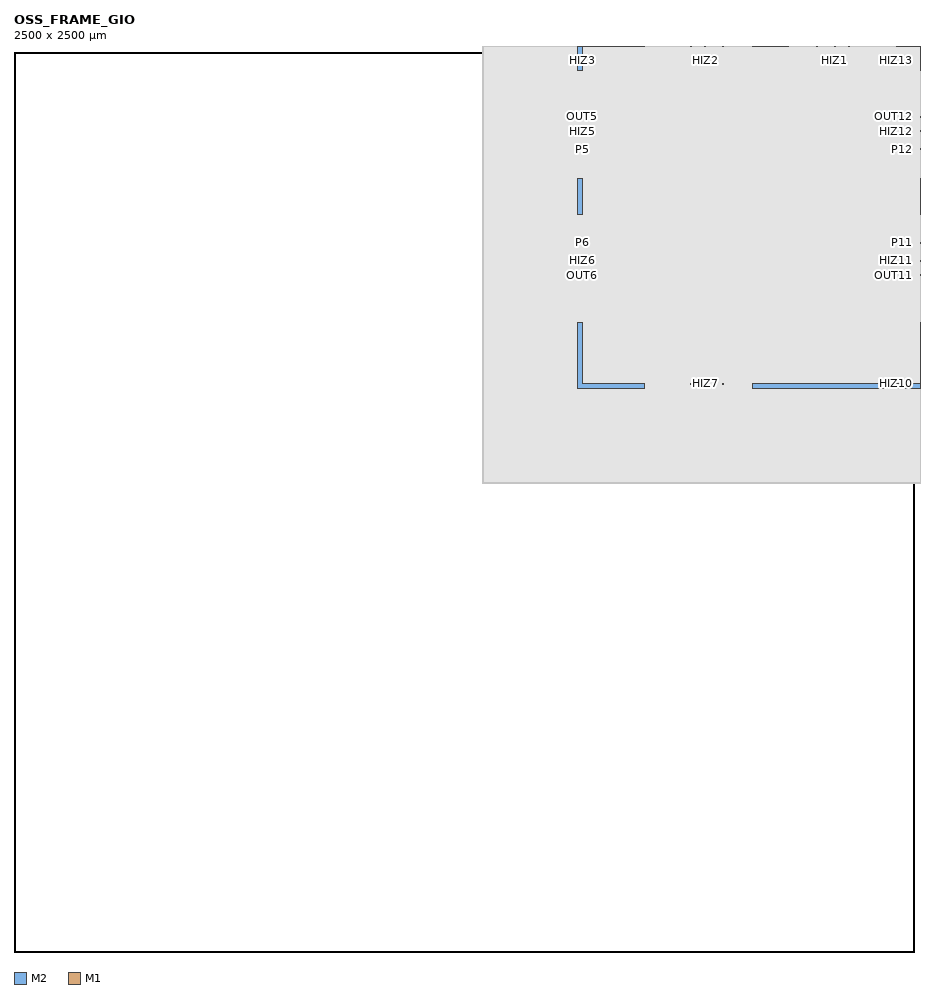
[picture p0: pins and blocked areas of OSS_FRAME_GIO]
MACRO OSS_FRAME_GIO
    CLASS COVER ;
    FOREIGN OSS_FRAME_GIO 1250.000 1250.000 ;
    ORIGIN 1250.000 1250.000 ;
    SIZE 2500.000 BY 2500.000 ;

    PIN HIZ1
        DIRECTION INPUT ;
        USE SIGNAL ;
        PORT
            LAYER M2 ;
                RECT 1028.300 2170.000 1031.700 2173.400 ;
        END
    END HIZ1

    PIN HIZ10
        DIRECTION INPUT ;
        USE SIGNAL ;
        PORT
            LAYER M2 ;
                RECT 1828.300 326.600 1831.700 330.000 ;
        END
    END HIZ10

    PIN HIZ11
        DIRECTION INPUT ;
        USE SIGNAL ;
        PORT
            LAYER M2 ;
                RECT 2170.000 668.300 2173.400 671.700 ;
        END
    END HIZ11

    PIN HIZ12
        DIRECTION INPUT ;
        USE SIGNAL ;
        PORT
            LAYER M2 ;
                RECT 2170.000 1028.300 2173.400 1031.700 ;
        END
    END HIZ12

    PIN HIZ13
        DIRECTION INPUT ;
        USE SIGNAL ;
        PORT
            LAYER M2 ;
                RECT 2170.000 1468.300 2173.400 1471.700 ;
        END
    END HIZ13

    PIN HIZ14
        DIRECTION INPUT ;
        USE SIGNAL ;
        PORT
            LAYER M2 ;
                RECT 2170.000 1828.300 2173.400 1831.700 ;
        END
    END HIZ14

    PIN HIZ15
        DIRECTION INPUT ;
        USE SIGNAL ;
        PORT
            LAYER M2 ;
                RECT 1828.300 2170.000 1831.700 2173.400 ;
        END
    END HIZ15

    PIN HIZ2
        DIRECTION INPUT ;
        USE SIGNAL ;
        PORT
            LAYER M2 ;
                RECT 668.300 2170.000 671.700 2173.400 ;
        END
    END HIZ2

    PIN HIZ3
        DIRECTION INPUT ;
        USE SIGNAL ;
        PORT
            LAYER M2 ;
                RECT 326.600 1828.300 330.000 1831.700 ;
        END
    END HIZ3

    PIN HIZ4
        DIRECTION INPUT ;
        USE SIGNAL ;
        PORT
            LAYER M2 ;
                RECT 326.600 1468.300 330.000 1471.700 ;
        END
    END HIZ4

    PIN HIZ5
        DIRECTION INPUT ;
        USE SIGNAL ;
        PORT
            LAYER M2 ;
                RECT 326.600 1028.300 330.000 1031.700 ;
        END
    END HIZ5

    PIN HIZ6
        DIRECTION INPUT ;
        USE SIGNAL ;
        PORT
            LAYER M2 ;
                RECT 326.600 668.300 330.000 671.700 ;
        END
    END HIZ6

    PIN HIZ7
        DIRECTION INPUT ;
        USE SIGNAL ;
        PORT
            LAYER M2 ;
                RECT 668.300 326.600 671.700 330.000 ;
        END
    END HIZ7

    PIN HIZ9
        DIRECTION INPUT ;
        USE SIGNAL ;
        PORT
            LAYER M2 ;
                RECT 1468.300 326.600 1471.700 330.000 ;
        END
    END HIZ9

    PIN OUT1
        DIRECTION INPUT ;
        USE SIGNAL ;
        PORT
            LAYER M2 ;
                RECT 1068.300 2170.000 1071.700 2173.400 ;
        END
    END OUT1

    PIN OUT10
        DIRECTION INPUT ;
        USE SIGNAL ;
        PORT
            LAYER M2 ;
                RECT 1868.300 326.600 1871.700 330.000 ;
        END
    END OUT10

    PIN OUT11
        DIRECTION INPUT ;
        USE SIGNAL ;
        PORT
            LAYER M2 ;
                RECT 2170.000 628.300 2173.400 631.700 ;
        END
    END OUT11

    PIN OUT12
        DIRECTION INPUT ;
        USE SIGNAL ;
        PORT
            LAYER M2 ;
                RECT 2170.000 1068.300 2173.400 1071.700 ;
        END
    END OUT12

    PIN OUT13
        DIRECTION INPUT ;
        USE SIGNAL ;
        PORT
            LAYER M2 ;
                RECT 2170.000 1428.300 2173.400 1431.700 ;
        END
    END OUT13

    PIN OUT14
        DIRECTION INPUT ;
        USE SIGNAL ;
        PORT
            LAYER M2 ;
                RECT 2170.000 1868.300 2173.400 1871.700 ;
        END
    END OUT14

    PIN OUT15
        DIRECTION INPUT ;
        USE SIGNAL ;
        PORT
            LAYER M2 ;
                RECT 1868.300 2170.000 1871.700 2173.400 ;
        END
    END OUT15

    PIN OUT2
        DIRECTION INPUT ;
        USE SIGNAL ;
        PORT
            LAYER M2 ;
                RECT 628.300 2170.000 631.700 2173.400 ;
        END
    END OUT2

    PIN OUT3
        DIRECTION INPUT ;
        USE SIGNAL ;
        PORT
            LAYER M2 ;
                RECT 326.600 1868.300 330.000 1871.700 ;
        END
    END OUT3

    PIN OUT4
        DIRECTION INPUT ;
        USE SIGNAL ;
        PORT
            LAYER M2 ;
                RECT 326.600 1428.300 330.000 1431.700 ;
        END
    END OUT4

    PIN OUT5
        DIRECTION INPUT ;
        USE SIGNAL ;
        PORT
            LAYER M2 ;
                RECT 326.600 1068.300 330.000 1071.700 ;
        END
    END OUT5

    PIN OUT6
        DIRECTION INPUT ;
        USE SIGNAL ;
        PORT
            LAYER M2 ;
                RECT 326.600 628.300 330.000 631.700 ;
        END
    END OUT6

    PIN OUT7
        DIRECTION INPUT ;
        USE SIGNAL ;
        PORT
            LAYER M2 ;
                RECT 628.300 326.600 631.700 330.000 ;
        END
    END OUT7

    PIN OUT9
        DIRECTION INPUT ;
        USE SIGNAL ;
        PORT
            LAYER M2 ;
                RECT 1428.300 326.600 1431.700 330.000 ;
        END
    END OUT9

    PIN P1
        DIRECTION OUTPUT ;
        USE SIGNAL ;
        PORT
            LAYER M2 ;
                RECT 978.300 2170.000 981.700 2173.400 ;
        END
    END P1

    PIN P10
        DIRECTION OUTPUT ;
        USE SIGNAL ;
        PORT
            LAYER M2 ;
                RECT 1778.300 326.600 1781.700 330.000 ;
        END
    END P10

    PIN P11
        DIRECTION OUTPUT ;
        USE SIGNAL ;
        PORT
            LAYER M2 ;
                RECT 2170.000 718.300 2173.400 721.700 ;
        END
    END P11

    PIN P12
        DIRECTION OUTPUT ;
        USE SIGNAL ;
        PORT
            LAYER M2 ;
                RECT 2170.000 978.300 2173.400 981.700 ;
        END
    END P12

    PIN P13
        DIRECTION OUTPUT ;
        USE SIGNAL ;
        PORT
            LAYER M2 ;
                RECT 2170.000 1518.300 2173.400 1521.700 ;
        END
    END P13

    PIN P14
        DIRECTION OUTPUT ;
        USE SIGNAL ;
        PORT
            LAYER M2 ;
                RECT 2170.000 1778.300 2173.400 1781.700 ;
        END
    END P14

    PIN P15
        DIRECTION OUTPUT ;
        USE SIGNAL ;
        PORT
            LAYER M2 ;
                RECT 1778.300 2170.000 1781.700 2173.400 ;
        END
    END P15

    PIN P2
        DIRECTION OUTPUT ;
        USE SIGNAL ;
        PORT
            LAYER M2 ;
                RECT 718.300 2170.000 721.700 2173.400 ;
        END
    END P2

    PIN P3
        DIRECTION OUTPUT ;
        USE SIGNAL ;
        PORT
            LAYER M2 ;
                RECT 326.600 1778.300 330.000 1781.700 ;
        END
    END P3

    PIN P4
        DIRECTION OUTPUT ;
        USE SIGNAL ;
        PORT
            LAYER M2 ;
                RECT 326.600 1518.300 330.000 1521.700 ;
        END
    END P4

    PIN P5
        DIRECTION OUTPUT ;
        USE SIGNAL ;
        PORT
            LAYER M2 ;
                RECT 326.600 978.300 330.000 981.700 ;
        END
    END P5

    PIN P6
        DIRECTION OUTPUT ;
        USE SIGNAL ;
        PORT
            LAYER M2 ;
                RECT 326.600 718.300 330.000 721.700 ;
        END
    END P6

    PIN P7
        DIRECTION OUTPUT ;
        USE SIGNAL ;
        PORT
            LAYER M2 ;
                RECT 718.300 326.600 721.700 330.000 ;
        END
    END P7

    PIN P9
        DIRECTION OUTPUT ;
        USE SIGNAL ;
        PORT
            LAYER M2 ;
                RECT 1518.300 326.600 1521.700 330.000 ;
        END
    END P9

    PIN VDD
        DIRECTION INOUT ;
        USE POWER ;
        PORT
            LAYER M1 ;
                RECT 1300.000 2170.000 1600.000 2184.000 ;
        END
    END VDD

    PIN VSS
        DIRECTION INOUT ;
        USE GROUND ;
        PORT
            LAYER M2 ;
                RECT 800.000 2170.000 900.000 2184.000 ;
            LAYER M2 ;
                RECT 1200.000 2170.000 1700.000 2184.000 ;
            LAYER M2 ;
                POLYGON 2170.000 2000.000  2170.000 2170.000  2000.000 2170.000  2000.000 2184.000  2184.000 2184.000  2184.000 2000.000 ;
            LAYER M2 ;
                RECT 316.000 1600.000 330.000 1700.000 ;
            LAYER M2 ;
                RECT 316.000 1200.000 330.000 1300.000 ;
            LAYER M2 ;
                RECT 316.000 800.000 330.000 900.000 ;
            LAYER M2 ;
                POLYGON 316.000 316.000  316.000 500.000  330.000 500.000  330.000 330.000  500.000 330.000  500.000 316.000 ;
            LAYER M2 ;
                RECT 800.000 316.000 1300.000 330.000 ;
            LAYER M2 ;
                RECT 1600.000 316.000 1700.000 330.000 ;
            LAYER M2 ;
                POLYGON 2000.000 316.000  2000.000 330.000  2170.000 330.000  2170.000 500.000  2184.000 500.000  2184.000 316.000 ;
            LAYER M2 ;
                RECT 2170.000 800.000 2184.000 900.000 ;
            LAYER M2 ;
                RECT 2170.000 1200.000 2184.000 1300.000 ;
            LAYER M2 ;
                RECT 2170.000 1600.000 2184.000 1700.000 ;
            LAYER M2 ;
                POLYGON 316.000 2000.000  316.000 2184.000  500.000 2184.000  500.000 2170.000  330.000 2170.000  330.000 2000.000 ;
        END
    END VSS

    OBS
        LAYER M1 ;
            POLYGON 90.000 90.000  90.000 2410.000  2410.000 2410.000  2410.000 90.000 ;
            POLYGON 52.000 52.000  52.000 2448.000  2448.000 2448.000  2448.000 52.000 ;
            POLYGON 2192.400 1835.100  2192.400 1835.400  2190.400 1835.400  2190.400 1838.000  2192.400 1838.000  2192.400 1840.200  2182.400 1840.200  2182.400 1842.800  2192.400 1842.800  2192.400 1848.700  2177.200 1848.700  2177.200 1848.300  2170.000 1848.300  2170.000 1851.700  2177.200 1851.700  2177.200 1851.300  2192.400 1851.300  2192.400 1858.400  2183.200 1858.400  2183.200 1862.000  2182.400 1862.000  2182.400 1864.600  2185.000 1864.600  2185.000 1860.200  2192.400 1860.200  2192.400 1862.000  2190.400 1862.000  2190.400 1864.600  2192.400 1864.600  2192.400 1864.900  2195.000 1864.900  2195.000 1851.300  2200.000 1851.300  2200.000 1848.700  2195.000 1848.700  2195.000 1835.100 ;
            POLYGON 2226.000 1772.000  2226.000 1778.300  2170.000 1778.300  2170.000 1781.700  2226.000 1781.700  2226.000 1812.000  2240.000 1812.000  2240.000 1928.000  2340.000 1928.000  2340.000 1772.000 ;
            POLYGON 2180.900 1788.700  2180.900 1791.300  2192.400 1791.300  2192.400 1809.300  2182.400 1809.300  2182.400 1817.700  2185.000 1817.700  2185.000 1811.100  2192.400 1811.100  2192.400 1812.900  2190.400 1812.900  2190.400 1817.900  2195.000 1817.900  2195.000 1791.300  2206.800 1791.300  2206.800 1908.700  2195.000 1908.700  2195.000 1882.100  2190.400 1882.100  2190.400 1894.100  2182.400 1894.100  2182.400 1898.700  2190.400 1898.700  2190.400 1908.700  2180.900 1908.700  2180.900 1911.300  2192.000 1911.300  2192.000 2018.000  2222.800 2018.000  2222.800 2021.400  2356.700 2021.400  2356.700 2018.000  2383.500 2018.000  2383.500 1942.000  2200.000 1942.000  2200.000 1911.300  2208.600 1911.300  2208.600 1788.700 ;
            POLYGON 1848.300 2170.000  1848.300 2177.200  1848.700 2177.200  1848.700 2192.400  1842.800 2192.400  1842.800 2182.400  1840.200 2182.400  1840.200 2192.400  1838.000 2192.400  1838.000 2190.400  1835.400 2190.400  1835.400 2192.400  1835.100 2192.400  1835.100 2195.000  1848.700 2195.000  1848.700 2200.000  1851.300 2200.000  1851.300 2195.000  1864.900 2195.000  1864.900 2192.400  1864.600 2192.400  1864.600 2190.400  1862.000 2190.400  1862.000 2192.400  1860.200 2192.400  1860.200 2185.000  1864.600 2185.000  1864.600 2182.400  1862.000 2182.400  1862.000 2183.200  1858.400 2183.200  1858.400 2192.400  1851.300 2192.400  1851.300 2177.200  1851.700 2177.200  1851.700 2170.000 ;
            POLYGON 1778.300 2170.000  1778.300 2226.000  1772.000 2226.000  1772.000 2340.000  1928.000 2340.000  1928.000 2240.000  1812.000 2240.000  1812.000 2226.000  1781.700 2226.000  1781.700 2170.000 ;
            POLYGON 1788.700 2180.900  1788.700 2208.600  1911.300 2208.600  1911.300 2200.000  1942.000 2200.000  1942.000 2383.500  2018.000 2383.500  2018.000 2356.700  2021.400 2356.700  2021.400 2222.800  2018.000 2222.800  2018.000 2192.000  1911.300 2192.000  1911.300 2180.900  1908.700 2180.900  1908.700 2190.400  1898.700 2190.400  1898.700 2182.400  1894.100 2182.400  1894.100 2190.400  1882.100 2190.400  1882.100 2195.000  1908.700 2195.000  1908.700 2206.800  1791.300 2206.800  1791.300 2195.000  1817.900 2195.000  1817.900 2190.400  1812.900 2190.400  1812.900 2192.400  1811.100 2192.400  1811.100 2185.000  1817.700 2185.000  1817.700 2182.400  1809.300 2182.400  1809.300 2192.400  1791.300 2192.400  1791.300 2180.900 ;
            POLYGON 2178.400 1853.700  2178.400 1856.300  2181.000 1856.300  2181.000 1853.700 ;
            POLYGON 2202.000 1946.800  2202.000 1953.700  2205.400 1953.700  2205.400 1949.400  2223.200 1949.400  2223.200 1953.600  2225.800 1953.600  2225.800 1949.400  2234.200 1949.400  2234.200 1953.600  2236.800 1953.600  2236.800 1949.400  2253.200 1949.400  2253.200 1953.600  2255.800 1953.600  2255.800 1949.400  2264.200 1949.400  2264.200 1953.600  2266.800 1953.600  2266.800 1949.400  2283.200 1949.400  2283.200 1953.600  2285.800 1953.600  2285.800 1949.400  2294.200 1949.400  2294.200 1953.600  2296.800 1953.600  2296.800 1946.800 ;
            POLYGON 2209.000 1951.600  2209.000 1955.000  2209.500 1955.000  2209.500 2005.000  2209.000 2005.000  2209.000 2011.300  2218.200 2011.300  2218.200 2005.000  2217.700 2005.000  2217.700 1955.000  2218.200 1955.000  2218.200 1951.600 ;
            POLYGON 2228.300 1951.600  2228.300 1955.000  2227.300 1955.000  2227.300 2005.000  2226.800 2005.000  2226.800 2011.300  2233.200 2011.300  2233.200 2005.000  2232.700 2005.000  2232.700 1955.000  2231.700 1955.000  2231.700 1951.600 ;
            POLYGON 2240.400 1951.600  2240.400 1955.000  2239.500 1955.000  2239.500 2005.000  2240.400 2005.000  2240.400 2011.300  2249.600 2011.300  2249.600 2005.000  2250.500 2005.000  2250.500 1955.000  2249.600 1955.000  2249.600 1951.600 ;
            POLYGON 2258.300 1951.600  2258.300 1955.000  2257.300 1955.000  2257.300 2005.000  2256.800 2005.000  2256.800 2011.300  2263.200 2011.300  2263.200 2005.000  2262.700 2005.000  2262.700 1955.000  2261.700 1955.000  2261.700 1951.600 ;
            POLYGON 2270.400 1951.600  2270.400 1955.000  2269.500 1955.000  2269.500 2005.000  2270.400 2005.000  2270.400 2011.300  2279.600 2011.300  2279.600 2005.000  2280.500 2005.000  2280.500 1955.000  2279.600 1955.000  2279.600 1951.600 ;
            POLYGON 2288.300 1951.600  2288.300 1955.000  2287.300 1955.000  2287.300 2005.000  2286.800 2005.000  2286.800 2011.300  2293.200 2011.300  2293.200 2005.000  2292.700 2005.000  2292.700 1955.000  2291.700 1955.000  2291.700 1951.600 ;
            POLYGON 2300.400 1951.600  2300.400 1955.000  2299.500 1955.000  2299.500 2005.000  2300.400 2005.000  2300.400 2011.300  2309.600 2011.300  2309.600 2005.000  2310.500 2005.000  2310.500 1955.000  2309.600 1955.000  2309.600 1951.600 ;
            POLYGON 2318.300 1951.600  2318.300 1955.000  2317.300 1955.000  2317.300 2005.000  2316.800 2005.000  2316.800 2011.300  2323.200 2011.300  2323.200 2005.000  2322.700 2005.000  2322.700 1955.000  2321.700 1955.000  2321.700 1951.600 ;
            POLYGON 2330.400 1951.600  2330.400 1955.000  2329.500 1955.000  2329.500 2005.000  2330.400 2005.000  2330.400 2011.300  2339.600 2011.300  2339.600 2005.000  2340.500 2005.000  2340.500 1955.000  2339.600 1955.000  2339.600 1951.600 ;
            POLYGON 2348.200 1951.600  2348.200 1955.000  2347.300 1955.000  2347.300 2005.000  2346.800 2005.000  2346.800 2011.300  2353.200 2011.300  2353.200 2005.000  2352.700 2005.000  2352.700 1955.000  2351.600 1955.000  2351.600 1951.600 ;
            POLYGON 2361.800 1951.600  2361.800 1955.000  2362.300 1955.000  2362.300 2005.000  2361.800 2005.000  2361.800 2011.300  2371.000 2011.300  2371.000 2005.000  2370.500 2005.000  2370.500 1955.000  2371.000 1955.000  2371.000 1951.600 ;
            POLYGON 2172.000 1861.400  2172.000 1868.300  2170.000 1868.300  2170.000 1871.700  2176.200 1871.700  2176.200 1868.300  2175.600 1868.300  2175.600 1861.400 ;
            POLYGON 1868.300 2170.000  1868.300 2172.000  1861.400 2172.000  1861.400 2175.600  1868.300 2175.600  1868.300 2176.200  1871.700 2176.200  1871.700 2170.000 ;
            POLYGON 1853.700 2178.400  1853.700 2181.000  1856.300 2181.000  1856.300 2178.400 ;
            POLYGON 1862.000 2178.400  1862.000 2181.000  1904.400 2181.000  1904.400 2188.000  1907.000 2188.000  1907.000 2185.400  1906.200 2185.400  1906.200 2178.400  1894.100 2178.400  1894.100 2179.200  1864.600 2179.200  1864.600 2178.400 ;
            POLYGON 1882.900 2184.200  1882.900 2185.000  1872.100 2185.000  1872.100 2187.200  1864.600 2187.200  1864.600 2186.400  1862.000 2186.400  1862.000 2189.000  1872.100 2189.000  1872.100 2192.600  1871.700 2192.600  1871.700 2195.200  1874.300 2195.200  1874.300 2192.600  1873.900 2192.600  1873.900 2186.800  1891.500 2186.800  1891.500 2184.200 ;
            POLYGON 2186.400 1862.000  2186.400 1864.600  2187.200 1864.600  2187.200 1872.100  2185.000 1872.100  2185.000 1882.900  2184.200 1882.900  2184.200 1891.500  2186.800 1891.500  2186.800 1873.900  2192.600 1873.900  2192.600 1874.300  2195.200 1874.300  2195.200 1871.700  2192.600 1871.700  2192.600 1872.100  2189.000 1872.100  2189.000 1862.000 ;
            POLYGON 1858.300 2196.400  1858.300 2199.000  1903.900 2199.000  1903.900 2205.400  1907.300 2205.400  1907.300 2196.400  1882.100 2196.400  1882.100 2197.200  1864.900 2197.200  1864.900 2196.400 ;
            POLYGON 1951.600 2209.000  1951.600 2218.200  1955.000 2218.200  1955.000 2217.700  2005.000 2217.700  2005.000 2218.200  2011.300 2218.200  2011.300 2209.000  2005.000 2209.000  2005.000 2209.500  1955.000 2209.500  1955.000 2209.000 ;
            POLYGON 2005.000 2226.800  2005.000 2227.300  1955.000 2227.300  1955.000 2228.300  1951.600 2228.300  1951.600 2231.700  1955.000 2231.700  1955.000 2232.700  2005.000 2232.700  2005.000 2233.200  2011.300 2233.200  2011.300 2226.800 ;
            POLYGON 1955.000 2239.500  1955.000 2240.400  1951.600 2240.400  1951.600 2249.600  1955.000 2249.600  1955.000 2250.500  2005.000 2250.500  2005.000 2249.600  2011.300 2249.600  2011.300 2240.400  2005.000 2240.400  2005.000 2239.500 ;
            POLYGON 2005.000 2256.800  2005.000 2257.300  1955.000 2257.300  1955.000 2258.300  1951.600 2258.300  1951.600 2261.700  1955.000 2261.700  1955.000 2262.700  2005.000 2262.700  2005.000 2263.200  2011.300 2263.200  2011.300 2256.800 ;
            POLYGON 1955.000 2269.500  1955.000 2270.400  1951.600 2270.400  1951.600 2279.600  1955.000 2279.600  1955.000 2280.500  2005.000 2280.500  2005.000 2279.600  2011.300 2279.600  2011.300 2270.400  2005.000 2270.400  2005.000 2269.500 ;
            POLYGON 2005.000 2286.800  2005.000 2287.300  1955.000 2287.300  1955.000 2288.300  1951.600 2288.300  1951.600 2291.700  1955.000 2291.700  1955.000 2292.700  2005.000 2292.700  2005.000 2293.200  2011.300 2293.200  2011.300 2286.800 ;
            POLYGON 1946.800 2202.000  1946.800 2296.800  1953.600 2296.800  1953.600 2294.200  1949.400 2294.200  1949.400 2285.800  1953.600 2285.800  1953.600 2283.200  1949.400 2283.200  1949.400 2266.800  1953.600 2266.800  1953.600 2264.200  1949.400 2264.200  1949.400 2255.800  1953.600 2255.800  1953.600 2253.200  1949.400 2253.200  1949.400 2236.800  1953.600 2236.800  1953.600 2234.200  1949.400 2234.200  1949.400 2225.800  1953.600 2225.800  1953.600 2223.200  1949.400 2223.200  1949.400 2205.400  1953.700 2205.400  1953.700 2202.000 ;
            POLYGON 1955.000 2299.500  1955.000 2300.400  1951.600 2300.400  1951.600 2309.600  1955.000 2309.600  1955.000 2310.500  2005.000 2310.500  2005.000 2309.600  2011.300 2309.600  2011.300 2300.400  2005.000 2300.400  2005.000 2299.500 ;
            POLYGON 2005.000 2316.800  2005.000 2317.300  1955.000 2317.300  1955.000 2318.300  1951.600 2318.300  1951.600 2321.700  1955.000 2321.700  1955.000 2322.700  2005.000 2322.700  2005.000 2323.200  2011.300 2323.200  2011.300 2316.800 ;
            POLYGON 2178.400 1862.000  2178.400 1864.600  2179.200 1864.600  2179.200 1894.100  2178.400 1894.100  2178.400 1906.200  2185.400 1906.200  2185.400 1907.000  2188.000 1907.000  2188.000 1904.400  2181.000 1904.400  2181.000 1862.000 ;
            POLYGON 1955.000 2329.500  1955.000 2330.400  1951.600 2330.400  1951.600 2339.600  1955.000 2339.600  1955.000 2340.500  2005.000 2340.500  2005.000 2339.600  2011.300 2339.600  2011.300 2330.400  2005.000 2330.400  2005.000 2329.500 ;
            POLYGON 2005.000 2346.800  2005.000 2347.300  1955.000 2347.300  1955.000 2348.200  1951.600 2348.200  1951.600 2351.600  1955.000 2351.600  1955.000 2352.700  2005.000 2352.700  2005.000 2353.200  2011.300 2353.200  2011.300 2346.800 ;
            POLYGON 1951.600 2361.800  1951.600 2371.000  1955.000 2371.000  1955.000 2370.500  2005.000 2370.500  2005.000 2371.000  2011.300 2371.000  2011.300 2361.800  2005.000 2361.800  2005.000 2362.300  1955.000 2362.300  1955.000 2361.800 ;
            POLYGON 2196.400 1858.300  2196.400 1864.900  2197.200 1864.900  2197.200 1882.100  2196.400 1882.100  2196.400 1907.300  2205.400 1907.300  2205.400 1903.900  2199.000 1903.900  2199.000 1858.300 ;
            POLYGON 1695.000 2239.500  1695.000 2240.400  1688.700 2240.400  1688.700 2249.600  1695.000 2249.600  1695.000 2250.500  1745.000 2250.500  1745.000 2249.600  1748.400 2249.600  1748.400 2240.400  1745.000 2240.400  1745.000 2239.500 ;
            POLYGON 1792.700 2196.400  1792.700 2205.400  1796.100 2205.400  1796.100 2199.000  1841.700 2199.000  1841.700 2196.400  1835.100 2196.400  1835.100 2197.200  1817.900 2197.200  1817.900 2196.400 ;
            POLYGON 1746.300 2202.000  1746.300 2205.400  1750.000 2205.400  1750.000 2223.200  1746.400 2223.200  1746.400 2225.800  1750.000 2225.800  1750.000 2234.200  1746.400 2234.200  1746.400 2236.800  1750.000 2236.800  1750.000 2253.200  1746.400 2253.200  1746.400 2255.800  1751.800 2255.800  1751.800 2202.000 ;
            POLYGON 1345.000 2256.800  1345.000 2257.300  1295.000 2257.300  1295.000 2258.300  1291.600 2258.300  1291.600 2261.700  1295.000 2261.700  1295.000 2262.700  1345.000 2262.700  1345.000 2263.200  1351.300 2263.200  1351.300 2256.800 ;
            POLYGON 1605.000 2256.800  1605.000 2257.300  1555.000 2257.300  1555.000 2258.300  1551.600 2258.300  1551.600 2261.700  1555.000 2261.700  1555.000 2262.700  1605.000 2262.700  1605.000 2263.200  1611.300 2263.200  1611.300 2256.800 ;
            POLYGON 1688.700 2256.800  1688.700 2263.200  1695.000 2263.200  1695.000 2262.700  1745.000 2262.700  1745.000 2261.700  1748.400 2261.700  1748.400 2258.300  1745.000 2258.300  1745.000 2257.300  1695.000 2257.300  1695.000 2256.800 ;
            POLYGON 1835.400 2184.200  1835.400 2186.400  1812.900 2186.400  1812.900 2189.000  1817.900 2189.000  1817.900 2188.200  1826.100 2188.200  1826.100 2192.600  1825.700 2192.600  1825.700 2195.200  1828.300 2195.200  1828.300 2192.600  1827.900 2192.600  1827.900 2188.200  1837.200 2188.200  1837.200 2186.800  1838.000 2186.800  1838.000 2184.200 ;
            POLYGON 1295.000 2269.500  1295.000 2270.400  1291.600 2270.400  1291.600 2279.600  1295.000 2279.600  1295.000 2280.500  1345.000 2280.500  1345.000 2279.600  1351.300 2279.600  1351.300 2270.400  1345.000 2270.400  1345.000 2269.500 ;
            POLYGON 1555.000 2269.500  1555.000 2270.400  1551.600 2270.400  1551.600 2279.600  1555.000 2279.600  1555.000 2280.500  1605.000 2280.500  1605.000 2279.600  1611.300 2279.600  1611.300 2270.400  1605.000 2270.400  1605.000 2269.500 ;
            POLYGON 1695.000 2269.500  1695.000 2270.400  1688.700 2270.400  1688.700 2279.600  1695.000 2279.600  1695.000 2280.500  1745.000 2280.500  1745.000 2279.600  1748.400 2279.600  1748.400 2270.400  1745.000 2270.400  1745.000 2269.500 ;
            POLYGON 1291.600 2209.000  1291.600 2218.200  1295.000 2218.200  1295.000 2217.700  1345.000 2217.700  1345.000 2218.200  1351.300 2218.200  1351.300 2209.000  1345.000 2209.000  1345.000 2209.500  1295.000 2209.500  1295.000 2209.000 ;
            POLYGON 1345.000 2286.800  1345.000 2287.300  1295.000 2287.300  1295.000 2288.300  1291.600 2288.300  1291.600 2291.700  1295.000 2291.700  1295.000 2292.700  1345.000 2292.700  1345.000 2293.200  1351.300 2293.200  1351.300 2286.800 ;
            POLYGON 1605.000 2286.800  1605.000 2287.300  1555.000 2287.300  1555.000 2288.300  1551.600 2288.300  1551.600 2291.700  1555.000 2291.700  1555.000 2292.700  1605.000 2292.700  1605.000 2293.200  1611.300 2293.200  1611.300 2286.800 ;
            POLYGON 1688.700 2286.800  1688.700 2293.200  1695.000 2293.200  1695.000 2292.700  1745.000 2292.700  1745.000 2291.700  1748.400 2291.700  1748.400 2288.300  1745.000 2288.300  1745.000 2287.300  1695.000 2287.300  1695.000 2286.800 ;
            POLYGON 1551.600 2209.000  1551.600 2218.200  1555.000 2218.200  1555.000 2217.700  1605.000 2217.700  1605.000 2218.200  1611.300 2218.200  1611.300 2209.000  1605.000 2209.000  1605.000 2209.500  1555.000 2209.500  1555.000 2209.000 ;
            POLYGON 1688.700 2209.000  1688.700 2218.200  1695.000 2218.200  1695.000 2217.700  1745.000 2217.700  1745.000 2218.200  1748.400 2218.200  1748.400 2209.000  1745.000 2209.000  1745.000 2209.500  1695.000 2209.500  1695.000 2209.000 ;
            POLYGON 1295.000 2299.500  1295.000 2300.400  1291.600 2300.400  1291.600 2309.600  1295.000 2309.600  1295.000 2310.500  1345.000 2310.500  1345.000 2309.600  1351.300 2309.600  1351.300 2300.400  1345.000 2300.400  1345.000 2299.500 ;
            POLYGON 1555.000 2299.500  1555.000 2300.400  1551.600 2300.400  1551.600 2309.600  1555.000 2309.600  1555.000 2310.500  1605.000 2310.500  1605.000 2309.600  1611.300 2309.600  1611.300 2300.400  1605.000 2300.400  1605.000 2299.500 ;
            POLYGON 1695.000 2299.500  1695.000 2300.400  1688.700 2300.400  1688.700 2309.600  1695.000 2309.600  1695.000 2310.500  1745.000 2310.500  1745.000 2309.600  1748.400 2309.600  1748.400 2300.400  1745.000 2300.400  1745.000 2299.500 ;
            POLYGON 1813.100 2178.400  1813.100 2181.000  1844.700 2181.000  1844.700 2186.300  1847.300 2186.300  1847.300 2178.400  1840.200 2178.400  1840.200 2179.200  1818.000 2179.200  1818.000 2178.400 ;
            POLYGON 1345.000 2316.800  1345.000 2317.300  1295.000 2317.300  1295.000 2318.300  1291.600 2318.300  1291.600 2321.700  1295.000 2321.700  1295.000 2322.700  1345.000 2322.700  1345.000 2323.200  1351.300 2323.200  1351.300 2316.800 ;
            POLYGON 1605.000 2316.800  1605.000 2317.300  1555.000 2317.300  1555.000 2318.300  1551.600 2318.300  1551.600 2321.700  1555.000 2321.700  1555.000 2322.700  1605.000 2322.700  1605.000 2323.200  1611.300 2323.200  1611.300 2316.800 ;
            POLYGON 1688.700 2316.800  1688.700 2323.200  1695.000 2323.200  1695.000 2322.700  1745.000 2322.700  1745.000 2321.700  1748.400 2321.700  1748.400 2318.300  1745.000 2318.300  1745.000 2317.300  1695.000 2317.300  1695.000 2316.800 ;
            POLYGON 1345.000 2226.800  1345.000 2227.300  1295.000 2227.300  1295.000 2228.400  1291.600 2228.400  1291.600 2231.800  1295.000 2231.800  1295.000 2232.700  1345.000 2232.700  1345.000 2233.200  1351.300 2233.200  1351.300 2226.800 ;
            POLYGON 1605.000 2226.800  1605.000 2227.300  1555.000 2227.300  1555.000 2228.400  1551.600 2228.400  1551.600 2231.800  1555.000 2231.800  1555.000 2232.700  1605.000 2232.700  1605.000 2233.200  1611.300 2233.200  1611.300 2226.800 ;
            POLYGON 1295.000 2329.500  1295.000 2330.400  1291.600 2330.400  1291.600 2339.600  1295.000 2339.600  1295.000 2340.500  1345.000 2340.500  1345.000 2339.600  1351.300 2339.600  1351.300 2330.400  1345.000 2330.400  1345.000 2329.500 ;
            POLYGON 1555.000 2329.500  1555.000 2330.400  1551.600 2330.400  1551.600 2339.600  1555.000 2339.600  1555.000 2340.500  1605.000 2340.500  1605.000 2339.600  1611.300 2339.600  1611.300 2330.400  1605.000 2330.400  1605.000 2329.500 ;
            POLYGON 1695.000 2329.500  1695.000 2330.400  1688.700 2330.400  1688.700 2339.600  1695.000 2339.600  1695.000 2340.500  1745.000 2340.500  1745.000 2339.600  1748.400 2339.600  1748.400 2330.400  1745.000 2330.400  1745.000 2329.500 ;
            POLYGON 1688.700 2226.800  1688.700 2233.200  1695.000 2233.200  1695.000 2232.700  1745.000 2232.700  1745.000 2231.800  1748.400 2231.800  1748.400 2228.400  1745.000 2228.400  1745.000 2227.300  1695.000 2227.300  1695.000 2226.800 ;
            POLYGON 1345.000 2346.800  1345.000 2347.300  1295.000 2347.300  1295.000 2348.300  1291.600 2348.300  1291.600 2351.700  1295.000 2351.700  1295.000 2352.700  1345.000 2352.700  1345.000 2353.200  1351.300 2353.200  1351.300 2346.800 ;
            POLYGON 1605.000 2346.800  1605.000 2347.300  1555.000 2347.300  1555.000 2348.300  1551.600 2348.300  1551.600 2351.700  1555.000 2351.700  1555.000 2352.700  1605.000 2352.700  1605.000 2353.200  1611.300 2353.200  1611.300 2346.800 ;
            POLYGON 1688.700 2346.800  1688.700 2353.200  1695.000 2353.200  1695.000 2352.700  1745.000 2352.700  1745.000 2351.700  1748.400 2351.700  1748.400 2348.300  1745.000 2348.300  1745.000 2347.300  1695.000 2347.300  1695.000 2346.800 ;
            POLYGON 1828.300 2170.000  1828.300 2176.200  1831.700 2176.200  1831.700 2175.600  1843.200 2175.600  1843.200 2172.000  1831.700 2172.000  1831.700 2170.000 ;
            POLYGON 1291.600 2361.800  1291.600 2371.000  1295.000 2371.000  1295.000 2370.500  1345.000 2370.500  1345.000 2371.000  1351.300 2371.000  1351.300 2361.800  1345.000 2361.800  1345.000 2362.300  1295.000 2362.300  1295.000 2361.800 ;
            POLYGON 1551.600 2361.800  1551.600 2371.000  1555.000 2371.000  1555.000 2370.500  1605.000 2370.500  1605.000 2371.000  1611.300 2371.000  1611.300 2361.800  1605.000 2361.800  1605.000 2362.300  1555.000 2362.300  1555.000 2361.800 ;
            POLYGON 1688.700 2361.800  1688.700 2371.000  1695.000 2371.000  1695.000 2370.500  1745.000 2370.500  1745.000 2371.000  1748.400 2371.000  1748.400 2361.800  1745.000 2361.800  1745.000 2362.300  1695.000 2362.300  1695.000 2361.800 ;
            POLYGON 1295.000 2239.500  1295.000 2240.400  1291.600 2240.400  1291.600 2249.600  1295.000 2249.600  1295.000 2250.500  1345.000 2250.500  1345.000 2249.600  1351.300 2249.600  1351.300 2240.400  1345.000 2240.400  1345.000 2239.500 ;
            POLYGON 1400.000 2184.000  1400.000 2240.000  1361.400 2240.000  1361.400 2223.300  1358.000 2223.300  1358.000 2196.500  1282.000 2196.500  1282.000 2383.500  1358.000 2383.500  1358.000 2357.200  1361.400 2357.200  1361.400 2340.000  1500.000 2340.000  1500.000 2184.000  1460.000 2184.000  1460.000 2240.000  1440.000 2240.000  1440.000 2184.000 ;
            POLYGON 1542.000 2196.500  1542.000 2383.500  1618.000 2383.500  1618.000 2357.000  1621.400 2357.000  1621.400 2223.100  1618.000 2223.100  1618.000 2196.500 ;
            POLYGON 1682.000 2196.500  1682.000 2223.100  1678.600 2223.100  1678.600 2357.000  1682.000 2357.000  1682.000 2383.500  1758.000 2383.500  1758.000 2196.500 ;
            POLYGON 1555.000 2239.500  1555.000 2240.400  1551.600 2240.400  1551.600 2249.600  1555.000 2249.600  1555.000 2250.500  1605.000 2250.500  1605.000 2249.600  1611.300 2249.600  1611.300 2240.400  1605.000 2240.400  1605.000 2239.500 ;
            POLYGON 2300.400 1551.600  2300.400 1555.000  2299.500 1555.000  2299.500 1605.000  2300.400 1605.000  2300.400 1611.300  2309.600 1611.300  2309.600 1605.000  2310.500 1605.000  2310.500 1555.000  2309.600 1555.000  2309.600 1551.600 ;
            POLYGON 2318.300 1551.600  2318.300 1555.000  2317.300 1555.000  2317.300 1605.000  2316.800 1605.000  2316.800 1611.300  2323.200 1611.300  2323.200 1605.000  2322.700 1605.000  2322.700 1555.000  2321.700 1555.000  2321.700 1551.600 ;
            POLYGON 2330.400 1551.600  2330.400 1555.000  2329.500 1555.000  2329.500 1605.000  2330.400 1605.000  2330.400 1611.300  2339.600 1611.300  2339.600 1605.000  2340.500 1605.000  2340.500 1555.000  2339.600 1555.000  2339.600 1551.600 ;
            POLYGON 2348.300 1551.600  2348.300 1555.000  2347.300 1555.000  2347.300 1605.000  2346.800 1605.000  2346.800 1611.300  2353.200 1611.300  2353.200 1605.000  2352.700 1605.000  2352.700 1555.000  2351.700 1555.000  2351.700 1551.600 ;
            POLYGON 2361.800 1551.600  2361.800 1555.000  2362.300 1555.000  2362.300 1605.000  2361.800 1605.000  2361.800 1611.300  2371.000 1611.300  2371.000 1605.000  2370.500 1605.000  2370.500 1555.000  2371.000 1555.000  2371.000 1551.600 ;
            POLYGON 2196.500 1542.000  2196.500 1618.000  2223.100 1618.000  2223.100 1621.400  2357.000 1621.400  2357.000 1618.000  2383.500 1618.000  2383.500 1542.000 ;
            POLYGON 2209.000 1688.700  2209.000 1695.000  2209.500 1695.000  2209.500 1745.000  2209.000 1745.000  2209.000 1748.400  2218.200 1748.400  2218.200 1745.000  2217.700 1745.000  2217.700 1695.000  2218.200 1695.000  2218.200 1688.700 ;
            POLYGON 2226.800 1688.700  2226.800 1695.000  2227.300 1695.000  2227.300 1745.000  2228.400 1745.000  2228.400 1748.400  2231.800 1748.400  2231.800 1745.000  2232.700 1745.000  2232.700 1695.000  2233.200 1695.000  2233.200 1688.700 ;
            POLYGON 2240.400 1688.700  2240.400 1695.000  2239.500 1695.000  2239.500 1745.000  2240.400 1745.000  2240.400 1748.400  2249.600 1748.400  2249.600 1745.000  2250.500 1745.000  2250.500 1695.000  2249.600 1695.000  2249.600 1688.700 ;
            POLYGON 2256.800 1688.700  2256.800 1695.000  2257.300 1695.000  2257.300 1745.000  2258.300 1745.000  2258.300 1748.400  2261.700 1748.400  2261.700 1745.000  2262.700 1745.000  2262.700 1695.000  2263.200 1695.000  2263.200 1688.700 ;
            POLYGON 2270.400 1688.700  2270.400 1695.000  2269.500 1695.000  2269.500 1745.000  2270.400 1745.000  2270.400 1748.400  2279.600 1748.400  2279.600 1745.000  2280.500 1745.000  2280.500 1695.000  2279.600 1695.000  2279.600 1688.700 ;
            POLYGON 2286.800 1688.700  2286.800 1695.000  2287.300 1695.000  2287.300 1745.000  2288.300 1745.000  2288.300 1748.400  2291.700 1748.400  2291.700 1745.000  2292.700 1745.000  2292.700 1695.000  2293.200 1695.000  2293.200 1688.700 ;
            POLYGON 2300.400 1688.700  2300.400 1695.000  2299.500 1695.000  2299.500 1745.000  2300.400 1745.000  2300.400 1748.400  2309.600 1748.400  2309.600 1745.000  2310.500 1745.000  2310.500 1695.000  2309.600 1695.000  2309.600 1688.700 ;
            POLYGON 2316.800 1688.700  2316.800 1695.000  2317.300 1695.000  2317.300 1745.000  2318.300 1745.000  2318.300 1748.400  2321.700 1748.400  2321.700 1745.000  2322.700 1745.000  2322.700 1695.000  2323.200 1695.000  2323.200 1688.700 ;
            POLYGON 2330.400 1688.700  2330.400 1695.000  2329.500 1695.000  2329.500 1745.000  2330.400 1745.000  2330.400 1748.400  2339.600 1748.400  2339.600 1745.000  2340.500 1745.000  2340.500 1695.000  2339.600 1695.000  2339.600 1688.700 ;
            POLYGON 2346.800 1688.700  2346.800 1695.000  2347.300 1695.000  2347.300 1745.000  2348.300 1745.000  2348.300 1748.400  2351.700 1748.400  2351.700 1745.000  2352.700 1745.000  2352.700 1695.000  2353.200 1695.000  2353.200 1688.700 ;
            POLYGON 2361.800 1688.700  2361.800 1695.000  2362.300 1695.000  2362.300 1745.000  2361.800 1745.000  2361.800 1748.400  2371.000 1748.400  2371.000 1745.000  2370.500 1745.000  2370.500 1695.000  2371.000 1695.000  2371.000 1688.700 ;
            POLYGON 2202.000 1746.300  2202.000 1751.800  2255.800 1751.800  2255.800 1746.400  2253.200 1746.400  2253.200 1750.000  2236.800 1750.000  2236.800 1746.400  2234.200 1746.400  2234.200 1750.000  2225.800 1750.000  2225.800 1746.400  2223.200 1746.400  2223.200 1750.000  2205.400 1750.000  2205.400 1746.300 ;
            POLYGON 2223.100 1678.600  2223.100 1682.000  2196.500 1682.000  2196.500 1758.000  2383.500 1758.000  2383.500 1682.000  2357.000 1682.000  2357.000 1678.600 ;
            POLYGON 2186.400 1812.900  2186.400 1835.400  2184.200 1835.400  2184.200 1838.000  2186.800 1838.000  2186.800 1837.200  2188.200 1837.200  2188.200 1827.900  2192.600 1827.900  2192.600 1828.300  2195.200 1828.300  2195.200 1825.700  2192.600 1825.700  2192.600 1826.100  2188.200 1826.100  2188.200 1817.900  2189.000 1817.900  2189.000 1812.900 ;
            POLYGON 2196.400 1792.700  2196.400 1817.900  2197.200 1817.900  2197.200 1835.100  2196.400 1835.100  2196.400 1841.700  2199.000 1841.700  2199.000 1796.100  2205.400 1796.100  2205.400 1792.700 ;
            POLYGON 2170.000 1828.300  2170.000 1831.700  2172.000 1831.700  2172.000 1843.200  2175.600 1843.200  2175.600 1831.700  2176.200 1831.700  2176.200 1828.300 ;
            POLYGON 2178.400 1813.100  2178.400 1818.000  2179.200 1818.000  2179.200 1840.200  2178.400 1840.200  2178.400 1847.300  2186.300 1847.300  2186.300 1844.700  2181.000 1844.700  2181.000 1813.100 ;
            POLYGON 2240.400 1288.700  2240.400 1295.000  2239.500 1295.000  2239.500 1345.000  2240.400 1345.000  2240.400 1348.400  2249.600 1348.400  2249.600 1345.000  2250.500 1345.000  2250.500 1295.000  2249.600 1295.000  2249.600 1288.700 ;
            POLYGON 2256.800 1288.700  2256.800 1295.000  2257.300 1295.000  2257.300 1345.000  2258.300 1345.000  2258.300 1348.400  2261.700 1348.400  2261.700 1345.000  2262.700 1345.000  2262.700 1295.000  2263.200 1295.000  2263.200 1288.700 ;
            POLYGON 2270.400 1288.700  2270.400 1295.000  2269.500 1295.000  2269.500 1345.000  2270.400 1345.000  2270.400 1348.400  2279.600 1348.400  2279.600 1345.000  2280.500 1345.000  2280.500 1295.000  2279.600 1295.000  2279.600 1288.700 ;
            POLYGON 2286.800 1288.700  2286.800 1295.000  2287.300 1295.000  2287.300 1345.000  2288.300 1345.000  2288.300 1348.400  2291.700 1348.400  2291.700 1345.000  2292.700 1345.000  2292.700 1295.000  2293.200 1295.000  2293.200 1288.700 ;
            POLYGON 2300.400 1288.700  2300.400 1295.000  2299.500 1295.000  2299.500 1345.000  2300.400 1345.000  2300.400 1348.400  2309.600 1348.400  2309.600 1345.000  2310.500 1345.000  2310.500 1295.000  2309.600 1295.000  2309.600 1288.700 ;
            POLYGON 2316.800 1288.700  2316.800 1295.000  2317.300 1295.000  2317.300 1345.000  2318.300 1345.000  2318.300 1348.400  2321.700 1348.400  2321.700 1345.000  2322.700 1345.000  2322.700 1295.000  2323.200 1295.000  2323.200 1288.700 ;
            POLYGON 2330.400 1288.700  2330.400 1295.000  2329.500 1295.000  2329.500 1345.000  2330.400 1345.000  2330.400 1348.400  2339.600 1348.400  2339.600 1345.000  2340.500 1345.000  2340.500 1295.000  2339.600 1295.000  2339.600 1288.700 ;
            POLYGON 2346.800 1288.700  2346.800 1295.000  2347.300 1295.000  2347.300 1345.000  2348.200 1345.000  2348.200 1348.400  2351.600 1348.400  2351.600 1345.000  2352.700 1345.000  2352.700 1295.000  2353.200 1295.000  2353.200 1288.700 ;
            POLYGON 2361.800 1288.700  2361.800 1295.000  2362.300 1295.000  2362.300 1345.000  2361.800 1345.000  2361.800 1348.400  2371.000 1348.400  2371.000 1345.000  2370.500 1345.000  2370.500 1295.000  2371.000 1295.000  2371.000 1288.700 ;
            POLYGON 2202.000 1346.300  2202.000 1353.200  2296.800 1353.200  2296.800 1346.400  2294.200 1346.400  2294.200 1350.600  2285.800 1350.600  2285.800 1346.400  2283.200 1346.400  2283.200 1350.600  2266.800 1350.600  2266.800 1346.400  2264.200 1346.400  2264.200 1350.600  2255.800 1350.600  2255.800 1346.400  2253.200 1346.400  2253.200 1350.600  2236.800 1350.600  2236.800 1346.400  2234.200 1346.400  2234.200 1350.600  2225.800 1350.600  2225.800 1346.400  2223.200 1346.400  2223.200 1350.600  2205.400 1350.600  2205.400 1346.300 ;
            POLYGON 2185.400 1393.000  2185.400 1393.800  2178.400 1393.800  2178.400 1405.900  2179.200 1405.900  2179.200 1435.400  2178.400 1435.400  2178.400 1438.000  2181.000 1438.000  2181.000 1395.600  2188.000 1395.600  2188.000 1393.000 ;
            POLYGON 2184.200 1408.500  2184.200 1417.100  2185.000 1417.100  2185.000 1427.900  2187.200 1427.900  2187.200 1435.400  2186.400 1435.400  2186.400 1438.000  2189.000 1438.000  2189.000 1427.900  2192.600 1427.900  2192.600 1428.300  2195.200 1428.300  2195.200 1425.700  2192.600 1425.700  2192.600 1426.100  2186.800 1426.100  2186.800 1408.500 ;
            POLYGON 2170.000 1428.300  2170.000 1431.700  2172.000 1431.700  2172.000 1438.600  2175.600 1438.600  2175.600 1431.700  2176.200 1431.700  2176.200 1428.300 ;
            POLYGON 2196.400 1392.700  2196.400 1417.900  2197.200 1417.900  2197.200 1435.100  2196.400 1435.100  2196.400 1441.700  2199.000 1441.700  2199.000 1396.100  2205.400 1396.100  2205.400 1392.700 ;
            POLYGON 2178.400 1443.700  2178.400 1446.300  2181.000 1446.300  2181.000 1443.700 ;
            POLYGON 2192.400 1435.100  2192.400 1435.400  2190.400 1435.400  2190.400 1438.000  2192.400 1438.000  2192.400 1439.800  2185.000 1439.800  2185.000 1435.400  2182.400 1435.400  2182.400 1438.000  2183.200 1438.000  2183.200 1441.600  2192.400 1441.600  2192.400 1448.700  2177.200 1448.700  2177.200 1448.300  2170.000 1448.300  2170.000 1451.700  2177.200 1451.700  2177.200 1451.300  2192.400 1451.300  2192.400 1457.200  2182.400 1457.200  2182.400 1459.800  2192.400 1459.800  2192.400 1462.000  2190.400 1462.000  2190.400 1464.600  2192.400 1464.600  2192.400 1464.900  2195.000 1464.900  2195.000 1451.300  2200.000 1451.300  2200.000 1448.700  2195.000 1448.700  2195.000 1435.100 ;
            POLYGON 2172.000 1456.800  2172.000 1468.300  2170.000 1468.300  2170.000 1471.700  2176.200 1471.700  2176.200 1468.300  2175.600 1468.300  2175.600 1456.800 ;
            POLYGON 2178.400 1452.700  2178.400 1459.800  2179.200 1459.800  2179.200 1482.000  2178.400 1482.000  2178.400 1486.900  2181.000 1486.900  2181.000 1455.300  2186.300 1455.300  2186.300 1452.700 ;
            POLYGON 2184.200 1462.000  2184.200 1464.600  2186.400 1464.600  2186.400 1487.100  2189.000 1487.100  2189.000 1482.100  2188.200 1482.100  2188.200 1473.900  2192.600 1473.900  2192.600 1474.300  2195.200 1474.300  2195.200 1471.700  2192.600 1471.700  2192.600 1472.100  2188.200 1472.100  2188.200 1462.800  2186.800 1462.800  2186.800 1462.000 ;
            POLYGON 2196.400 1458.300  2196.400 1464.900  2197.200 1464.900  2197.200 1482.100  2196.400 1482.100  2196.400 1507.300  2205.400 1507.300  2205.400 1503.900  2199.000 1503.900  2199.000 1458.300 ;
            POLYGON 2222.800 1278.600  2222.800 1282.000  2192.000 1282.000  2192.000 1388.700  2180.900 1388.700  2180.900 1391.300  2190.400 1391.300  2190.400 1401.300  2182.400 1401.300  2182.400 1405.900  2190.400 1405.900  2190.400 1417.900  2195.000 1417.900  2195.000 1391.300  2206.800 1391.300  2206.800 1508.700  2195.000 1508.700  2195.000 1482.100  2190.400 1482.100  2190.400 1487.100  2192.400 1487.100  2192.400 1488.900  2185.000 1488.900  2185.000 1482.300  2182.400 1482.300  2182.400 1490.700  2192.400 1490.700  2192.400 1508.700  2180.900 1508.700  2180.900 1511.300  2208.600 1511.300  2208.600 1388.700  2200.000 1388.700  2200.000 1358.000  2383.500 1358.000  2383.500 1282.000  2356.700 1282.000  2356.700 1278.600 ;
            POLYGON 2240.000 1372.000  2240.000 1488.000  2226.000 1488.000  2226.000 1518.300  2170.000 1518.300  2170.000 1521.700  2226.000 1521.700  2226.000 1528.000  2340.000 1528.000  2340.000 1372.000 ;
            POLYGON 2202.000 1548.200  2202.000 1553.700  2205.400 1553.700  2205.400 1550.000  2223.200 1550.000  2223.200 1553.600  2225.800 1553.600  2225.800 1550.000  2234.200 1550.000  2234.200 1553.600  2236.800 1553.600  2236.800 1550.000  2253.200 1550.000  2253.200 1553.600  2255.800 1553.600  2255.800 1548.200 ;
            POLYGON 2209.000 1551.600  2209.000 1555.000  2209.500 1555.000  2209.500 1605.000  2209.000 1605.000  2209.000 1611.300  2218.200 1611.300  2218.200 1605.000  2217.700 1605.000  2217.700 1555.000  2218.200 1555.000  2218.200 1551.600 ;
            POLYGON 2228.400 1551.600  2228.400 1555.000  2227.300 1555.000  2227.300 1605.000  2226.800 1605.000  2226.800 1611.300  2233.200 1611.300  2233.200 1605.000  2232.700 1605.000  2232.700 1555.000  2231.800 1555.000  2231.800 1551.600 ;
            POLYGON 2240.400 1551.600  2240.400 1555.000  2239.500 1555.000  2239.500 1605.000  2240.400 1605.000  2240.400 1611.300  2249.600 1611.300  2249.600 1605.000  2250.500 1605.000  2250.500 1555.000  2249.600 1555.000  2249.600 1551.600 ;
            POLYGON 2258.300 1551.600  2258.300 1555.000  2257.300 1555.000  2257.300 1605.000  2256.800 1605.000  2256.800 1611.300  2263.200 1611.300  2263.200 1605.000  2262.700 1605.000  2262.700 1555.000  2261.700 1555.000  2261.700 1551.600 ;
            POLYGON 2270.400 1551.600  2270.400 1555.000  2269.500 1555.000  2269.500 1605.000  2270.400 1605.000  2270.400 1611.300  2279.600 1611.300  2279.600 1605.000  2280.500 1605.000  2280.500 1555.000  2279.600 1555.000  2279.600 1551.600 ;
            POLYGON 2288.300 1551.600  2288.300 1555.000  2287.300 1555.000  2287.300 1605.000  2286.800 1605.000  2286.800 1611.300  2293.200 1611.300  2293.200 1605.000  2292.700 1605.000  2292.700 1555.000  2291.700 1555.000  2291.700 1551.600 ;
            POLYGON 2209.000 1288.700  2209.000 1295.000  2209.500 1295.000  2209.500 1345.000  2209.000 1345.000  2209.000 1348.400  2218.200 1348.400  2218.200 1345.000  2217.700 1345.000  2217.700 1295.000  2218.200 1295.000  2218.200 1288.700 ;
            POLYGON 2226.800 1288.700  2226.800 1295.000  2227.300 1295.000  2227.300 1345.000  2228.300 1345.000  2228.300 1348.400  2231.700 1348.400  2231.700 1345.000  2232.700 1345.000  2232.700 1295.000  2233.200 1295.000  2233.200 1288.700 ;
            POLYGON 291.400 1788.700  291.400 1911.300  300.000 1911.300  300.000 1942.000  116.500 1942.000  116.500 2018.000  143.300 2018.000  143.300 2021.400  277.200 2021.400  277.200 2018.000  308.000 2018.000  308.000 1911.300  319.100 1911.300  319.100 1908.700  309.600 1908.700  309.600 1898.700  317.600 1898.700  317.600 1894.100  309.600 1894.100  309.600 1882.100  305.000 1882.100  305.000 1908.700  293.200 1908.700  293.200 1791.300  305.000 1791.300  305.000 1817.900  309.600 1817.900  309.600 1812.900  307.600 1812.900  307.600 1811.100  315.000 1811.100  315.000 1817.700  317.600 1817.700  317.600 1809.300  307.600 1809.300  307.600 1791.300  319.100 1791.300  319.100 1788.700 ;
            POLYGON 648.300 2170.000  648.300 2177.200  648.700 2177.200  648.700 2192.400  641.600 2192.400  641.600 2183.200  638.000 2183.200  638.000 2182.400  635.400 2182.400  635.400 2185.000  639.800 2185.000  639.800 2192.400  638.000 2192.400  638.000 2190.400  635.400 2190.400  635.400 2192.400  635.100 2192.400  635.100 2195.000  648.700 2195.000  648.700 2200.000  651.300 2200.000  651.300 2195.000  664.900 2195.000  664.900 2192.400  664.600 2192.400  664.600 2190.400  662.000 2190.400  662.000 2192.400  659.800 2192.400  659.800 2182.400  657.200 2182.400  657.200 2192.400  651.300 2192.400  651.300 2177.200  651.700 2177.200  651.700 2170.000 ;
            POLYGON 305.000 1835.100  305.000 1848.700  300.000 1848.700  300.000 1851.300  305.000 1851.300  305.000 1864.900  307.600 1864.900  307.600 1864.600  309.600 1864.600  309.600 1862.000  307.600 1862.000  307.600 1860.200  315.000 1860.200  315.000 1864.600  317.600 1864.600  317.600 1862.000  316.800 1862.000  316.800 1858.400  307.600 1858.400  307.600 1851.300  322.800 1851.300  322.800 1851.700  330.000 1851.700  330.000 1848.300  322.800 1848.300  322.800 1848.700  307.600 1848.700  307.600 1842.800  317.600 1842.800  317.600 1840.200  307.600 1840.200  307.600 1838.000  309.600 1838.000  309.600 1835.400  307.600 1835.400  307.600 1835.100 ;
            POLYGON 718.300 2170.000  718.300 2226.000  688.000 2226.000  688.000 2240.000  572.000 2240.000  572.000 2340.000  728.000 2340.000  728.000 2226.000  721.700 2226.000  721.700 2170.000 ;
            POLYGON 160.000 1772.000  160.000 1928.000  260.000 1928.000  260.000 1812.000  274.000 1812.000  274.000 1781.700  330.000 1781.700  330.000 1778.300  274.000 1778.300  274.000 1772.000 ;
            POLYGON 588.700 2180.900  588.700 2192.000  482.000 2192.000  482.000 2222.800  478.600 2222.800  478.600 2356.700  482.000 2356.700  482.000 2383.500  558.000 2383.500  558.000 2200.000  588.700 2200.000  588.700 2208.600  711.300 2208.600  711.300 2180.900  708.700 2180.900  708.700 2192.400  690.700 2192.400  690.700 2182.400  682.300 2182.400  682.300 2185.000  688.900 2185.000  688.900 2192.400  687.100 2192.400  687.100 2190.400  682.100 2190.400  682.100 2195.000  708.700 2195.000  708.700 2206.800  591.300 2206.800  591.300 2195.000  617.900 2195.000  617.900 2190.400  605.900 2190.400  605.900 2182.400  601.300 2182.400  601.300 2190.400  591.300 2190.400  591.300 2180.900 ;
            POLYGON 1013.100 2178.400  1013.100 2181.000  1044.700 2181.000  1044.700 2186.300  1047.300 2186.300  1047.300 2178.400  1040.200 2178.400  1040.200 2179.200  1018.000 2179.200  1018.000 2178.400 ;
            POLYGON 1062.000 2178.400  1062.000 2181.000  1104.400 2181.000  1104.400 2188.000  1107.000 2188.000  1107.000 2185.400  1106.200 2185.400  1106.200 2178.400  1094.100 2178.400  1094.100 2179.200  1064.600 2179.200  1064.600 2178.400 ;
            POLYGON 662.000 2184.200  662.000 2186.800  662.800 2186.800  662.800 2188.200  672.100 2188.200  672.100 2192.600  671.700 2192.600  671.700 2195.200  674.300 2195.200  674.300 2192.600  673.900 2192.600  673.900 2188.200  682.100 2188.200  682.100 2189.000  687.100 2189.000  687.100 2186.400  664.600 2186.400  664.600 2184.200 ;
            POLYGON 1035.400 2184.200  1035.400 2186.400  1012.900 2186.400  1012.900 2189.000  1017.900 2189.000  1017.900 2188.200  1026.100 2188.200  1026.100 2192.600  1025.700 2192.600  1025.700 2195.200  1028.300 2195.200  1028.300 2192.600  1027.900 2192.600  1027.900 2188.200  1037.200 2188.200  1037.200 2186.800  1038.000 2186.800  1038.000 2184.200 ;
            POLYGON 1082.900 2184.200  1082.900 2185.000  1072.100 2185.000  1072.100 2187.200  1064.600 2187.200  1064.600 2186.400  1062.000 2186.400  1062.000 2189.000  1072.100 2189.000  1072.100 2192.600  1071.700 2192.600  1071.700 2195.200  1074.300 2195.200  1074.300 2192.600  1073.900 2192.600  1073.900 2186.800  1091.500 2186.800  1091.500 2184.200 ;
            POLYGON 668.300 2170.000  668.300 2172.000  656.800 2172.000  656.800 2175.600  668.300 2175.600  668.300 2176.200  671.700 2176.200  671.700 2170.000 ;
            POLYGON 1048.300 2170.000  1048.300 2177.200  1048.700 2177.200  1048.700 2192.400  1042.800 2192.400  1042.800 2182.400  1040.200 2182.400  1040.200 2192.400  1038.000 2192.400  1038.000 2190.400  1035.400 2190.400  1035.400 2192.400  1035.100 2192.400  1035.100 2195.000  1048.700 2195.000  1048.700 2200.000  1051.300 2200.000  1051.300 2195.000  1064.900 2195.000  1064.900 2192.400  1064.600 2192.400  1064.600 2190.400  1062.000 2190.400  1062.000 2192.400  1060.200 2192.400  1060.200 2185.000  1064.600 2185.000  1064.600 2182.400  1062.000 2182.400  1062.000 2183.200  1058.400 2183.200  1058.400 2192.400  1051.300 2192.400  1051.300 2177.200  1051.700 2177.200  1051.700 2170.000 ;
            POLYGON 658.300 2196.400  658.300 2199.000  703.900 2199.000  703.900 2205.400  707.300 2205.400  707.300 2196.400  682.100 2196.400  682.100 2197.200  664.900 2197.200  664.900 2196.400 ;
            POLYGON 992.700 2196.400  992.700 2205.400  996.100 2205.400  996.100 2199.000  1041.700 2199.000  1041.700 2196.400  1035.100 2196.400  1035.100 2197.200  1017.900 2197.200  1017.900 2196.400 ;
            POLYGON 1058.300 2196.400  1058.300 2199.000  1103.900 2199.000  1103.900 2205.400  1107.300 2205.400  1107.300 2196.400  1082.100 2196.400  1082.100 2197.200  1064.900 2197.200  1064.900 2196.400 ;
            POLYGON 751.600 2209.000  751.600 2218.200  755.000 2218.200  755.000 2217.700  805.000 2217.700  805.000 2218.200  811.300 2218.200  811.300 2209.000  805.000 2209.000  805.000 2209.500  755.000 2209.500  755.000 2209.000 ;
            POLYGON 888.700 2209.000  888.700 2218.200  895.000 2218.200  895.000 2217.700  945.000 2217.700  945.000 2218.200  948.400 2218.200  948.400 2209.000  945.000 2209.000  945.000 2209.500  895.000 2209.500  895.000 2209.000 ;
            POLYGON 1151.600 2209.000  1151.600 2218.200  1155.000 2218.200  1155.000 2217.700  1205.000 2217.700  1205.000 2218.200  1211.300 2218.200  1211.300 2209.000  1205.000 2209.000  1205.000 2209.500  1155.000 2209.500  1155.000 2209.000 ;
            POLYGON 805.000 2226.800  805.000 2227.300  755.000 2227.300  755.000 2228.400  751.600 2228.400  751.600 2231.800  755.000 2231.800  755.000 2232.700  805.000 2232.700  805.000 2233.200  811.300 2233.200  811.300 2226.800 ;
            POLYGON 888.700 2226.800  888.700 2233.200  895.000 2233.200  895.000 2232.700  945.000 2232.700  945.000 2231.800  948.400 2231.800  948.400 2228.400  945.000 2228.400  945.000 2227.300  895.000 2227.300  895.000 2226.800 ;
            POLYGON 1205.000 2226.800  1205.000 2227.300  1155.000 2227.300  1155.000 2228.300  1151.600 2228.300  1151.600 2231.700  1155.000 2231.700  1155.000 2232.700  1205.000 2232.700  1205.000 2233.200  1211.300 2233.200  1211.300 2226.800 ;
            POLYGON 755.000 2239.500  755.000 2240.400  751.600 2240.400  751.600 2249.600  755.000 2249.600  755.000 2250.500  805.000 2250.500  805.000 2249.600  811.300 2249.600  811.300 2240.400  805.000 2240.400  805.000 2239.500 ;
            POLYGON 895.000 2239.500  895.000 2240.400  888.700 2240.400  888.700 2249.600  895.000 2249.600  895.000 2250.500  945.000 2250.500  945.000 2249.600  948.400 2249.600  948.400 2240.400  945.000 2240.400  945.000 2239.500 ;
            POLYGON 1155.000 2239.500  1155.000 2240.400  1151.600 2240.400  1151.600 2249.600  1155.000 2249.600  1155.000 2250.500  1205.000 2250.500  1205.000 2249.600  1211.300 2249.600  1211.300 2240.400  1205.000 2240.400  1205.000 2239.500 ;
            POLYGON 748.200 2202.000  748.200 2255.800  753.600 2255.800  753.600 2253.200  750.000 2253.200  750.000 2236.800  753.600 2236.800  753.600 2234.200  750.000 2234.200  750.000 2225.800  753.600 2225.800  753.600 2223.200  750.000 2223.200  750.000 2205.400  753.700 2205.400  753.700 2202.000 ;
            POLYGON 946.300 2202.000  946.300 2205.400  950.000 2205.400  950.000 2223.200  946.400 2223.200  946.400 2225.800  950.000 2225.800  950.000 2234.200  946.400 2234.200  946.400 2236.800  950.000 2236.800  950.000 2253.200  946.400 2253.200  946.400 2255.800  951.800 2255.800  951.800 2202.000 ;
            POLYGON 805.000 2256.800  805.000 2257.300  755.000 2257.300  755.000 2258.300  751.600 2258.300  751.600 2261.700  755.000 2261.700  755.000 2262.700  805.000 2262.700  805.000 2263.200  811.300 2263.200  811.300 2256.800 ;
            POLYGON 888.700 2256.800  888.700 2263.200  895.000 2263.200  895.000 2262.700  945.000 2262.700  945.000 2261.700  948.400 2261.700  948.400 2258.300  945.000 2258.300  945.000 2257.300  895.000 2257.300  895.000 2256.800 ;
            POLYGON 1205.000 2256.800  1205.000 2257.300  1155.000 2257.300  1155.000 2258.300  1151.600 2258.300  1151.600 2261.700  1155.000 2261.700  1155.000 2262.700  1205.000 2262.700  1205.000 2263.200  1211.300 2263.200  1211.300 2256.800 ;
            POLYGON 755.000 2269.500  755.000 2270.400  751.600 2270.400  751.600 2279.600  755.000 2279.600  755.000 2280.500  805.000 2280.500  805.000 2279.600  811.300 2279.600  811.300 2270.400  805.000 2270.400  805.000 2269.500 ;
            POLYGON 895.000 2269.500  895.000 2270.400  888.700 2270.400  888.700 2279.600  895.000 2279.600  895.000 2280.500  945.000 2280.500  945.000 2279.600  948.400 2279.600  948.400 2270.400  945.000 2270.400  945.000 2269.500 ;
            POLYGON 1155.000 2269.500  1155.000 2270.400  1151.600 2270.400  1151.600 2279.600  1155.000 2279.600  1155.000 2280.500  1205.000 2280.500  1205.000 2279.600  1211.300 2279.600  1211.300 2270.400  1205.000 2270.400  1205.000 2269.500 ;
            POLYGON 805.000 2286.800  805.000 2287.300  755.000 2287.300  755.000 2288.300  751.600 2288.300  751.600 2291.700  755.000 2291.700  755.000 2292.700  805.000 2292.700  805.000 2293.200  811.300 2293.200  811.300 2286.800 ;
            POLYGON 888.700 2286.800  888.700 2293.200  895.000 2293.200  895.000 2292.700  945.000 2292.700  945.000 2291.700  948.400 2291.700  948.400 2288.300  945.000 2288.300  945.000 2287.300  895.000 2287.300  895.000 2286.800 ;
            POLYGON 1205.000 2286.800  1205.000 2287.300  1155.000 2287.300  1155.000 2288.300  1151.600 2288.300  1151.600 2291.700  1155.000 2291.700  1155.000 2292.700  1205.000 2292.700  1205.000 2293.200  1211.300 2293.200  1211.300 2286.800 ;
            POLYGON 1146.800 2202.000  1146.800 2296.800  1153.600 2296.800  1153.600 2294.200  1149.400 2294.200  1149.400 2285.800  1153.600 2285.800  1153.600 2283.200  1149.400 2283.200  1149.400 2266.800  1153.600 2266.800  1153.600 2264.200  1149.400 2264.200  1149.400 2255.800  1153.600 2255.800  1153.600 2253.200  1149.400 2253.200  1149.400 2236.800  1153.600 2236.800  1153.600 2234.200  1149.400 2234.200  1149.400 2225.800  1153.600 2225.800  1153.600 2223.200  1149.400 2223.200  1149.400 2205.400  1153.700 2205.400  1153.700 2202.000 ;
            POLYGON 755.000 2299.500  755.000 2300.400  751.600 2300.400  751.600 2309.600  755.000 2309.600  755.000 2310.500  805.000 2310.500  805.000 2309.600  811.300 2309.600  811.300 2300.400  805.000 2300.400  805.000 2299.500 ;
            POLYGON 895.000 2299.500  895.000 2300.400  888.700 2300.400  888.700 2309.600  895.000 2309.600  895.000 2310.500  945.000 2310.500  945.000 2309.600  948.400 2309.600  948.400 2300.400  945.000 2300.400  945.000 2299.500 ;
            POLYGON 1155.000 2299.500  1155.000 2300.400  1151.600 2300.400  1151.600 2309.600  1155.000 2309.600  1155.000 2310.500  1205.000 2310.500  1205.000 2309.600  1211.300 2309.600  1211.300 2300.400  1205.000 2300.400  1205.000 2299.500 ;
            POLYGON 1028.300 2170.000  1028.300 2176.200  1031.700 2176.200  1031.700 2175.600  1043.200 2175.600  1043.200 2172.000  1031.700 2172.000  1031.700 2170.000 ;
            POLYGON 805.000 2316.800  805.000 2317.300  755.000 2317.300  755.000 2318.300  751.600 2318.300  751.600 2321.700  755.000 2321.700  755.000 2322.700  805.000 2322.700  805.000 2323.200  811.300 2323.200  811.300 2316.800 ;
            POLYGON 888.700 2316.800  888.700 2323.200  895.000 2323.200  895.000 2322.700  945.000 2322.700  945.000 2321.700  948.400 2321.700  948.400 2318.300  945.000 2318.300  945.000 2317.300  895.000 2317.300  895.000 2316.800 ;
            POLYGON 1205.000 2316.800  1205.000 2317.300  1155.000 2317.300  1155.000 2318.300  1151.600 2318.300  1151.600 2321.700  1155.000 2321.700  1155.000 2322.700  1205.000 2322.700  1205.000 2323.200  1211.300 2323.200  1211.300 2316.800 ;
            POLYGON 1068.300 2170.000  1068.300 2172.000  1061.400 2172.000  1061.400 2175.600  1068.300 2175.600  1068.300 2176.200  1071.700 2176.200  1071.700 2170.000 ;
            POLYGON 978.300 2170.000  978.300 2226.000  972.000 2226.000  972.000 2340.000  1128.000 2340.000  1128.000 2240.000  1012.000 2240.000  1012.000 2226.000  981.700 2226.000  981.700 2170.000 ;
            POLYGON 755.000 2329.500  755.000 2330.400  751.600 2330.400  751.600 2339.600  755.000 2339.600  755.000 2340.500  805.000 2340.500  805.000 2339.600  811.300 2339.600  811.300 2330.400  805.000 2330.400  805.000 2329.500 ;
            POLYGON 895.000 2329.500  895.000 2330.400  888.700 2330.400  888.700 2339.600  895.000 2339.600  895.000 2340.500  945.000 2340.500  945.000 2339.600  948.400 2339.600  948.400 2330.400  945.000 2330.400  945.000 2329.500 ;
            POLYGON 1155.000 2329.500  1155.000 2330.400  1151.600 2330.400  1151.600 2339.600  1155.000 2339.600  1155.000 2340.500  1205.000 2340.500  1205.000 2339.600  1211.300 2339.600  1211.300 2330.400  1205.000 2330.400  1205.000 2329.500 ;
            POLYGON 1053.700 2178.400  1053.700 2181.000  1056.300 2181.000  1056.300 2178.400 ;
            POLYGON 805.000 2346.800  805.000 2347.300  755.000 2347.300  755.000 2348.300  751.600 2348.300  751.600 2351.700  755.000 2351.700  755.000 2352.700  805.000 2352.700  805.000 2353.200  811.300 2353.200  811.300 2346.800 ;
            POLYGON 888.700 2346.800  888.700 2353.200  895.000 2353.200  895.000 2352.700  945.000 2352.700  945.000 2351.700  948.400 2351.700  948.400 2348.300  945.000 2348.300  945.000 2347.300  895.000 2347.300  895.000 2346.800 ;
            POLYGON 1205.000 2346.800  1205.000 2347.300  1155.000 2347.300  1155.000 2348.200  1151.600 2348.200  1151.600 2351.600  1155.000 2351.600  1155.000 2352.700  1205.000 2352.700  1205.000 2353.200  1211.300 2353.200  1211.300 2346.800 ;
            POLYGON 751.600 2361.800  751.600 2371.000  755.000 2371.000  755.000 2370.500  805.000 2370.500  805.000 2371.000  811.300 2371.000  811.300 2361.800  805.000 2361.800  805.000 2362.300  755.000 2362.300  755.000 2361.800 ;
            POLYGON 888.700 2361.800  888.700 2371.000  895.000 2371.000  895.000 2370.500  945.000 2370.500  945.000 2371.000  948.400 2371.000  948.400 2361.800  945.000 2361.800  945.000 2362.300  895.000 2362.300  895.000 2361.800 ;
            POLYGON 1151.600 2361.800  1151.600 2371.000  1155.000 2371.000  1155.000 2370.500  1205.000 2370.500  1205.000 2371.000  1211.300 2371.000  1211.300 2361.800  1205.000 2361.800  1205.000 2362.300  1155.000 2362.300  1155.000 2361.800 ;
            POLYGON 652.700 2178.400  652.700 2186.300  655.300 2186.300  655.300 2181.000  686.900 2181.000  686.900 2178.400  682.000 2178.400  682.000 2179.200  659.800 2179.200  659.800 2178.400 ;
            POLYGON 742.000 2196.500  742.000 2383.500  818.000 2383.500  818.000 2357.000  821.400 2357.000  821.400 2223.100  818.000 2223.100  818.000 2196.500 ;
            POLYGON 882.000 2196.500  882.000 2223.100  878.600 2223.100  878.600 2357.000  882.000 2357.000  882.000 2383.500  958.000 2383.500  958.000 2196.500 ;
            POLYGON 988.700 2180.900  988.700 2208.600  1111.300 2208.600  1111.300 2200.000  1142.000 2200.000  1142.000 2383.500  1218.000 2383.500  1218.000 2356.700  1221.400 2356.700  1221.400 2222.800  1218.000 2222.800  1218.000 2192.000  1111.300 2192.000  1111.300 2180.900  1108.700 2180.900  1108.700 2190.400  1098.700 2190.400  1098.700 2182.400  1094.100 2182.400  1094.100 2190.400  1082.100 2190.400  1082.100 2195.000  1108.700 2195.000  1108.700 2206.800  991.300 2206.800  991.300 2195.000  1017.900 2195.000  1017.900 2190.400  1012.900 2190.400  1012.900 2192.400  1011.100 2192.400  1011.100 2185.000  1017.700 2185.000  1017.700 2182.400  1009.300 2182.400  1009.300 2192.400  991.300 2192.400  991.300 2180.900 ;
            POLYGON 311.000 1862.000  311.000 1872.100  307.400 1872.100  307.400 1871.700  304.800 1871.700  304.800 1874.300  307.400 1874.300  307.400 1873.900  313.200 1873.900  313.200 1891.500  315.800 1891.500  315.800 1882.900  315.000 1882.900  315.000 1872.100  312.800 1872.100  312.800 1864.600  313.600 1864.600  313.600 1862.000 ;
            POLYGON 319.000 1862.000  319.000 1904.400  312.000 1904.400  312.000 1907.000  314.600 1907.000  314.600 1906.200  321.600 1906.200  321.600 1894.100  320.800 1894.100  320.800 1864.600  321.600 1864.600  321.600 1862.000 ;
            POLYGON 488.700 2226.800  488.700 2233.200  495.000 2233.200  495.000 2232.700  545.000 2232.700  545.000 2231.700  548.400 2231.700  548.400 2228.300  545.000 2228.300  545.000 2227.300  495.000 2227.300  495.000 2226.800 ;
            POLYGON 643.700 2178.400  643.700 2181.000  646.300 2181.000  646.300 2178.400 ;
            POLYGON 301.000 1858.300  301.000 1903.900  294.600 1903.900  294.600 1907.300  303.600 1907.300  303.600 1882.100  302.800 1882.100  302.800 1864.900  303.600 1864.900  303.600 1858.300 ;
            POLYGON 495.000 2329.500  495.000 2330.400  488.700 2330.400  488.700 2339.600  495.000 2339.600  495.000 2340.500  545.000 2340.500  545.000 2339.600  548.400 2339.600  548.400 2330.400  545.000 2330.400  545.000 2329.500 ;
            POLYGON 488.700 2256.800  488.700 2263.200  495.000 2263.200  495.000 2262.700  545.000 2262.700  545.000 2261.700  548.400 2261.700  548.400 2258.300  545.000 2258.300  545.000 2257.300  495.000 2257.300  495.000 2256.800 ;
            POLYGON 319.000 1853.700  319.000 1856.300  321.600 1856.300  321.600 1853.700 ;
            POLYGON 546.300 2202.000  546.300 2205.400  550.600 2205.400  550.600 2223.200  546.400 2223.200  546.400 2225.800  550.600 2225.800  550.600 2234.200  546.400 2234.200  546.400 2236.800  550.600 2236.800  550.600 2253.200  546.400 2253.200  546.400 2255.800  550.600 2255.800  550.600 2264.200  546.400 2264.200  546.400 2266.800  550.600 2266.800  550.600 2283.200  546.400 2283.200  546.400 2285.800  550.600 2285.800  550.600 2294.200  546.400 2294.200  546.400 2296.800  553.200 2296.800  553.200 2202.000 ;
            POLYGON 608.500 2184.200  608.500 2186.800  626.100 2186.800  626.100 2192.600  625.700 2192.600  625.700 2195.200  628.300 2195.200  628.300 2192.600  627.900 2192.600  627.900 2189.000  638.000 2189.000  638.000 2186.400  635.400 2186.400  635.400 2187.200  627.900 2187.200  627.900 2185.000  617.100 2185.000  617.100 2184.200 ;
            POLYGON 203.200 1946.800  203.200 1953.600  205.800 1953.600  205.800 1949.400  214.200 1949.400  214.200 1953.600  216.800 1953.600  216.800 1949.400  233.200 1949.400  233.200 1953.600  235.800 1953.600  235.800 1949.400  244.200 1949.400  244.200 1953.600  246.800 1953.600  246.800 1949.400  263.200 1949.400  263.200 1953.600  265.800 1953.600  265.800 1949.400  274.200 1949.400  274.200 1953.600  276.800 1953.600  276.800 1949.400  294.600 1949.400  294.600 1953.700  298.000 1953.700  298.000 1946.800 ;
            POLYGON 488.700 2346.800  488.700 2353.200  495.000 2353.200  495.000 2352.700  545.000 2352.700  545.000 2351.600  548.400 2351.600  548.400 2348.200  545.000 2348.200  545.000 2347.300  495.000 2347.300  495.000 2346.800 ;
            POLYGON 495.000 2299.500  495.000 2300.400  488.700 2300.400  488.700 2309.600  495.000 2309.600  495.000 2310.500  545.000 2310.500  545.000 2309.600  548.400 2309.600  548.400 2300.400  545.000 2300.400  545.000 2299.500 ;
            POLYGON 488.700 2209.000  488.700 2218.200  495.000 2218.200  495.000 2217.700  545.000 2217.700  545.000 2218.200  548.400 2218.200  548.400 2209.000  545.000 2209.000  545.000 2209.500  495.000 2209.500  495.000 2209.000 ;
            POLYGON 495.000 2239.500  495.000 2240.400  488.700 2240.400  488.700 2249.600  495.000 2249.600  495.000 2250.500  545.000 2250.500  545.000 2249.600  548.400 2249.600  548.400 2240.400  545.000 2240.400  545.000 2239.500 ;
            POLYGON 129.000 1951.600  129.000 1955.000  129.500 1955.000  129.500 2005.000  129.000 2005.000  129.000 2011.300  138.200 2011.300  138.200 2005.000  137.700 2005.000  137.700 1955.000  138.200 1955.000  138.200 1951.600 ;
            POLYGON 148.400 1951.600  148.400 1955.000  147.300 1955.000  147.300 2005.000  146.800 2005.000  146.800 2011.300  153.200 2011.300  153.200 2005.000  152.700 2005.000  152.700 1955.000  151.800 1955.000  151.800 1951.600 ;
            POLYGON 160.400 1951.600  160.400 1955.000  159.500 1955.000  159.500 2005.000  160.400 2005.000  160.400 2011.300  169.600 2011.300  169.600 2005.000  170.500 2005.000  170.500 1955.000  169.600 1955.000  169.600 1951.600 ;
            POLYGON 488.700 2361.800  488.700 2371.000  495.000 2371.000  495.000 2370.500  545.000 2370.500  545.000 2371.000  548.400 2371.000  548.400 2361.800  545.000 2361.800  545.000 2362.300  495.000 2362.300  495.000 2361.800 ;
            POLYGON 495.000 2269.500  495.000 2270.400  488.700 2270.400  488.700 2279.600  495.000 2279.600  495.000 2280.500  545.000 2280.500  545.000 2279.600  548.400 2279.600  548.400 2270.400  545.000 2270.400  545.000 2269.500 ;
            POLYGON 628.300 2170.000  628.300 2176.200  631.700 2176.200  631.700 2175.600  638.600 2175.600  638.600 2172.000  631.700 2172.000  631.700 2170.000 ;
            POLYGON 324.400 1861.400  324.400 1868.300  323.800 1868.300  323.800 1871.700  330.000 1871.700  330.000 1868.300  328.000 1868.300  328.000 1861.400 ;
            POLYGON 178.300 1951.600  178.300 1955.000  177.300 1955.000  177.300 2005.000  176.800 2005.000  176.800 2011.300  183.200 2011.300  183.200 2005.000  182.700 2005.000  182.700 1955.000  181.700 1955.000  181.700 1951.600 ;
            POLYGON 190.400 1951.600  190.400 1955.000  189.500 1955.000  189.500 2005.000  190.400 2005.000  190.400 2011.300  199.600 2011.300  199.600 2005.000  200.500 2005.000  200.500 1955.000  199.600 1955.000  199.600 1951.600 ;
            POLYGON 208.300 1951.600  208.300 1955.000  207.300 1955.000  207.300 2005.000  206.800 2005.000  206.800 2011.300  213.200 2011.300  213.200 2005.000  212.700 2005.000  212.700 1955.000  211.700 1955.000  211.700 1951.600 ;
            POLYGON 220.400 1951.600  220.400 1955.000  219.500 1955.000  219.500 2005.000  220.400 2005.000  220.400 2011.300  229.600 2011.300  229.600 2005.000  230.500 2005.000  230.500 1955.000  229.600 1955.000  229.600 1951.600 ;
            POLYGON 488.700 2316.800  488.700 2323.200  495.000 2323.200  495.000 2322.700  545.000 2322.700  545.000 2321.700  548.400 2321.700  548.400 2318.300  545.000 2318.300  545.000 2317.300  495.000 2317.300  495.000 2316.800 ;
            POLYGON 592.700 2196.400  592.700 2205.400  596.100 2205.400  596.100 2199.000  641.700 2199.000  641.700 2196.400  635.100 2196.400  635.100 2197.200  617.900 2197.200  617.900 2196.400 ;
            POLYGON 593.800 2178.400  593.800 2185.400  593.000 2185.400  593.000 2188.000  595.600 2188.000  595.600 2181.000  638.000 2181.000  638.000 2178.400  635.400 2178.400  635.400 2179.200  605.900 2179.200  605.900 2178.400 ;
            POLYGON 488.700 2286.800  488.700 2293.200  495.000 2293.200  495.000 2292.700  545.000 2292.700  545.000 2291.700  548.400 2291.700  548.400 2288.300  545.000 2288.300  545.000 2287.300  495.000 2287.300  495.000 2286.800 ;
            POLYGON 238.300 1951.600  238.300 1955.000  237.300 1955.000  237.300 2005.000  236.800 2005.000  236.800 2011.300  243.200 2011.300  243.200 2005.000  242.700 2005.000  242.700 1955.000  241.700 1955.000  241.700 1951.600 ;
            POLYGON 250.400 1951.600  250.400 1955.000  249.500 1955.000  249.500 2005.000  250.400 2005.000  250.400 2011.300  259.600 2011.300  259.600 2005.000  260.500 2005.000  260.500 1955.000  259.600 1955.000  259.600 1951.600 ;
            POLYGON 268.300 1951.600  268.300 1955.000  267.300 1955.000  267.300 2005.000  266.800 2005.000  266.800 2011.300  273.200 2011.300  273.200 2005.000  272.700 2005.000  272.700 1955.000  271.700 1955.000  271.700 1951.600 ;
            POLYGON 281.800 1951.600  281.800 1955.000  282.300 1955.000  282.300 2005.000  281.800 2005.000  281.800 2011.300  291.000 2011.300  291.000 2005.000  290.500 2005.000  290.500 1955.000  291.000 1955.000  291.000 1951.600 ;
            POLYGON 190.400 1551.600  190.400 1555.000  189.500 1555.000  189.500 1605.000  190.400 1605.000  190.400 1611.300  199.600 1611.300  199.600 1605.000  200.500 1605.000  200.500 1555.000  199.600 1555.000  199.600 1551.600 ;
            POLYGON 176.800 1288.700  176.800 1295.000  177.300 1295.000  177.300 1345.000  178.300 1345.000  178.300 1348.400  181.700 1348.400  181.700 1345.000  182.700 1345.000  182.700 1295.000  183.200 1295.000  183.200 1288.700 ;
            POLYGON 294.600 1392.700  294.600 1396.100  301.000 1396.100  301.000 1441.700  303.600 1441.700  303.600 1435.100  302.800 1435.100  302.800 1417.900  303.600 1417.900  303.600 1392.700 ;
            POLYGON 190.400 1288.700  190.400 1295.000  189.500 1295.000  189.500 1345.000  190.400 1345.000  190.400 1348.400  199.600 1348.400  199.600 1345.000  200.500 1345.000  200.500 1295.000  199.600 1295.000  199.600 1288.700 ;
            POLYGON 313.200 1462.000  313.200 1462.800  311.800 1462.800  311.800 1472.100  307.400 1472.100  307.400 1471.700  304.800 1471.700  304.800 1474.300  307.400 1474.300  307.400 1473.900  311.800 1473.900  311.800 1482.100  311.000 1482.100  311.000 1487.100  313.600 1487.100  313.600 1464.600  315.800 1464.600  315.800 1462.000 ;
            POLYGON 266.800 1288.700  266.800 1295.000  267.300 1295.000  267.300 1345.000  268.300 1345.000  268.300 1348.400  271.700 1348.400  271.700 1345.000  272.700 1345.000  272.700 1295.000  273.200 1295.000  273.200 1288.700 ;
            POLYGON 208.300 1551.600  208.300 1555.000  207.300 1555.000  207.300 1605.000  206.800 1605.000  206.800 1611.300  213.200 1611.300  213.200 1605.000  212.700 1605.000  212.700 1555.000  211.700 1555.000  211.700 1551.600 ;
            POLYGON 301.000 1458.300  301.000 1503.900  294.600 1503.900  294.600 1507.300  303.600 1507.300  303.600 1482.100  302.800 1482.100  302.800 1464.900  303.600 1464.900  303.600 1458.300 ;
            POLYGON 220.400 1551.600  220.400 1555.000  219.500 1555.000  219.500 1605.000  220.400 1605.000  220.400 1611.300  229.600 1611.300  229.600 1605.000  230.500 1605.000  230.500 1555.000  229.600 1555.000  229.600 1551.600 ;
            POLYGON 281.800 1288.700  281.800 1295.000  282.300 1295.000  282.300 1345.000  281.800 1345.000  281.800 1348.400  291.000 1348.400  291.000 1345.000  290.500 1345.000  290.500 1295.000  291.000 1295.000  291.000 1288.700 ;
            POLYGON 319.000 1443.700  319.000 1446.300  321.600 1446.300  321.600 1443.700 ;
            POLYGON 206.800 1688.700  206.800 1695.000  207.300 1695.000  207.300 1745.000  208.300 1745.000  208.300 1748.400  211.700 1748.400  211.700 1745.000  212.700 1745.000  212.700 1695.000  213.200 1695.000  213.200 1688.700 ;
            POLYGON 220.400 1688.700  220.400 1695.000  219.500 1695.000  219.500 1745.000  220.400 1745.000  220.400 1748.400  229.600 1748.400  229.600 1745.000  230.500 1745.000  230.500 1695.000  229.600 1695.000  229.600 1688.700 ;
            POLYGON 129.000 1688.700  129.000 1695.000  129.500 1695.000  129.500 1745.000  129.000 1745.000  129.000 1748.400  138.200 1748.400  138.200 1745.000  137.700 1745.000  137.700 1695.000  138.200 1695.000  138.200 1688.700 ;
            POLYGON 238.300 1551.600  238.300 1555.000  237.300 1555.000  237.300 1605.000  236.800 1605.000  236.800 1611.300  243.200 1611.300  243.200 1605.000  242.700 1605.000  242.700 1555.000  241.700 1555.000  241.700 1551.600 ;
            POLYGON 143.300 1278.600  143.300 1282.000  116.500 1282.000  116.500 1358.000  300.000 1358.000  300.000 1388.700  291.400 1388.700  291.400 1511.300  319.100 1511.300  319.100 1508.700  307.600 1508.700  307.600 1490.700  317.600 1490.700  317.600 1482.300  315.000 1482.300  315.000 1488.900  307.600 1488.900  307.600 1487.100  309.600 1487.100  309.600 1482.100  305.000 1482.100  305.000 1508.700  293.200 1508.700  293.200 1391.300  305.000 1391.300  305.000 1417.900  309.600 1417.900  309.600 1405.900  317.600 1405.900  317.600 1401.300  309.600 1401.300  309.600 1391.300  319.100 1391.300  319.100 1388.700  308.000 1388.700  308.000 1282.000  277.200 1282.000  277.200 1278.600 ;
            POLYGON 250.400 1551.600  250.400 1555.000  249.500 1555.000  249.500 1605.000  250.400 1605.000  250.400 1611.300  259.600 1611.300  259.600 1605.000  260.500 1605.000  260.500 1555.000  259.600 1555.000  259.600 1551.600 ;
            POLYGON 294.600 1346.300  294.600 1350.600  276.800 1350.600  276.800 1346.400  274.200 1346.400  274.200 1350.600  265.800 1350.600  265.800 1346.400  263.200 1346.400  263.200 1350.600  246.800 1350.600  246.800 1346.400  244.200 1346.400  244.200 1350.600  235.800 1350.600  235.800 1346.400  233.200 1346.400  233.200 1350.600  216.800 1350.600  216.800 1346.400  214.200 1346.400  214.200 1350.600  205.800 1350.600  205.800 1346.400  203.200 1346.400  203.200 1353.200  298.000 1353.200  298.000 1346.300 ;
            POLYGON 160.000 1372.000  160.000 1528.000  274.000 1528.000  274.000 1521.700  330.000 1521.700  330.000 1518.300  274.000 1518.300  274.000 1488.000  260.000 1488.000  260.000 1372.000 ;
            POLYGON 129.000 1288.700  129.000 1295.000  129.500 1295.000  129.500 1345.000  129.000 1345.000  129.000 1348.400  138.200 1348.400  138.200 1345.000  137.700 1345.000  137.700 1295.000  138.200 1295.000  138.200 1288.700 ;
            POLYGON 146.800 1688.700  146.800 1695.000  147.300 1695.000  147.300 1745.000  148.300 1745.000  148.300 1748.400  151.700 1748.400  151.700 1745.000  152.700 1745.000  152.700 1695.000  153.200 1695.000  153.200 1688.700 ;
            POLYGON 236.800 1688.700  236.800 1695.000  237.300 1695.000  237.300 1745.000  238.300 1745.000  238.300 1748.400  241.700 1748.400  241.700 1745.000  242.700 1745.000  242.700 1695.000  243.200 1695.000  243.200 1688.700 ;
            POLYGON 294.600 1746.300  294.600 1750.000  276.800 1750.000  276.800 1746.400  274.200 1746.400  274.200 1750.000  265.800 1750.000  265.800 1746.400  263.200 1746.400  263.200 1750.000  246.800 1750.000  246.800 1746.400  244.200 1746.400  244.200 1751.800  298.000 1751.800  298.000 1746.300 ;
            POLYGON 206.800 1288.700  206.800 1295.000  207.300 1295.000  207.300 1345.000  208.300 1345.000  208.300 1348.400  211.700 1348.400  211.700 1345.000  212.700 1345.000  212.700 1295.000  213.200 1295.000  213.200 1288.700 ;
            POLYGON 268.200 1551.600  268.200 1555.000  267.300 1555.000  267.300 1605.000  266.800 1605.000  266.800 1611.300  273.200 1611.300  273.200 1605.000  272.700 1605.000  272.700 1555.000  271.600 1555.000  271.600 1551.600 ;
            POLYGON 305.000 1435.100  305.000 1448.700  300.000 1448.700  300.000 1451.300  305.000 1451.300  305.000 1464.900  307.600 1464.900  307.600 1464.600  309.600 1464.600  309.600 1462.000  307.600 1462.000  307.600 1459.800  317.600 1459.800  317.600 1457.200  307.600 1457.200  307.600 1451.300  322.800 1451.300  322.800 1451.700  330.000 1451.700  330.000 1448.300  322.800 1448.300  322.800 1448.700  307.600 1448.700  307.600 1441.600  316.800 1441.600  316.800 1438.000  317.600 1438.000  317.600 1435.400  315.000 1435.400  315.000 1439.800  307.600 1439.800  307.600 1438.000  309.600 1438.000  309.600 1435.400  307.600 1435.400  307.600 1435.100 ;
            POLYGON 281.800 1551.600  281.800 1555.000  282.300 1555.000  282.300 1605.000  281.800 1605.000  281.800 1611.300  291.000 1611.300  291.000 1605.000  290.500 1605.000  290.500 1555.000  291.000 1555.000  291.000 1551.600 ;
            POLYGON 160.400 1688.700  160.400 1695.000  159.500 1695.000  159.500 1745.000  160.400 1745.000  160.400 1748.400  169.600 1748.400  169.600 1745.000  170.500 1745.000  170.500 1695.000  169.600 1695.000  169.600 1688.700 ;
            POLYGON 220.400 1288.700  220.400 1295.000  219.500 1295.000  219.500 1345.000  220.400 1345.000  220.400 1348.400  229.600 1348.400  229.600 1345.000  230.500 1345.000  230.500 1295.000  229.600 1295.000  229.600 1288.700 ;
            POLYGON 244.200 1548.200  244.200 1553.600  246.800 1553.600  246.800 1550.000  263.200 1550.000  263.200 1553.600  265.800 1553.600  265.800 1550.000  274.200 1550.000  274.200 1553.600  276.800 1553.600  276.800 1550.000  294.600 1550.000  294.600 1553.700  298.000 1553.700  298.000 1548.200 ;
            POLYGON 143.000 1678.600  143.000 1682.000  116.500 1682.000  116.500 1758.000  303.500 1758.000  303.500 1682.000  276.900 1682.000  276.900 1678.600 ;
            POLYGON 313.200 1408.500  313.200 1426.100  307.400 1426.100  307.400 1425.700  304.800 1425.700  304.800 1428.300  307.400 1428.300  307.400 1427.900  311.000 1427.900  311.000 1438.000  313.600 1438.000  313.600 1435.400  312.800 1435.400  312.800 1427.900  315.000 1427.900  315.000 1417.100  315.800 1417.100  315.800 1408.500 ;
            POLYGON 312.000 1393.000  312.000 1395.600  319.000 1395.600  319.000 1438.000  321.600 1438.000  321.600 1435.400  320.800 1435.400  320.800 1405.900  321.600 1405.900  321.600 1393.800  314.600 1393.800  314.600 1393.000 ;
            POLYGON 311.000 1812.900  311.000 1817.900  311.800 1817.900  311.800 1826.100  307.400 1826.100  307.400 1825.700  304.800 1825.700  304.800 1828.300  307.400 1828.300  307.400 1827.900  311.800 1827.900  311.800 1837.200  313.200 1837.200  313.200 1838.000  315.800 1838.000  315.800 1835.400  313.600 1835.400  313.600 1812.900 ;
            POLYGON 250.400 1688.700  250.400 1695.000  249.500 1695.000  249.500 1745.000  250.400 1745.000  250.400 1748.400  259.600 1748.400  259.600 1745.000  260.500 1745.000  260.500 1695.000  259.600 1695.000  259.600 1688.700 ;
            POLYGON 266.800 1688.700  266.800 1695.000  267.300 1695.000  267.300 1745.000  268.200 1745.000  268.200 1748.400  271.600 1748.400  271.600 1745.000  272.700 1745.000  272.700 1695.000  273.200 1695.000  273.200 1688.700 ;
            POLYGON 116.500 1542.000  116.500 1618.000  143.000 1618.000  143.000 1621.400  276.900 1621.400  276.900 1618.000  303.500 1618.000  303.500 1542.000 ;
            POLYGON 176.800 1688.700  176.800 1695.000  177.300 1695.000  177.300 1745.000  178.300 1745.000  178.300 1748.400  181.700 1748.400  181.700 1745.000  182.700 1745.000  182.700 1695.000  183.200 1695.000  183.200 1688.700 ;
            POLYGON 129.000 1551.600  129.000 1555.000  129.500 1555.000  129.500 1605.000  129.000 1605.000  129.000 1611.300  138.200 1611.300  138.200 1605.000  137.700 1605.000  137.700 1555.000  138.200 1555.000  138.200 1551.600 ;
            POLYGON 294.600 1792.700  294.600 1796.100  301.000 1796.100  301.000 1841.700  303.600 1841.700  303.600 1835.100  302.800 1835.100  302.800 1817.900  303.600 1817.900  303.600 1792.700 ;
            POLYGON 148.300 1551.600  148.300 1555.000  147.300 1555.000  147.300 1605.000  146.800 1605.000  146.800 1611.300  153.200 1611.300  153.200 1605.000  152.700 1605.000  152.700 1555.000  151.700 1555.000  151.700 1551.600 ;
            POLYGON 323.800 1828.300  323.800 1831.700  324.400 1831.700  324.400 1843.200  328.000 1843.200  328.000 1831.700  330.000 1831.700  330.000 1828.300 ;
            POLYGON 323.800 1428.300  323.800 1431.700  324.400 1431.700  324.400 1438.600  328.000 1438.600  328.000 1431.700  330.000 1431.700  330.000 1428.300 ;
            POLYGON 324.400 1456.800  324.400 1468.300  323.800 1468.300  323.800 1471.700  330.000 1471.700  330.000 1468.300  328.000 1468.300  328.000 1456.800 ;
            POLYGON 281.800 1688.700  281.800 1695.000  282.300 1695.000  282.300 1745.000  281.800 1745.000  281.800 1748.400  291.000 1748.400  291.000 1745.000  290.500 1745.000  290.500 1695.000  291.000 1695.000  291.000 1688.700 ;
            POLYGON 236.800 1288.700  236.800 1295.000  237.300 1295.000  237.300 1345.000  238.300 1345.000  238.300 1348.400  241.700 1348.400  241.700 1345.000  242.700 1345.000  242.700 1295.000  243.200 1295.000  243.200 1288.700 ;
            POLYGON 160.400 1551.600  160.400 1555.000  159.500 1555.000  159.500 1605.000  160.400 1605.000  160.400 1611.300  169.600 1611.300  169.600 1605.000  170.500 1605.000  170.500 1555.000  169.600 1555.000  169.600 1551.600 ;
            POLYGON 319.000 1813.100  319.000 1844.700  313.700 1844.700  313.700 1847.300  321.600 1847.300  321.600 1840.200  320.800 1840.200  320.800 1818.000  321.600 1818.000  321.600 1813.100 ;
            POLYGON 178.300 1551.600  178.300 1555.000  177.300 1555.000  177.300 1605.000  176.800 1605.000  176.800 1611.300  183.200 1611.300  183.200 1605.000  182.700 1605.000  182.700 1555.000  181.700 1555.000  181.700 1551.600 ;
            POLYGON 313.700 1452.700  313.700 1455.300  319.000 1455.300  319.000 1486.900  321.600 1486.900  321.600 1482.000  320.800 1482.000  320.800 1459.800  321.600 1459.800  321.600 1452.700 ;
            POLYGON 250.400 1288.700  250.400 1295.000  249.500 1295.000  249.500 1345.000  250.400 1345.000  250.400 1348.400  259.600 1348.400  259.600 1345.000  260.500 1345.000  260.500 1295.000  259.600 1295.000  259.600 1288.700 ;
            POLYGON 190.400 1688.700  190.400 1695.000  189.500 1695.000  189.500 1745.000  190.400 1745.000  190.400 1748.400  199.600 1748.400  199.600 1745.000  200.500 1745.000  200.500 1695.000  199.600 1695.000  199.600 1688.700 ;
            POLYGON 146.800 1288.700  146.800 1295.000  147.300 1295.000  147.300 1345.000  148.400 1345.000  148.400 1348.400  151.800 1348.400  151.800 1345.000  152.700 1345.000  152.700 1295.000  153.200 1295.000  153.200 1288.700 ;
            POLYGON 160.400 1288.700  160.400 1295.000  159.500 1295.000  159.500 1345.000  160.400 1345.000  160.400 1348.400  169.600 1348.400  169.600 1345.000  170.500 1345.000  170.500 1295.000  169.600 1295.000  169.600 1288.700 ;
            POLYGON 482.000 116.500  482.000 143.300  478.600 143.300  478.600 277.200  482.000 277.200  482.000 308.000  588.700 308.000  588.700 319.100  591.300 319.100  591.300 309.600  601.300 309.600  601.300 317.600  605.900 317.600  605.900 309.600  617.900 309.600  617.900 305.000  591.300 305.000  591.300 293.200  708.700 293.200  708.700 305.000  682.100 305.000  682.100 309.600  687.100 309.600  687.100 307.600  688.900 307.600  688.900 315.000  682.300 315.000  682.300 317.600  690.700 317.600  690.700 307.600  708.700 307.600  708.700 319.100  711.300 319.100  711.300 291.400  588.700 291.400  588.700 300.000  558.000 300.000  558.000 116.500 ;
            POLYGON 648.700 300.000  648.700 305.000  635.100 305.000  635.100 307.600  635.400 307.600  635.400 309.600  638.000 309.600  638.000 307.600  639.800 307.600  639.800 315.000  635.400 315.000  635.400 317.600  638.000 317.600  638.000 316.800  641.600 316.800  641.600 307.600  648.700 307.600  648.700 322.800  648.300 322.800  648.300 330.000  651.700 330.000  651.700 322.800  651.300 322.800  651.300 307.600  657.200 307.600  657.200 317.600  659.800 317.600  659.800 307.600  662.000 307.600  662.000 309.600  664.600 309.600  664.600 307.600  664.900 307.600  664.900 305.000  651.300 305.000  651.300 300.000 ;
            POLYGON 572.000 160.000  572.000 260.000  688.000 260.000  688.000 274.000  718.300 274.000  718.300 330.000  721.700 330.000  721.700 274.000  728.000 274.000  728.000 160.000 ;
            POLYGON 305.000 635.100  305.000 648.700  300.000 648.700  300.000 651.300  305.000 651.300  305.000 664.900  307.600 664.900  307.600 664.600  309.600 664.600  309.600 662.000  307.600 662.000  307.600 659.800  317.600 659.800  317.600 657.200  307.600 657.200  307.600 651.300  322.800 651.300  322.800 651.700  330.000 651.700  330.000 648.300  322.800 648.300  322.800 648.700  307.600 648.700  307.600 641.600  316.800 641.600  316.800 638.000  317.600 638.000  317.600 635.400  315.000 635.400  315.000 639.800  307.600 639.800  307.600 638.000  309.600 638.000  309.600 635.400  307.600 635.400  307.600 635.100 ;
            POLYGON 143.300 478.600  143.300 482.000  116.500 482.000  116.500 558.000  300.000 558.000  300.000 588.700  291.400 588.700  291.400 711.300  319.100 711.300  319.100 708.700  307.600 708.700  307.600 690.700  317.600 690.700  317.600 682.300  315.000 682.300  315.000 688.900  307.600 688.900  307.600 687.100  309.600 687.100  309.600 682.100  305.000 682.100  305.000 708.700  293.200 708.700  293.200 591.300  305.000 591.300  305.000 617.900  309.600 617.900  309.600 605.900  317.600 605.900  317.600 601.300  309.600 601.300  309.600 591.300  319.100 591.300  319.100 588.700  308.000 588.700  308.000 482.000  277.200 482.000  277.200 478.600 ;
            POLYGON 160.000 572.000  160.000 728.000  274.000 728.000  274.000 721.700  330.000 721.700  330.000 718.300  274.000 718.300  274.000 688.000  260.000 688.000  260.000 572.000 ;
            POLYGON 313.200 662.000  313.200 662.800  311.800 662.800  311.800 672.100  307.400 672.100  307.400 671.700  304.800 671.700  304.800 674.300  307.400 674.300  307.400 673.900  311.800 673.900  311.800 682.100  311.000 682.100  311.000 687.100  313.600 687.100  313.600 664.600  315.800 664.600  315.800 662.000 ;
            POLYGON 301.000 658.300  301.000 703.900  294.600 703.900  294.600 707.300  303.600 707.300  303.600 682.100  302.800 682.100  302.800 664.900  303.600 664.900  303.600 658.300 ;
            POLYGON 324.400 656.800  324.400 668.300  323.800 668.300  323.800 671.700  330.000 671.700  330.000 668.300  328.000 668.300  328.000 656.800 ;
            POLYGON 313.700 652.700  313.700 655.300  319.000 655.300  319.000 686.900  321.600 686.900  321.600 682.000  320.800 682.000  320.800 659.800  321.600 659.800  321.600 652.700 ;
            POLYGON 244.200 748.200  244.200 753.600  246.800 753.600  246.800 750.000  263.200 750.000  263.200 753.600  265.800 753.600  265.800 750.000  274.200 750.000  274.200 753.600  276.800 753.600  276.800 750.000  294.600 750.000  294.600 753.700  298.000 753.700  298.000 748.200 ;
            POLYGON 129.000 751.600  129.000 755.000  129.500 755.000  129.500 805.000  129.000 805.000  129.000 811.300  138.200 811.300  138.200 805.000  137.700 805.000  137.700 755.000  138.200 755.000  138.200 751.600 ;
            POLYGON 148.300 751.600  148.300 755.000  147.300 755.000  147.300 805.000  146.800 805.000  146.800 811.300  153.200 811.300  153.200 805.000  152.700 805.000  152.700 755.000  151.700 755.000  151.700 751.600 ;
            POLYGON 160.400 751.600  160.400 755.000  159.500 755.000  159.500 805.000  160.400 805.000  160.400 811.300  169.600 811.300  169.600 805.000  170.500 805.000  170.500 755.000  169.600 755.000  169.600 751.600 ;
            POLYGON 178.300 751.600  178.300 755.000  177.300 755.000  177.300 805.000  176.800 805.000  176.800 811.300  183.200 811.300  183.200 805.000  182.700 805.000  182.700 755.000  181.700 755.000  181.700 751.600 ;
            POLYGON 190.400 751.600  190.400 755.000  189.500 755.000  189.500 805.000  190.400 805.000  190.400 811.300  199.600 811.300  199.600 805.000  200.500 805.000  200.500 755.000  199.600 755.000  199.600 751.600 ;
            POLYGON 208.300 751.600  208.300 755.000  207.300 755.000  207.300 805.000  206.800 805.000  206.800 811.300  213.200 811.300  213.200 805.000  212.700 805.000  212.700 755.000  211.700 755.000  211.700 751.600 ;
            POLYGON 220.400 751.600  220.400 755.000  219.500 755.000  219.500 805.000  220.400 805.000  220.400 811.300  229.600 811.300  229.600 805.000  230.500 805.000  230.500 755.000  229.600 755.000  229.600 751.600 ;
            POLYGON 238.300 751.600  238.300 755.000  237.300 755.000  237.300 805.000  236.800 805.000  236.800 811.300  243.200 811.300  243.200 805.000  242.700 805.000  242.700 755.000  241.700 755.000  241.700 751.600 ;
            POLYGON 250.400 751.600  250.400 755.000  249.500 755.000  249.500 805.000  250.400 805.000  250.400 811.300  259.600 811.300  259.600 805.000  260.500 805.000  260.500 755.000  259.600 755.000  259.600 751.600 ;
            POLYGON 268.200 751.600  268.200 755.000  267.300 755.000  267.300 805.000  266.800 805.000  266.800 811.300  273.200 811.300  273.200 805.000  272.700 805.000  272.700 755.000  271.600 755.000  271.600 751.600 ;
            POLYGON 281.800 751.600  281.800 755.000  282.300 755.000  282.300 805.000  281.800 805.000  281.800 811.300  291.000 811.300  291.000 805.000  290.500 805.000  290.500 755.000  291.000 755.000  291.000 751.600 ;
            POLYGON 116.500 742.000  116.500 818.000  143.000 818.000  143.000 821.400  276.900 821.400  276.900 818.000  303.500 818.000  303.500 742.000 ;
            POLYGON 129.000 888.700  129.000 895.000  129.500 895.000  129.500 945.000  129.000 945.000  129.000 948.400  138.200 948.400  138.200 945.000  137.700 945.000  137.700 895.000  138.200 895.000  138.200 888.700 ;
            POLYGON 146.800 888.700  146.800 895.000  147.300 895.000  147.300 945.000  148.300 945.000  148.300 948.400  151.700 948.400  151.700 945.000  152.700 945.000  152.700 895.000  153.200 895.000  153.200 888.700 ;
            POLYGON 160.400 888.700  160.400 895.000  159.500 895.000  159.500 945.000  160.400 945.000  160.400 948.400  169.600 948.400  169.600 945.000  170.500 945.000  170.500 895.000  169.600 895.000  169.600 888.700 ;
            POLYGON 176.800 888.700  176.800 895.000  177.300 895.000  177.300 945.000  178.300 945.000  178.300 948.400  181.700 948.400  181.700 945.000  182.700 945.000  182.700 895.000  183.200 895.000  183.200 888.700 ;
            POLYGON 190.400 888.700  190.400 895.000  189.500 895.000  189.500 945.000  190.400 945.000  190.400 948.400  199.600 948.400  199.600 945.000  200.500 945.000  200.500 895.000  199.600 895.000  199.600 888.700 ;
            POLYGON 206.800 888.700  206.800 895.000  207.300 895.000  207.300 945.000  208.300 945.000  208.300 948.400  211.700 948.400  211.700 945.000  212.700 945.000  212.700 895.000  213.200 895.000  213.200 888.700 ;
            POLYGON 220.400 888.700  220.400 895.000  219.500 895.000  219.500 945.000  220.400 945.000  220.400 948.400  229.600 948.400  229.600 945.000  230.500 945.000  230.500 895.000  229.600 895.000  229.600 888.700 ;
            POLYGON 236.800 888.700  236.800 895.000  237.300 895.000  237.300 945.000  238.300 945.000  238.300 948.400  241.700 948.400  241.700 945.000  242.700 945.000  242.700 895.000  243.200 895.000  243.200 888.700 ;
            POLYGON 250.400 888.700  250.400 895.000  249.500 895.000  249.500 945.000  250.400 945.000  250.400 948.400  259.600 948.400  259.600 945.000  260.500 945.000  260.500 895.000  259.600 895.000  259.600 888.700 ;
            POLYGON 266.800 888.700  266.800 895.000  267.300 895.000  267.300 945.000  268.200 945.000  268.200 948.400  271.600 948.400  271.600 945.000  272.700 945.000  272.700 895.000  273.200 895.000  273.200 888.700 ;
            POLYGON 281.800 888.700  281.800 895.000  282.300 895.000  282.300 945.000  281.800 945.000  281.800 948.400  291.000 948.400  291.000 945.000  290.500 945.000  290.500 895.000  291.000 895.000  291.000 888.700 ;
            POLYGON 294.600 946.300  294.600 950.000  276.800 950.000  276.800 946.400  274.200 946.400  274.200 950.000  265.800 950.000  265.800 946.400  263.200 946.400  263.200 950.000  246.800 950.000  246.800 946.400  244.200 946.400  244.200 951.800  298.000 951.800  298.000 946.300 ;
            POLYGON 143.000 878.600  143.000 882.000  116.500 882.000  116.500 958.000  303.500 958.000  303.500 882.000  276.900 882.000  276.900 878.600 ;
            POLYGON 311.000 1012.900  311.000 1017.900  311.800 1017.900  311.800 1026.100  307.400 1026.100  307.400 1025.700  304.800 1025.700  304.800 1028.300  307.400 1028.300  307.400 1027.900  311.800 1027.900  311.800 1037.200  313.200 1037.200  313.200 1038.000  315.800 1038.000  315.800 1035.400  313.600 1035.400  313.600 1012.900 ;
            POLYGON 294.600 992.700  294.600 996.100  301.000 996.100  301.000 1041.700  303.600 1041.700  303.600 1035.100  302.800 1035.100  302.800 1017.900  303.600 1017.900  303.600 992.700 ;
            POLYGON 323.800 1028.300  323.800 1031.700  324.400 1031.700  324.400 1043.200  328.000 1043.200  328.000 1031.700  330.000 1031.700  330.000 1028.300 ;
            POLYGON 319.000 1013.100  319.000 1044.700  313.700 1044.700  313.700 1047.300  321.600 1047.300  321.600 1040.200  320.800 1040.200  320.800 1018.000  321.600 1018.000  321.600 1013.100 ;
            POLYGON 319.000 1053.700  319.000 1056.300  321.600 1056.300  321.600 1053.700 ;
            POLYGON 305.000 1035.100  305.000 1048.700  300.000 1048.700  300.000 1051.300  305.000 1051.300  305.000 1064.900  307.600 1064.900  307.600 1064.600  309.600 1064.600  309.600 1062.000  307.600 1062.000  307.600 1060.200  315.000 1060.200  315.000 1064.600  317.600 1064.600  317.600 1062.000  316.800 1062.000  316.800 1058.400  307.600 1058.400  307.600 1051.300  322.800 1051.300  322.800 1051.700  330.000 1051.700  330.000 1048.300  322.800 1048.300  322.800 1048.700  307.600 1048.700  307.600 1042.800  317.600 1042.800  317.600 1040.200  307.600 1040.200  307.600 1038.000  309.600 1038.000  309.600 1035.400  307.600 1035.400  307.600 1035.100 ;
            POLYGON 324.400 1061.400  324.400 1068.300  323.800 1068.300  323.800 1071.700  330.000 1071.700  330.000 1068.300  328.000 1068.300  328.000 1061.400 ;
            POLYGON 311.000 1062.000  311.000 1072.100  307.400 1072.100  307.400 1071.700  304.800 1071.700  304.800 1074.300  307.400 1074.300  307.400 1073.900  313.200 1073.900  313.200 1091.500  315.800 1091.500  315.800 1082.900  315.000 1082.900  315.000 1072.100  312.800 1072.100  312.800 1064.600  313.600 1064.600  313.600 1062.000 ;
            POLYGON 319.000 1062.000  319.000 1104.400  312.000 1104.400  312.000 1107.000  314.600 1107.000  314.600 1106.200  321.600 1106.200  321.600 1094.100  320.800 1094.100  320.800 1064.600  321.600 1064.600  321.600 1062.000 ;
            POLYGON 301.000 1058.300  301.000 1103.900  294.600 1103.900  294.600 1107.300  303.600 1107.300  303.600 1082.100  302.800 1082.100  302.800 1064.900  303.600 1064.900  303.600 1058.300 ;
            POLYGON 160.000 972.000  160.000 1128.000  260.000 1128.000  260.000 1012.000  274.000 1012.000  274.000 981.700  330.000 981.700  330.000 978.300  274.000 978.300  274.000 972.000 ;
            POLYGON 203.200 1146.800  203.200 1153.600  205.800 1153.600  205.800 1149.400  214.200 1149.400  214.200 1153.600  216.800 1153.600  216.800 1149.400  233.200 1149.400  233.200 1153.600  235.800 1153.600  235.800 1149.400  244.200 1149.400  244.200 1153.600  246.800 1153.600  246.800 1149.400  263.200 1149.400  263.200 1153.600  265.800 1153.600  265.800 1149.400  274.200 1149.400  274.200 1153.600  276.800 1153.600  276.800 1149.400  294.600 1149.400  294.600 1153.700  298.000 1153.700  298.000 1146.800 ;
            POLYGON 129.000 1151.600  129.000 1155.000  129.500 1155.000  129.500 1205.000  129.000 1205.000  129.000 1211.300  138.200 1211.300  138.200 1205.000  137.700 1205.000  137.700 1155.000  138.200 1155.000  138.200 1151.600 ;
            POLYGON 148.400 1151.600  148.400 1155.000  147.300 1155.000  147.300 1205.000  146.800 1205.000  146.800 1211.300  153.200 1211.300  153.200 1205.000  152.700 1205.000  152.700 1155.000  151.800 1155.000  151.800 1151.600 ;
            POLYGON 160.400 1151.600  160.400 1155.000  159.500 1155.000  159.500 1205.000  160.400 1205.000  160.400 1211.300  169.600 1211.300  169.600 1205.000  170.500 1205.000  170.500 1155.000  169.600 1155.000  169.600 1151.600 ;
            POLYGON 178.300 1151.600  178.300 1155.000  177.300 1155.000  177.300 1205.000  176.800 1205.000  176.800 1211.300  183.200 1211.300  183.200 1205.000  182.700 1205.000  182.700 1155.000  181.700 1155.000  181.700 1151.600 ;
            POLYGON 190.400 1151.600  190.400 1155.000  189.500 1155.000  189.500 1205.000  190.400 1205.000  190.400 1211.300  199.600 1211.300  199.600 1205.000  200.500 1205.000  200.500 1155.000  199.600 1155.000  199.600 1151.600 ;
            POLYGON 208.300 1151.600  208.300 1155.000  207.300 1155.000  207.300 1205.000  206.800 1205.000  206.800 1211.300  213.200 1211.300  213.200 1205.000  212.700 1205.000  212.700 1155.000  211.700 1155.000  211.700 1151.600 ;
            POLYGON 220.400 1151.600  220.400 1155.000  219.500 1155.000  219.500 1205.000  220.400 1205.000  220.400 1211.300  229.600 1211.300  229.600 1205.000  230.500 1205.000  230.500 1155.000  229.600 1155.000  229.600 1151.600 ;
            POLYGON 238.300 1151.600  238.300 1155.000  237.300 1155.000  237.300 1205.000  236.800 1205.000  236.800 1211.300  243.200 1211.300  243.200 1205.000  242.700 1205.000  242.700 1155.000  241.700 1155.000  241.700 1151.600 ;
            POLYGON 250.400 1151.600  250.400 1155.000  249.500 1155.000  249.500 1205.000  250.400 1205.000  250.400 1211.300  259.600 1211.300  259.600 1205.000  260.500 1205.000  260.500 1155.000  259.600 1155.000  259.600 1151.600 ;
            POLYGON 268.300 1151.600  268.300 1155.000  267.300 1155.000  267.300 1205.000  266.800 1205.000  266.800 1211.300  273.200 1211.300  273.200 1205.000  272.700 1205.000  272.700 1155.000  271.700 1155.000  271.700 1151.600 ;
            POLYGON 281.800 1151.600  281.800 1155.000  282.300 1155.000  282.300 1205.000  281.800 1205.000  281.800 1211.300  291.000 1211.300  291.000 1205.000  290.500 1205.000  290.500 1155.000  291.000 1155.000  291.000 1151.600 ;
            POLYGON 291.400 988.700  291.400 1111.300  300.000 1111.300  300.000 1142.000  116.500 1142.000  116.500 1218.000  143.300 1218.000  143.300 1221.400  277.200 1221.400  277.200 1218.000  308.000 1218.000  308.000 1111.300  319.100 1111.300  319.100 1108.700  309.600 1108.700  309.600 1098.700  317.600 1098.700  317.600 1094.100  309.600 1094.100  309.600 1082.100  305.000 1082.100  305.000 1108.700  293.200 1108.700  293.200 991.300  305.000 991.300  305.000 1017.900  309.600 1017.900  309.600 1012.900  307.600 1012.900  307.600 1011.100  315.000 1011.100  315.000 1017.700  317.600 1017.700  317.600 1009.300  307.600 1009.300  307.600 991.300  319.100 991.300  319.100 988.700 ;
            POLYGON 319.000 643.700  319.000 646.300  321.600 646.300  321.600 643.700 ;
            POLYGON 495.000 249.500  495.000 250.400  488.700 250.400  488.700 259.600  495.000 259.600  495.000 260.500  545.000 260.500  545.000 259.600  548.400 259.600  548.400 250.400  545.000 250.400  545.000 249.500 ;
            POLYGON 488.700 266.800  488.700 273.200  495.000 273.200  495.000 272.700  545.000 272.700  545.000 271.700  548.400 271.700  548.400 268.300  545.000 268.300  545.000 267.300  495.000 267.300  495.000 266.800 ;
            POLYGON 488.700 281.800  488.700 291.000  495.000 291.000  495.000 290.500  545.000 290.500  545.000 291.000  548.400 291.000  548.400 281.800  545.000 281.800  545.000 282.300  495.000 282.300  495.000 281.800 ;
            POLYGON 546.400 203.200  546.400 205.800  550.600 205.800  550.600 214.200  546.400 214.200  546.400 216.800  550.600 216.800  550.600 233.200  546.400 233.200  546.400 235.800  550.600 235.800  550.600 244.200  546.400 244.200  546.400 246.800  550.600 246.800  550.600 263.200  546.400 263.200  546.400 265.800  550.600 265.800  550.600 274.200  546.400 274.200  546.400 276.800  550.600 276.800  550.600 294.600  546.300 294.600  546.300 298.000  553.200 298.000  553.200 203.200 ;
            POLYGON 592.700 294.600  592.700 303.600  617.900 303.600  617.900 302.800  635.100 302.800  635.100 303.600  641.700 303.600  641.700 301.000  596.100 301.000  596.100 294.600 ;
            POLYGON 625.700 304.800  625.700 307.400  626.100 307.400  626.100 313.200  608.500 313.200  608.500 315.800  617.100 315.800  617.100 315.000  627.900 315.000  627.900 312.800  635.400 312.800  635.400 313.600  638.000 313.600  638.000 311.000  627.900 311.000  627.900 307.400  628.300 307.400  628.300 304.800 ;
            POLYGON 488.700 206.800  488.700 213.200  495.000 213.200  495.000 212.700  545.000 212.700  545.000 211.700  548.400 211.700  548.400 208.300  545.000 208.300  545.000 207.300  495.000 207.300  495.000 206.800 ;
            POLYGON 593.000 312.000  593.000 314.600  593.800 314.600  593.800 321.600  605.900 321.600  605.900 320.800  635.400 320.800  635.400 321.600  638.000 321.600  638.000 319.000  595.600 319.000  595.600 312.000 ;
            POLYGON 643.700 319.000  643.700 321.600  646.300 321.600  646.300 319.000 ;
            POLYGON 628.300 323.800  628.300 330.000  631.700 330.000  631.700 328.000  638.600 328.000  638.600 324.400  631.700 324.400  631.700 323.800 ;
            POLYGON 495.000 219.500  495.000 220.400  488.700 220.400  488.700 229.600  495.000 229.600  495.000 230.500  545.000 230.500  545.000 229.600  548.400 229.600  548.400 220.400  545.000 220.400  545.000 219.500 ;
            POLYGON 488.700 236.800  488.700 243.200  495.000 243.200  495.000 242.700  545.000 242.700  545.000 241.700  548.400 241.700  548.400 238.300  545.000 238.300  545.000 237.300  495.000 237.300  495.000 236.800 ;
            POLYGON 129.000 488.700  129.000 495.000  129.500 495.000  129.500 545.000  129.000 545.000  129.000 548.400  138.200 548.400  138.200 545.000  137.700 545.000  137.700 495.000  138.200 495.000  138.200 488.700 ;
            POLYGON 146.800 488.700  146.800 495.000  147.300 495.000  147.300 545.000  148.400 545.000  148.400 548.400  151.800 548.400  151.800 545.000  152.700 545.000  152.700 495.000  153.200 495.000  153.200 488.700 ;
            POLYGON 160.400 488.700  160.400 495.000  159.500 495.000  159.500 545.000  160.400 545.000  160.400 548.400  169.600 548.400  169.600 545.000  170.500 545.000  170.500 495.000  169.600 495.000  169.600 488.700 ;
            POLYGON 176.800 488.700  176.800 495.000  177.300 495.000  177.300 545.000  178.300 545.000  178.300 548.400  181.700 548.400  181.700 545.000  182.700 545.000  182.700 495.000  183.200 495.000  183.200 488.700 ;
            POLYGON 190.400 488.700  190.400 495.000  189.500 495.000  189.500 545.000  190.400 545.000  190.400 548.400  199.600 548.400  199.600 545.000  200.500 545.000  200.500 495.000  199.600 495.000  199.600 488.700 ;
            POLYGON 206.800 488.700  206.800 495.000  207.300 495.000  207.300 545.000  208.300 545.000  208.300 548.400  211.700 548.400  211.700 545.000  212.700 545.000  212.700 495.000  213.200 495.000  213.200 488.700 ;
            POLYGON 220.400 488.700  220.400 495.000  219.500 495.000  219.500 545.000  220.400 545.000  220.400 548.400  229.600 548.400  229.600 545.000  230.500 545.000  230.500 495.000  229.600 495.000  229.600 488.700 ;
            POLYGON 236.800 488.700  236.800 495.000  237.300 495.000  237.300 545.000  238.300 545.000  238.300 548.400  241.700 548.400  241.700 545.000  242.700 545.000  242.700 495.000  243.200 495.000  243.200 488.700 ;
            POLYGON 250.400 488.700  250.400 495.000  249.500 495.000  249.500 545.000  250.400 545.000  250.400 548.400  259.600 548.400  259.600 545.000  260.500 545.000  260.500 495.000  259.600 495.000  259.600 488.700 ;
            POLYGON 266.800 488.700  266.800 495.000  267.300 495.000  267.300 545.000  268.300 545.000  268.300 548.400  271.700 548.400  271.700 545.000  272.700 545.000  272.700 495.000  273.200 495.000  273.200 488.700 ;
            POLYGON 281.800 488.700  281.800 495.000  282.300 495.000  282.300 545.000  281.800 545.000  281.800 548.400  291.000 548.400  291.000 545.000  290.500 545.000  290.500 495.000  291.000 495.000  291.000 488.700 ;
            POLYGON 294.600 546.300  294.600 550.600  276.800 550.600  276.800 546.400  274.200 546.400  274.200 550.600  265.800 550.600  265.800 546.400  263.200 546.400  263.200 550.600  246.800 550.600  246.800 546.400  244.200 546.400  244.200 550.600  235.800 550.600  235.800 546.400  233.200 546.400  233.200 550.600  216.800 550.600  216.800 546.400  214.200 546.400  214.200 550.600  205.800 550.600  205.800 546.400  203.200 546.400  203.200 553.200  298.000 553.200  298.000 546.300 ;
            POLYGON 313.200 608.500  313.200 626.100  307.400 626.100  307.400 625.700  304.800 625.700  304.800 628.300  307.400 628.300  307.400 627.900  311.000 627.900  311.000 638.000  313.600 638.000  313.600 635.400  312.800 635.400  312.800 627.900  315.000 627.900  315.000 617.100  315.800 617.100  315.800 608.500 ;
            POLYGON 312.000 593.000  312.000 595.600  319.000 595.600  319.000 638.000  321.600 638.000  321.600 635.400  320.800 635.400  320.800 605.900  321.600 605.900  321.600 593.800  314.600 593.800  314.600 593.000 ;
            POLYGON 323.800 628.300  323.800 631.700  324.400 631.700  324.400 638.600  328.000 638.600  328.000 631.700  330.000 631.700  330.000 628.300 ;
            POLYGON 294.600 592.700  294.600 596.100  301.000 596.100  301.000 641.700  303.600 641.700  303.600 635.100  302.800 635.100  302.800 617.900  303.600 617.900  303.600 592.700 ;
            POLYGON 488.700 129.000  488.700 138.200  495.000 138.200  495.000 137.700  545.000 137.700  545.000 138.200  548.400 138.200  548.400 129.000  545.000 129.000  545.000 129.500  495.000 129.500  495.000 129.000 ;
            POLYGON 488.700 146.800  488.700 153.200  495.000 153.200  495.000 152.700  545.000 152.700  545.000 151.800  548.400 151.800  548.400 148.400  545.000 148.400  545.000 147.300  495.000 147.300  495.000 146.800 ;
            POLYGON 495.000 159.500  495.000 160.400  488.700 160.400  488.700 169.600  495.000 169.600  495.000 170.500  545.000 170.500  545.000 169.600  548.400 169.600  548.400 160.400  545.000 160.400  545.000 159.500 ;
            POLYGON 488.700 176.800  488.700 183.200  495.000 183.200  495.000 182.700  545.000 182.700  545.000 181.700  548.400 181.700  548.400 178.300  545.000 178.300  545.000 177.300  495.000 177.300  495.000 176.800 ;
            POLYGON 495.000 189.500  495.000 190.400  488.700 190.400  488.700 199.600  495.000 199.600  495.000 200.500  545.000 200.500  545.000 199.600  548.400 199.600  548.400 190.400  545.000 190.400  545.000 189.500 ;
            POLYGON 652.700 313.700  652.700 321.600  659.800 321.600  659.800 320.800  682.000 320.800  682.000 321.600  686.900 321.600  686.900 319.000  655.300 319.000  655.300 313.700 ;
            POLYGON 805.000 236.800  805.000 237.300  755.000 237.300  755.000 238.300  751.600 238.300  751.600 241.700  755.000 241.700  755.000 242.700  805.000 242.700  805.000 243.200  811.300 243.200  811.300 236.800 ;
            POLYGON 945.000 236.800  945.000 237.300  895.000 237.300  895.000 238.300  891.600 238.300  891.600 241.700  895.000 241.700  895.000 242.700  945.000 242.700  945.000 243.200  951.300 243.200  951.300 236.800 ;
            POLYGON 668.300 323.800  668.300 324.400  656.800 324.400  656.800 328.000  668.300 328.000  668.300 330.000  671.700 330.000  671.700 323.800 ;
            POLYGON 1205.000 236.800  1205.000 237.300  1155.000 237.300  1155.000 238.300  1151.600 238.300  1151.600 241.700  1155.000 241.700  1155.000 242.700  1205.000 242.700  1205.000 243.200  1211.300 243.200  1211.300 236.800 ;
            POLYGON 755.000 189.500  755.000 190.400  751.600 190.400  751.600 199.600  755.000 199.600  755.000 200.500  805.000 200.500  805.000 199.600  811.300 199.600  811.300 190.400  805.000 190.400  805.000 189.500 ;
            POLYGON 755.000 249.500  755.000 250.400  751.600 250.400  751.600 259.600  755.000 259.600  755.000 260.500  805.000 260.500  805.000 259.600  811.300 259.600  811.300 250.400  805.000 250.400  805.000 249.500 ;
            POLYGON 895.000 249.500  895.000 250.400  891.600 250.400  891.600 259.600  895.000 259.600  895.000 260.500  945.000 260.500  945.000 259.600  951.300 259.600  951.300 250.400  945.000 250.400  945.000 249.500 ;
            POLYGON 1155.000 249.500  1155.000 250.400  1151.600 250.400  1151.600 259.600  1155.000 259.600  1155.000 260.500  1205.000 260.500  1205.000 259.600  1211.300 259.600  1211.300 250.400  1205.000 250.400  1205.000 249.500 ;
            POLYGON 805.000 206.800  805.000 207.300  755.000 207.300  755.000 208.300  751.600 208.300  751.600 211.700  755.000 211.700  755.000 212.700  805.000 212.700  805.000 213.200  811.300 213.200  811.300 206.800 ;
            POLYGON 805.000 266.800  805.000 267.300  755.000 267.300  755.000 268.200  751.600 268.200  751.600 271.600  755.000 271.600  755.000 272.700  805.000 272.700  805.000 273.200  811.300 273.200  811.300 266.800 ;
            POLYGON 945.000 266.800  945.000 267.300  895.000 267.300  895.000 268.300  891.600 268.300  891.600 271.700  895.000 271.700  895.000 272.700  945.000 272.700  945.000 273.200  951.300 273.200  951.300 266.800 ;
            POLYGON 1205.000 266.800  1205.000 267.300  1155.000 267.300  1155.000 268.300  1151.600 268.300  1151.600 271.700  1155.000 271.700  1155.000 272.700  1205.000 272.700  1205.000 273.200  1211.300 273.200  1211.300 266.800 ;
            POLYGON 945.000 206.800  945.000 207.300  895.000 207.300  895.000 208.300  891.600 208.300  891.600 211.700  895.000 211.700  895.000 212.700  945.000 212.700  945.000 213.200  951.300 213.200  951.300 206.800 ;
            POLYGON 751.600 281.800  751.600 291.000  755.000 291.000  755.000 290.500  805.000 290.500  805.000 291.000  811.300 291.000  811.300 281.800  805.000 281.800  805.000 282.300  755.000 282.300  755.000 281.800 ;
            POLYGON 891.600 281.800  891.600 291.000  895.000 291.000  895.000 290.500  945.000 290.500  945.000 291.000  951.300 291.000  951.300 281.800  945.000 281.800  945.000 282.300  895.000 282.300  895.000 281.800 ;
            POLYGON 1151.600 281.800  1151.600 291.000  1155.000 291.000  1155.000 290.500  1205.000 290.500  1205.000 291.000  1211.300 291.000  1211.300 281.800  1205.000 281.800  1205.000 282.300  1155.000 282.300  1155.000 281.800 ;
            POLYGON 1205.000 206.800  1205.000 207.300  1155.000 207.300  1155.000 208.300  1151.600 208.300  1151.600 211.700  1155.000 211.700  1155.000 212.700  1205.000 212.700  1205.000 213.200  1211.300 213.200  1211.300 206.800 ;
            POLYGON 748.200 244.200  748.200 298.000  753.700 298.000  753.700 294.600  750.000 294.600  750.000 276.800  753.600 276.800  753.600 274.200  750.000 274.200  750.000 265.800  753.600 265.800  753.600 263.200  750.000 263.200  750.000 246.800  753.600 246.800  753.600 244.200 ;
            POLYGON 742.000 116.500  742.000 303.500  818.000 303.500  818.000 276.900  821.400 276.900  821.400 143.000  818.000 143.000  818.000 116.500 ;
            POLYGON 1142.000 116.500  1142.000 303.500  1218.000 303.500  1218.000 277.200  1221.400 277.200  1221.400 143.300  1218.000 143.300  1218.000 116.500 ;
            POLYGON 895.000 189.500  895.000 190.400  891.600 190.400  891.600 199.600  895.000 199.600  895.000 200.500  945.000 200.500  945.000 199.600  951.300 199.600  951.300 190.400  945.000 190.400  945.000 189.500 ;
            POLYGON 703.900 294.600  703.900 301.000  658.300 301.000  658.300 303.600  664.900 303.600  664.900 302.800  682.100 302.800  682.100 303.600  707.300 303.600  707.300 294.600 ;
            POLYGON 755.000 219.500  755.000 220.400  751.600 220.400  751.600 229.600  755.000 229.600  755.000 230.500  805.000 230.500  805.000 229.600  811.300 229.600  811.300 220.400  805.000 220.400  805.000 219.500 ;
            POLYGON 751.600 129.000  751.600 138.200  755.000 138.200  755.000 137.700  805.000 137.700  805.000 138.200  811.300 138.200  811.300 129.000  805.000 129.000  805.000 129.500  755.000 129.500  755.000 129.000 ;
            POLYGON 891.600 129.000  891.600 138.200  895.000 138.200  895.000 137.700  945.000 137.700  945.000 138.200  951.300 138.200  951.300 129.000  945.000 129.000  945.000 129.500  895.000 129.500  895.000 129.000 ;
            POLYGON 1151.600 129.000  1151.600 138.200  1155.000 138.200  1155.000 137.700  1205.000 137.700  1205.000 138.200  1211.300 138.200  1211.300 129.000  1205.000 129.000  1205.000 129.500  1155.000 129.500  1155.000 129.000 ;
            POLYGON 671.700 304.800  671.700 307.400  672.100 307.400  672.100 311.800  662.800 311.800  662.800 313.200  662.000 313.200  662.000 315.800  664.600 315.800  664.600 313.600  687.100 313.600  687.100 311.000  682.100 311.000  682.100 311.800  673.900 311.800  673.900 307.400  674.300 307.400  674.300 304.800 ;
            POLYGON 805.000 146.800  805.000 147.300  755.000 147.300  755.000 148.300  751.600 148.300  751.600 151.700  755.000 151.700  755.000 152.700  805.000 152.700  805.000 153.200  811.300 153.200  811.300 146.800 ;
            POLYGON 945.000 146.800  945.000 147.300  895.000 147.300  895.000 148.400  891.600 148.400  891.600 151.800  895.000 151.800  895.000 152.700  945.000 152.700  945.000 153.200  951.300 153.200  951.300 146.800 ;
            POLYGON 1205.000 146.800  1205.000 147.300  1155.000 147.300  1155.000 148.400  1151.600 148.400  1151.600 151.800  1155.000 151.800  1155.000 152.700  1205.000 152.700  1205.000 153.200  1211.300 153.200  1211.300 146.800 ;
            POLYGON 895.000 219.500  895.000 220.400  891.600 220.400  891.600 229.600  895.000 229.600  895.000 230.500  945.000 230.500  945.000 229.600  951.300 229.600  951.300 220.400  945.000 220.400  945.000 219.500 ;
            POLYGON 755.000 159.500  755.000 160.400  751.600 160.400  751.600 169.600  755.000 169.600  755.000 170.500  805.000 170.500  805.000 169.600  811.300 169.600  811.300 160.400  805.000 160.400  805.000 159.500 ;
            POLYGON 895.000 159.500  895.000 160.400  891.600 160.400  891.600 169.600  895.000 169.600  895.000 170.500  945.000 170.500  945.000 169.600  951.300 169.600  951.300 160.400  945.000 160.400  945.000 159.500 ;
            POLYGON 1155.000 159.500  1155.000 160.400  1151.600 160.400  1151.600 169.600  1155.000 169.600  1155.000 170.500  1205.000 170.500  1205.000 169.600  1211.300 169.600  1211.300 160.400  1205.000 160.400  1205.000 159.500 ;
            POLYGON 1155.000 219.500  1155.000 220.400  1151.600 220.400  1151.600 229.600  1155.000 229.600  1155.000 230.500  1205.000 230.500  1205.000 229.600  1211.300 229.600  1211.300 220.400  1205.000 220.400  1205.000 219.500 ;
            POLYGON 805.000 176.800  805.000 177.300  755.000 177.300  755.000 178.300  751.600 178.300  751.600 181.700  755.000 181.700  755.000 182.700  805.000 182.700  805.000 183.200  811.300 183.200  811.300 176.800 ;
            POLYGON 945.000 176.800  945.000 177.300  895.000 177.300  895.000 178.300  891.600 178.300  891.600 181.700  895.000 181.700  895.000 182.700  945.000 182.700  945.000 183.200  951.300 183.200  951.300 176.800 ;
            POLYGON 1205.000 176.800  1205.000 177.300  1155.000 177.300  1155.000 178.300  1151.600 178.300  1151.600 181.700  1155.000 181.700  1155.000 182.700  1205.000 182.700  1205.000 183.200  1211.300 183.200  1211.300 176.800 ;
            POLYGON 1155.000 189.500  1155.000 190.400  1151.600 190.400  1151.600 199.600  1155.000 199.600  1155.000 200.500  1205.000 200.500  1205.000 199.600  1211.300 199.600  1211.300 190.400  1205.000 190.400  1205.000 189.500 ;
            POLYGON 2192.400 635.100  2192.400 635.400  2190.400 635.400  2190.400 638.000  2192.400 638.000  2192.400 639.800  2185.000 639.800  2185.000 635.400  2182.400 635.400  2182.400 638.000  2183.200 638.000  2183.200 641.600  2192.400 641.600  2192.400 648.700  2177.200 648.700  2177.200 648.300  2170.000 648.300  2170.000 651.700  2177.200 651.700  2177.200 651.300  2192.400 651.300  2192.400 657.200  2182.400 657.200  2182.400 659.800  2192.400 659.800  2192.400 662.000  2190.400 662.000  2190.400 664.600  2192.400 664.600  2192.400 664.900  2195.000 664.900  2195.000 651.300  2200.000 651.300  2200.000 648.700  2195.000 648.700  2195.000 635.100 ;
            POLYGON 2222.800 478.600  2222.800 482.000  2192.000 482.000  2192.000 588.700  2180.900 588.700  2180.900 591.300  2190.400 591.300  2190.400 601.300  2182.400 601.300  2182.400 605.900  2190.400 605.900  2190.400 617.900  2195.000 617.900  2195.000 591.300  2206.800 591.300  2206.800 708.700  2195.000 708.700  2195.000 682.100  2190.400 682.100  2190.400 687.100  2192.400 687.100  2192.400 688.900  2185.000 688.900  2185.000 682.300  2182.400 682.300  2182.400 690.700  2192.400 690.700  2192.400 708.700  2180.900 708.700  2180.900 711.300  2208.600 711.300  2208.600 588.700  2200.000 588.700  2200.000 558.000  2383.500 558.000  2383.500 482.000  2356.700 482.000  2356.700 478.600 ;
            POLYGON 2240.000 572.000  2240.000 688.000  2226.000 688.000  2226.000 718.300  2170.000 718.300  2170.000 721.700  2226.000 721.700  2226.000 728.000  2340.000 728.000  2340.000 572.000 ;
            POLYGON 1942.000 116.500  1942.000 300.000  1911.300 300.000  1911.300 291.400  1788.700 291.400  1788.700 319.100  1791.300 319.100  1791.300 307.600  1809.300 307.600  1809.300 317.600  1817.700 317.600  1817.700 315.000  1811.100 315.000  1811.100 307.600  1812.900 307.600  1812.900 309.600  1817.900 309.600  1817.900 305.000  1791.300 305.000  1791.300 293.200  1908.700 293.200  1908.700 305.000  1882.100 305.000  1882.100 309.600  1894.100 309.600  1894.100 317.600  1898.700 317.600  1898.700 309.600  1908.700 309.600  1908.700 319.100  1911.300 319.100  1911.300 308.000  2018.000 308.000  2018.000 277.200  2021.400 277.200  2021.400 143.300  2018.000 143.300  2018.000 116.500 ;
            POLYGON 1772.000 160.000  1772.000 274.000  1778.300 274.000  1778.300 330.000  1781.700 330.000  1781.700 274.000  1812.000 274.000  1812.000 260.000  1928.000 260.000  1928.000 160.000 ;
            POLYGON 1848.700 300.000  1848.700 305.000  1835.100 305.000  1835.100 307.600  1835.400 307.600  1835.400 309.600  1838.000 309.600  1838.000 307.600  1840.200 307.600  1840.200 317.600  1842.800 317.600  1842.800 307.600  1848.700 307.600  1848.700 322.800  1848.300 322.800  1848.300 330.000  1851.700 330.000  1851.700 322.800  1851.300 322.800  1851.300 307.600  1858.400 307.600  1858.400 316.800  1862.000 316.800  1862.000 317.600  1864.600 317.600  1864.600 315.000  1860.200 315.000  1860.200 307.600  1862.000 307.600  1862.000 309.600  1864.600 309.600  1864.600 307.600  1864.900 307.600  1864.900 305.000  1851.300 305.000  1851.300 300.000 ;
            POLYGON 2330.400 1151.600  2330.400 1155.000  2329.500 1155.000  2329.500 1205.000  2330.400 1205.000  2330.400 1211.300  2339.600 1211.300  2339.600 1205.000  2340.500 1205.000  2340.500 1155.000  2339.600 1155.000  2339.600 1151.600 ;
            POLYGON 2348.200 1151.600  2348.200 1155.000  2347.300 1155.000  2347.300 1205.000  2346.800 1205.000  2346.800 1211.300  2353.200 1211.300  2353.200 1205.000  2352.700 1205.000  2352.700 1155.000  2351.600 1155.000  2351.600 1151.600 ;
            POLYGON 2361.800 1151.600  2361.800 1155.000  2362.300 1155.000  2362.300 1205.000  2361.800 1205.000  2361.800 1211.300  2371.000 1211.300  2371.000 1205.000  2370.500 1205.000  2370.500 1155.000  2371.000 1155.000  2371.000 1151.600 ;
            POLYGON 2180.900 988.700  2180.900 991.300  2192.400 991.300  2192.400 1009.300  2182.400 1009.300  2182.400 1017.700  2185.000 1017.700  2185.000 1011.100  2192.400 1011.100  2192.400 1012.900  2190.400 1012.900  2190.400 1017.900  2195.000 1017.900  2195.000 991.300  2206.800 991.300  2206.800 1108.700  2195.000 1108.700  2195.000 1082.100  2190.400 1082.100  2190.400 1094.100  2182.400 1094.100  2182.400 1098.700  2190.400 1098.700  2190.400 1108.700  2180.900 1108.700  2180.900 1111.300  2192.000 1111.300  2192.000 1218.000  2222.800 1218.000  2222.800 1221.400  2356.700 1221.400  2356.700 1218.000  2383.500 1218.000  2383.500 1142.000  2200.000 1142.000  2200.000 1111.300  2208.600 1111.300  2208.600 988.700 ;
            POLYGON 2240.400 1151.600  2240.400 1155.000  2239.500 1155.000  2239.500 1205.000  2240.400 1205.000  2240.400 1211.300  2249.600 1211.300  2249.600 1205.000  2250.500 1205.000  2250.500 1155.000  2249.600 1155.000  2249.600 1151.600 ;
            POLYGON 2172.000 656.800  2172.000 668.300  2170.000 668.300  2170.000 671.700  2176.200 671.700  2176.200 668.300  2175.600 668.300  2175.600 656.800 ;
            POLYGON 2178.400 652.700  2178.400 659.800  2179.200 659.800  2179.200 682.000  2178.400 682.000  2178.400 686.900  2181.000 686.900  2181.000 655.300  2186.300 655.300  2186.300 652.700 ;
            POLYGON 2184.200 662.000  2184.200 664.600  2186.400 664.600  2186.400 687.100  2189.000 687.100  2189.000 682.100  2188.200 682.100  2188.200 673.900  2192.600 673.900  2192.600 674.300  2195.200 674.300  2195.200 671.700  2192.600 671.700  2192.600 672.100  2188.200 672.100  2188.200 662.800  2186.800 662.800  2186.800 662.000 ;
            POLYGON 2196.400 658.300  2196.400 664.900  2197.200 664.900  2197.200 682.100  2196.400 682.100  2196.400 707.300  2205.400 707.300  2205.400 703.900  2199.000 703.900  2199.000 658.300 ;
            POLYGON 2258.300 1151.600  2258.300 1155.000  2257.300 1155.000  2257.300 1205.000  2256.800 1205.000  2256.800 1211.300  2263.200 1211.300  2263.200 1205.000  2262.700 1205.000  2262.700 1155.000  2261.700 1155.000  2261.700 1151.600 ;
            POLYGON 2270.400 1151.600  2270.400 1155.000  2269.500 1155.000  2269.500 1205.000  2270.400 1205.000  2270.400 1211.300  2279.600 1211.300  2279.600 1205.000  2280.500 1205.000  2280.500 1155.000  2279.600 1155.000  2279.600 1151.600 ;
            POLYGON 2202.000 748.200  2202.000 753.700  2205.400 753.700  2205.400 750.000  2223.200 750.000  2223.200 753.600  2225.800 753.600  2225.800 750.000  2234.200 750.000  2234.200 753.600  2236.800 753.600  2236.800 750.000  2253.200 750.000  2253.200 753.600  2255.800 753.600  2255.800 748.200 ;
            POLYGON 2209.000 751.600  2209.000 755.000  2209.500 755.000  2209.500 805.000  2209.000 805.000  2209.000 811.300  2218.200 811.300  2218.200 805.000  2217.700 805.000  2217.700 755.000  2218.200 755.000  2218.200 751.600 ;
            POLYGON 2228.400 751.600  2228.400 755.000  2227.300 755.000  2227.300 805.000  2226.800 805.000  2226.800 811.300  2233.200 811.300  2233.200 805.000  2232.700 805.000  2232.700 755.000  2231.800 755.000  2231.800 751.600 ;
            POLYGON 2240.400 751.600  2240.400 755.000  2239.500 755.000  2239.500 805.000  2240.400 805.000  2240.400 811.300  2249.600 811.300  2249.600 805.000  2250.500 805.000  2250.500 755.000  2249.600 755.000  2249.600 751.600 ;
            POLYGON 2258.300 751.600  2258.300 755.000  2257.300 755.000  2257.300 805.000  2256.800 805.000  2256.800 811.300  2263.200 811.300  2263.200 805.000  2262.700 805.000  2262.700 755.000  2261.700 755.000  2261.700 751.600 ;
            POLYGON 2270.400 751.600  2270.400 755.000  2269.500 755.000  2269.500 805.000  2270.400 805.000  2270.400 811.300  2279.600 811.300  2279.600 805.000  2280.500 805.000  2280.500 755.000  2279.600 755.000  2279.600 751.600 ;
            POLYGON 2288.300 751.600  2288.300 755.000  2287.300 755.000  2287.300 805.000  2286.800 805.000  2286.800 811.300  2293.200 811.300  2293.200 805.000  2292.700 805.000  2292.700 755.000  2291.700 755.000  2291.700 751.600 ;
            POLYGON 2300.400 751.600  2300.400 755.000  2299.500 755.000  2299.500 805.000  2300.400 805.000  2300.400 811.300  2309.600 811.300  2309.600 805.000  2310.500 805.000  2310.500 755.000  2309.600 755.000  2309.600 751.600 ;
            POLYGON 2318.300 751.600  2318.300 755.000  2317.300 755.000  2317.300 805.000  2316.800 805.000  2316.800 811.300  2323.200 811.300  2323.200 805.000  2322.700 805.000  2322.700 755.000  2321.700 755.000  2321.700 751.600 ;
            POLYGON 2330.400 751.600  2330.400 755.000  2329.500 755.000  2329.500 805.000  2330.400 805.000  2330.400 811.300  2339.600 811.300  2339.600 805.000  2340.500 805.000  2340.500 755.000  2339.600 755.000  2339.600 751.600 ;
            POLYGON 2348.300 751.600  2348.300 755.000  2347.300 755.000  2347.300 805.000  2346.800 805.000  2346.800 811.300  2353.200 811.300  2353.200 805.000  2352.700 805.000  2352.700 755.000  2351.700 755.000  2351.700 751.600 ;
            POLYGON 2361.800 751.600  2361.800 755.000  2362.300 755.000  2362.300 805.000  2361.800 805.000  2361.800 811.300  2371.000 811.300  2371.000 805.000  2370.500 805.000  2370.500 755.000  2371.000 755.000  2371.000 751.600 ;
            POLYGON 2196.500 742.000  2196.500 818.000  2223.100 818.000  2223.100 821.400  2357.000 821.400  2357.000 818.000  2383.500 818.000  2383.500 742.000 ;
            POLYGON 2209.000 888.700  2209.000 895.000  2209.500 895.000  2209.500 945.000  2209.000 945.000  2209.000 948.400  2218.200 948.400  2218.200 945.000  2217.700 945.000  2217.700 895.000  2218.200 895.000  2218.200 888.700 ;
            POLYGON 2226.800 888.700  2226.800 895.000  2227.300 895.000  2227.300 945.000  2228.400 945.000  2228.400 948.400  2231.800 948.400  2231.800 945.000  2232.700 945.000  2232.700 895.000  2233.200 895.000  2233.200 888.700 ;
            POLYGON 2240.400 888.700  2240.400 895.000  2239.500 895.000  2239.500 945.000  2240.400 945.000  2240.400 948.400  2249.600 948.400  2249.600 945.000  2250.500 945.000  2250.500 895.000  2249.600 895.000  2249.600 888.700 ;
            POLYGON 2256.800 888.700  2256.800 895.000  2257.300 895.000  2257.300 945.000  2258.300 945.000  2258.300 948.400  2261.700 948.400  2261.700 945.000  2262.700 945.000  2262.700 895.000  2263.200 895.000  2263.200 888.700 ;
            POLYGON 2270.400 888.700  2270.400 895.000  2269.500 895.000  2269.500 945.000  2270.400 945.000  2270.400 948.400  2279.600 948.400  2279.600 945.000  2280.500 945.000  2280.500 895.000  2279.600 895.000  2279.600 888.700 ;
            POLYGON 2286.800 888.700  2286.800 895.000  2287.300 895.000  2287.300 945.000  2288.300 945.000  2288.300 948.400  2291.700 948.400  2291.700 945.000  2292.700 945.000  2292.700 895.000  2293.200 895.000  2293.200 888.700 ;
            POLYGON 2300.400 888.700  2300.400 895.000  2299.500 895.000  2299.500 945.000  2300.400 945.000  2300.400 948.400  2309.600 948.400  2309.600 945.000  2310.500 945.000  2310.500 895.000  2309.600 895.000  2309.600 888.700 ;
            POLYGON 2316.800 888.700  2316.800 895.000  2317.300 895.000  2317.300 945.000  2318.300 945.000  2318.300 948.400  2321.700 948.400  2321.700 945.000  2322.700 945.000  2322.700 895.000  2323.200 895.000  2323.200 888.700 ;
            POLYGON 2330.400 888.700  2330.400 895.000  2329.500 895.000  2329.500 945.000  2330.400 945.000  2330.400 948.400  2339.600 948.400  2339.600 945.000  2340.500 945.000  2340.500 895.000  2339.600 895.000  2339.600 888.700 ;
            POLYGON 2346.800 888.700  2346.800 895.000  2347.300 895.000  2347.300 945.000  2348.300 945.000  2348.300 948.400  2351.700 948.400  2351.700 945.000  2352.700 945.000  2352.700 895.000  2353.200 895.000  2353.200 888.700 ;
            POLYGON 2361.800 888.700  2361.800 895.000  2362.300 895.000  2362.300 945.000  2361.800 945.000  2361.800 948.400  2371.000 948.400  2371.000 945.000  2370.500 945.000  2370.500 895.000  2371.000 895.000  2371.000 888.700 ;
            POLYGON 2202.000 946.300  2202.000 951.800  2255.800 951.800  2255.800 946.400  2253.200 946.400  2253.200 950.000  2236.800 950.000  2236.800 946.400  2234.200 946.400  2234.200 950.000  2225.800 950.000  2225.800 946.400  2223.200 946.400  2223.200 950.000  2205.400 950.000  2205.400 946.300 ;
            POLYGON 2223.100 878.600  2223.100 882.000  2196.500 882.000  2196.500 958.000  2383.500 958.000  2383.500 882.000  2357.000 882.000  2357.000 878.600 ;
            POLYGON 2186.400 1012.900  2186.400 1035.400  2184.200 1035.400  2184.200 1038.000  2186.800 1038.000  2186.800 1037.200  2188.200 1037.200  2188.200 1027.900  2192.600 1027.900  2192.600 1028.300  2195.200 1028.300  2195.200 1025.700  2192.600 1025.700  2192.600 1026.100  2188.200 1026.100  2188.200 1017.900  2189.000 1017.900  2189.000 1012.900 ;
            POLYGON 2196.400 992.700  2196.400 1017.900  2197.200 1017.900  2197.200 1035.100  2196.400 1035.100  2196.400 1041.700  2199.000 1041.700  2199.000 996.100  2205.400 996.100  2205.400 992.700 ;
            POLYGON 2288.300 1151.600  2288.300 1155.000  2287.300 1155.000  2287.300 1205.000  2286.800 1205.000  2286.800 1211.300  2293.200 1211.300  2293.200 1205.000  2292.700 1205.000  2292.700 1155.000  2291.700 1155.000  2291.700 1151.600 ;
            POLYGON 2170.000 1028.300  2170.000 1031.700  2172.000 1031.700  2172.000 1043.200  2175.600 1043.200  2175.600 1031.700  2176.200 1031.700  2176.200 1028.300 ;
            POLYGON 2178.400 1013.100  2178.400 1018.000  2179.200 1018.000  2179.200 1040.200  2178.400 1040.200  2178.400 1047.300  2186.300 1047.300  2186.300 1044.700  2181.000 1044.700  2181.000 1013.100 ;
            POLYGON 2178.400 1053.700  2178.400 1056.300  2181.000 1056.300  2181.000 1053.700 ;
            POLYGON 2192.400 1035.100  2192.400 1035.400  2190.400 1035.400  2190.400 1038.000  2192.400 1038.000  2192.400 1040.200  2182.400 1040.200  2182.400 1042.800  2192.400 1042.800  2192.400 1048.700  2177.200 1048.700  2177.200 1048.300  2170.000 1048.300  2170.000 1051.700  2177.200 1051.700  2177.200 1051.300  2192.400 1051.300  2192.400 1058.400  2183.200 1058.400  2183.200 1062.000  2182.400 1062.000  2182.400 1064.600  2185.000 1064.600  2185.000 1060.200  2192.400 1060.200  2192.400 1062.000  2190.400 1062.000  2190.400 1064.600  2192.400 1064.600  2192.400 1064.900  2195.000 1064.900  2195.000 1051.300  2200.000 1051.300  2200.000 1048.700  2195.000 1048.700  2195.000 1035.100 ;
            POLYGON 2172.000 1061.400  2172.000 1068.300  2170.000 1068.300  2170.000 1071.700  2176.200 1071.700  2176.200 1068.300  2175.600 1068.300  2175.600 1061.400 ;
            POLYGON 2186.400 1062.000  2186.400 1064.600  2187.200 1064.600  2187.200 1072.100  2185.000 1072.100  2185.000 1082.900  2184.200 1082.900  2184.200 1091.500  2186.800 1091.500  2186.800 1073.900  2192.600 1073.900  2192.600 1074.300  2195.200 1074.300  2195.200 1071.700  2192.600 1071.700  2192.600 1072.100  2189.000 1072.100  2189.000 1062.000 ;
            POLYGON 2178.400 1062.000  2178.400 1064.600  2179.200 1064.600  2179.200 1094.100  2178.400 1094.100  2178.400 1106.200  2185.400 1106.200  2185.400 1107.000  2188.000 1107.000  2188.000 1104.400  2181.000 1104.400  2181.000 1062.000 ;
            POLYGON 2196.400 1058.300  2196.400 1064.900  2197.200 1064.900  2197.200 1082.100  2196.400 1082.100  2196.400 1107.300  2205.400 1107.300  2205.400 1103.900  2199.000 1103.900  2199.000 1058.300 ;
            POLYGON 2226.000 972.000  2226.000 978.300  2170.000 978.300  2170.000 981.700  2226.000 981.700  2226.000 1012.000  2240.000 1012.000  2240.000 1128.000  2340.000 1128.000  2340.000 972.000 ;
            POLYGON 2202.000 1146.800  2202.000 1153.700  2205.400 1153.700  2205.400 1149.400  2223.200 1149.400  2223.200 1153.600  2225.800 1153.600  2225.800 1149.400  2234.200 1149.400  2234.200 1153.600  2236.800 1153.600  2236.800 1149.400  2253.200 1149.400  2253.200 1153.600  2255.800 1153.600  2255.800 1149.400  2264.200 1149.400  2264.200 1153.600  2266.800 1153.600  2266.800 1149.400  2283.200 1149.400  2283.200 1153.600  2285.800 1153.600  2285.800 1149.400  2294.200 1149.400  2294.200 1153.600  2296.800 1153.600  2296.800 1146.800 ;
            POLYGON 2300.400 1151.600  2300.400 1155.000  2299.500 1155.000  2299.500 1205.000  2300.400 1205.000  2300.400 1211.300  2309.600 1211.300  2309.600 1205.000  2310.500 1205.000  2310.500 1155.000  2309.600 1155.000  2309.600 1151.600 ;
            POLYGON 2318.300 1151.600  2318.300 1155.000  2317.300 1155.000  2317.300 1205.000  2316.800 1205.000  2316.800 1211.300  2323.200 1211.300  2323.200 1205.000  2322.700 1205.000  2322.700 1155.000  2321.700 1155.000  2321.700 1151.600 ;
            POLYGON 2209.000 1151.600  2209.000 1155.000  2209.500 1155.000  2209.500 1205.000  2209.000 1205.000  2209.000 1211.300  2218.200 1211.300  2218.200 1205.000  2217.700 1205.000  2217.700 1155.000  2218.200 1155.000  2218.200 1151.600 ;
            POLYGON 2228.300 1151.600  2228.300 1155.000  2227.300 1155.000  2227.300 1205.000  2226.800 1205.000  2226.800 1211.300  2233.200 1211.300  2233.200 1205.000  2232.700 1205.000  2232.700 1155.000  2231.700 1155.000  2231.700 1151.600 ;
            POLYGON 1605.000 146.800  1605.000 147.300  1555.000 147.300  1555.000 148.300  1551.600 148.300  1551.600 151.700  1555.000 151.700  1555.000 152.700  1605.000 152.700  1605.000 153.200  1611.300 153.200  1611.300 146.800 ;
            POLYGON 1392.700 294.600  1392.700 303.600  1417.900 303.600  1417.900 302.800  1435.100 302.800  1435.100 303.600  1441.700 303.600  1441.700 301.000  1396.100 301.000  1396.100 294.600 ;
            POLYGON 1503.900 294.600  1503.900 301.000  1458.300 301.000  1458.300 303.600  1464.900 303.600  1464.900 302.800  1482.100 302.800  1482.100 303.600  1507.300 303.600  1507.300 294.600 ;
            POLYGON 1792.700 294.600  1792.700 303.600  1817.900 303.600  1817.900 302.800  1835.100 302.800  1835.100 303.600  1841.700 303.600  1841.700 301.000  1796.100 301.000  1796.100 294.600 ;
            POLYGON 1688.700 146.800  1688.700 153.200  1695.000 153.200  1695.000 152.700  1745.000 152.700  1745.000 151.700  1748.400 151.700  1748.400 148.300  1745.000 148.300  1745.000 147.300  1695.000 147.300  1695.000 146.800 ;
            POLYGON 1425.700 304.800  1425.700 307.400  1426.100 307.400  1426.100 313.200  1408.500 313.200  1408.500 315.800  1417.100 315.800  1417.100 315.000  1427.900 315.000  1427.900 312.800  1435.400 312.800  1435.400 313.600  1438.000 313.600  1438.000 311.000  1427.900 311.000  1427.900 307.400  1428.300 307.400  1428.300 304.800 ;
            POLYGON 1471.700 304.800  1471.700 307.400  1472.100 307.400  1472.100 311.800  1462.800 311.800  1462.800 313.200  1462.000 313.200  1462.000 315.800  1464.600 315.800  1464.600 313.600  1487.100 313.600  1487.100 311.000  1482.100 311.000  1482.100 311.800  1473.900 311.800  1473.900 307.400  1474.300 307.400  1474.300 304.800 ;
            POLYGON 1555.000 159.500  1555.000 160.400  1551.600 160.400  1551.600 169.600  1555.000 169.600  1555.000 170.500  1605.000 170.500  1605.000 169.600  1611.300 169.600  1611.300 160.400  1605.000 160.400  1605.000 159.500 ;
            POLYGON 1551.600 129.000  1551.600 138.200  1555.000 138.200  1555.000 137.700  1605.000 137.700  1605.000 138.200  1611.300 138.200  1611.300 129.000  1605.000 129.000  1605.000 129.500  1555.000 129.500  1555.000 129.000 ;
            POLYGON 1695.000 159.500  1695.000 160.400  1688.700 160.400  1688.700 169.600  1695.000 169.600  1695.000 170.500  1745.000 170.500  1745.000 169.600  1748.400 169.600  1748.400 160.400  1745.000 160.400  1745.000 159.500 ;
            POLYGON 1688.700 129.000  1688.700 138.200  1695.000 138.200  1695.000 137.700  1745.000 137.700  1745.000 138.200  1748.400 138.200  1748.400 129.000  1745.000 129.000  1745.000 129.500  1695.000 129.500  1695.000 129.000 ;
            POLYGON 1295.000 249.500  1295.000 250.400  1288.700 250.400  1288.700 259.600  1295.000 259.600  1295.000 260.500  1345.000 260.500  1345.000 259.600  1348.400 259.600  1348.400 250.400  1345.000 250.400  1345.000 249.500 ;
            POLYGON 1288.700 281.800  1288.700 291.000  1295.000 291.000  1295.000 290.500  1345.000 290.500  1345.000 291.000  1348.400 291.000  1348.400 281.800  1345.000 281.800  1345.000 282.300  1295.000 282.300  1295.000 281.800 ;
            POLYGON 1555.000 249.500  1555.000 250.400  1551.600 250.400  1551.600 259.600  1555.000 259.600  1555.000 260.500  1605.000 260.500  1605.000 259.600  1611.300 259.600  1611.300 250.400  1605.000 250.400  1605.000 249.500 ;
            POLYGON 1551.600 281.800  1551.600 291.000  1555.000 291.000  1555.000 290.500  1605.000 290.500  1605.000 291.000  1611.300 291.000  1611.300 281.800  1605.000 281.800  1605.000 282.300  1555.000 282.300  1555.000 281.800 ;
            POLYGON 1688.700 281.800  1688.700 291.000  1695.000 291.000  1695.000 290.500  1745.000 290.500  1745.000 291.000  1748.400 291.000  1748.400 281.800  1745.000 281.800  1745.000 282.300  1695.000 282.300  1695.000 281.800 ;
            POLYGON 1288.700 206.800  1288.700 213.200  1295.000 213.200  1295.000 212.700  1345.000 212.700  1345.000 211.700  1348.400 211.700  1348.400 208.300  1345.000 208.300  1345.000 207.300  1295.000 207.300  1295.000 206.800 ;
            POLYGON 1605.000 206.800  1605.000 207.300  1555.000 207.300  1555.000 208.300  1551.600 208.300  1551.600 211.700  1555.000 211.700  1555.000 212.700  1605.000 212.700  1605.000 213.200  1611.300 213.200  1611.300 206.800 ;
            POLYGON 1825.700 304.800  1825.700 307.400  1826.100 307.400  1826.100 311.800  1817.900 311.800  1817.900 311.000  1812.900 311.000  1812.900 313.600  1835.400 313.600  1835.400 315.800  1838.000 315.800  1838.000 313.200  1837.200 313.200  1837.200 311.800  1827.900 311.800  1827.900 307.400  1828.300 307.400  1828.300 304.800 ;
            POLYGON 1346.400 203.200  1346.400 205.800  1350.600 205.800  1350.600 214.200  1346.400 214.200  1346.400 216.800  1350.600 216.800  1350.600 233.200  1346.400 233.200  1346.400 235.800  1350.600 235.800  1350.600 244.200  1346.400 244.200  1346.400 246.800  1350.600 246.800  1350.600 263.200  1346.400 263.200  1346.400 265.800  1350.600 265.800  1350.600 274.200  1346.400 274.200  1346.400 276.800  1350.600 276.800  1350.600 294.600  1346.300 294.600  1346.300 298.000  1353.200 298.000  1353.200 203.200 ;
            POLYGON 1548.200 244.200  1548.200 298.000  1553.700 298.000  1553.700 294.600  1550.000 294.600  1550.000 276.800  1553.600 276.800  1553.600 274.200  1550.000 274.200  1550.000 265.800  1553.600 265.800  1553.600 263.200  1550.000 263.200  1550.000 246.800  1553.600 246.800  1553.600 244.200 ;
            POLYGON 1295.000 219.500  1295.000 220.400  1288.700 220.400  1288.700 229.600  1295.000 229.600  1295.000 230.500  1345.000 230.500  1345.000 229.600  1348.400 229.600  1348.400 220.400  1345.000 220.400  1345.000 219.500 ;
            POLYGON 1746.400 244.200  1746.400 246.800  1750.000 246.800  1750.000 263.200  1746.400 263.200  1746.400 265.800  1750.000 265.800  1750.000 274.200  1746.400 274.200  1746.400 276.800  1750.000 276.800  1750.000 294.600  1746.300 294.600  1746.300 298.000  1751.800 298.000  1751.800 244.200 ;
            POLYGON 1282.000 116.500  1282.000 143.300  1278.600 143.300  1278.600 277.200  1282.000 277.200  1282.000 308.000  1388.700 308.000  1388.700 319.100  1391.300 319.100  1391.300 309.600  1401.300 309.600  1401.300 317.600  1405.900 317.600  1405.900 309.600  1417.900 309.600  1417.900 305.000  1391.300 305.000  1391.300 293.200  1508.700 293.200  1508.700 305.000  1482.100 305.000  1482.100 309.600  1487.100 309.600  1487.100 307.600  1488.900 307.600  1488.900 315.000  1482.300 315.000  1482.300 317.600  1490.700 317.600  1490.700 307.600  1508.700 307.600  1508.700 319.100  1511.300 319.100  1511.300 291.400  1388.700 291.400  1388.700 300.000  1358.000 300.000  1358.000 116.500 ;
            POLYGON 1688.700 206.800  1688.700 213.200  1695.000 213.200  1695.000 212.700  1745.000 212.700  1745.000 211.700  1748.400 211.700  1748.400 208.300  1745.000 208.300  1745.000 207.300  1695.000 207.300  1695.000 206.800 ;
            POLYGON 1695.000 249.500  1695.000 250.400  1688.700 250.400  1688.700 259.600  1695.000 259.600  1695.000 260.500  1745.000 260.500  1745.000 259.600  1748.400 259.600  1748.400 250.400  1745.000 250.400  1745.000 249.500 ;
            POLYGON 1295.000 189.500  1295.000 190.400  1288.700 190.400  1288.700 199.600  1295.000 199.600  1295.000 200.500  1345.000 200.500  1345.000 199.600  1348.400 199.600  1348.400 190.400  1345.000 190.400  1345.000 189.500 ;
            POLYGON 1555.000 219.500  1555.000 220.400  1551.600 220.400  1551.600 229.600  1555.000 229.600  1555.000 230.500  1605.000 230.500  1605.000 229.600  1611.300 229.600  1611.300 220.400  1605.000 220.400  1605.000 219.500 ;
            POLYGON 1555.000 189.500  1555.000 190.400  1551.600 190.400  1551.600 199.600  1555.000 199.600  1555.000 200.500  1605.000 200.500  1605.000 199.600  1611.300 199.600  1611.300 190.400  1605.000 190.400  1605.000 189.500 ;
            POLYGON 1695.000 219.500  1695.000 220.400  1688.700 220.400  1688.700 229.600  1695.000 229.600  1695.000 230.500  1745.000 230.500  1745.000 229.600  1748.400 229.600  1748.400 220.400  1745.000 220.400  1745.000 219.500 ;
            POLYGON 1695.000 189.500  1695.000 190.400  1688.700 190.400  1688.700 199.600  1695.000 199.600  1695.000 200.500  1745.000 200.500  1745.000 199.600  1748.400 199.600  1748.400 190.400  1745.000 190.400  1745.000 189.500 ;
            POLYGON 1288.700 266.800  1288.700 273.200  1295.000 273.200  1295.000 272.700  1345.000 272.700  1345.000 271.700  1348.400 271.700  1348.400 268.300  1345.000 268.300  1345.000 267.300  1295.000 267.300  1295.000 266.800 ;
            POLYGON 1393.000 312.000  1393.000 314.600  1393.800 314.600  1393.800 321.600  1405.900 321.600  1405.900 320.800  1435.400 320.800  1435.400 321.600  1438.000 321.600  1438.000 319.000  1395.600 319.000  1395.600 312.000 ;
            POLYGON 1605.000 266.800  1605.000 267.300  1555.000 267.300  1555.000 268.200  1551.600 268.200  1551.600 271.600  1555.000 271.600  1555.000 272.700  1605.000 272.700  1605.000 273.200  1611.300 273.200  1611.300 266.800 ;
            POLYGON 1443.700 319.000  1443.700 321.600  1446.300 321.600  1446.300 319.000 ;
            POLYGON 1288.700 236.800  1288.700 243.200  1295.000 243.200  1295.000 242.700  1345.000 242.700  1345.000 241.700  1348.400 241.700  1348.400 238.300  1345.000 238.300  1345.000 237.300  1295.000 237.300  1295.000 236.800 ;
            POLYGON 1452.700 313.700  1452.700 321.600  1459.800 321.600  1459.800 320.800  1482.000 320.800  1482.000 321.600  1486.900 321.600  1486.900 319.000  1455.300 319.000  1455.300 313.700 ;
            POLYGON 1688.700 266.800  1688.700 273.200  1695.000 273.200  1695.000 272.700  1745.000 272.700  1745.000 271.600  1748.400 271.600  1748.400 268.200  1745.000 268.200  1745.000 267.300  1695.000 267.300  1695.000 266.800 ;
            POLYGON 1844.700 313.700  1844.700 319.000  1813.100 319.000  1813.100 321.600  1818.000 321.600  1818.000 320.800  1840.200 320.800  1840.200 321.600  1847.300 321.600  1847.300 313.700 ;
            POLYGON 1605.000 236.800  1605.000 237.300  1555.000 237.300  1555.000 238.300  1551.600 238.300  1551.600 241.700  1555.000 241.700  1555.000 242.700  1605.000 242.700  1605.000 243.200  1611.300 243.200  1611.300 236.800 ;
            POLYGON 1688.700 236.800  1688.700 243.200  1695.000 243.200  1695.000 242.700  1745.000 242.700  1745.000 241.700  1748.400 241.700  1748.400 238.300  1745.000 238.300  1745.000 237.300  1695.000 237.300  1695.000 236.800 ;
            POLYGON 1295.000 159.500  1295.000 160.400  1288.700 160.400  1288.700 169.600  1295.000 169.600  1295.000 170.500  1345.000 170.500  1345.000 169.600  1348.400 169.600  1348.400 160.400  1345.000 160.400  1345.000 159.500 ;
            POLYGON 1288.700 176.800  1288.700 183.200  1295.000 183.200  1295.000 182.700  1345.000 182.700  1345.000 181.700  1348.400 181.700  1348.400 178.300  1345.000 178.300  1345.000 177.300  1295.000 177.300  1295.000 176.800 ;
            POLYGON 1605.000 176.800  1605.000 177.300  1555.000 177.300  1555.000 178.300  1551.600 178.300  1551.600 181.700  1555.000 181.700  1555.000 182.700  1605.000 182.700  1605.000 183.200  1611.300 183.200  1611.300 176.800 ;
            POLYGON 1688.700 176.800  1688.700 183.200  1695.000 183.200  1695.000 182.700  1745.000 182.700  1745.000 181.700  1748.400 181.700  1748.400 178.300  1745.000 178.300  1745.000 177.300  1695.000 177.300  1695.000 176.800 ;
            POLYGON 1428.300 323.800  1428.300 330.000  1431.700 330.000  1431.700 328.000  1438.600 328.000  1438.600 324.400  1431.700 324.400  1431.700 323.800 ;
            POLYGON 1448.700 300.000  1448.700 305.000  1435.100 305.000  1435.100 307.600  1435.400 307.600  1435.400 309.600  1438.000 309.600  1438.000 307.600  1439.800 307.600  1439.800 315.000  1435.400 315.000  1435.400 317.600  1438.000 317.600  1438.000 316.800  1441.600 316.800  1441.600 307.600  1448.700 307.600  1448.700 322.800  1448.300 322.800  1448.300 330.000  1451.700 330.000  1451.700 322.800  1451.300 322.800  1451.300 307.600  1457.200 307.600  1457.200 317.600  1459.800 317.600  1459.800 307.600  1462.000 307.600  1462.000 309.600  1464.600 309.600  1464.600 307.600  1464.900 307.600  1464.900 305.000  1451.300 305.000  1451.300 300.000 ;
            POLYGON 1468.300 323.800  1468.300 324.400  1456.800 324.400  1456.800 328.000  1468.300 328.000  1468.300 330.000  1471.700 330.000  1471.700 323.800 ;
            POLYGON 1372.000 160.000  1372.000 260.000  1488.000 260.000  1488.000 274.000  1518.300 274.000  1518.300 330.000  1521.700 330.000  1521.700 274.000  1528.000 274.000  1528.000 160.000 ;
            POLYGON 1542.000 116.500  1542.000 303.500  1618.000 303.500  1618.000 276.900  1621.400 276.900  1621.400 143.000  1618.000 143.000  1618.000 116.500 ;
            POLYGON 1828.300 323.800  1828.300 330.000  1831.700 330.000  1831.700 328.000  1843.200 328.000  1843.200 324.400  1831.700 324.400  1831.700 323.800 ;
            POLYGON 1288.700 129.000  1288.700 138.200  1295.000 138.200  1295.000 137.700  1345.000 137.700  1345.000 138.200  1348.400 138.200  1348.400 129.000  1345.000 129.000  1345.000 129.500  1295.000 129.500  1295.000 129.000 ;
            POLYGON 1682.000 116.500  1682.000 143.000  1678.600 143.000  1678.600 276.900  1682.000 276.900  1682.000 303.500  1758.000 303.500  1758.000 116.500 ;
            POLYGON 1288.700 146.800  1288.700 153.200  1295.000 153.200  1295.000 152.700  1345.000 152.700  1345.000 151.800  1348.400 151.800  1348.400 148.400  1345.000 148.400  1345.000 147.300  1295.000 147.300  1295.000 146.800 ;
            POLYGON 1955.000 159.500  1955.000 160.400  1951.600 160.400  1951.600 169.600  1955.000 169.600  1955.000 170.500  2005.000 170.500  2005.000 169.600  2011.300 169.600  2011.300 160.400  2005.000 160.400  2005.000 159.500 ;
            POLYGON 2202.000 546.300  2202.000 553.200  2296.800 553.200  2296.800 546.400  2294.200 546.400  2294.200 550.600  2285.800 550.600  2285.800 546.400  2283.200 546.400  2283.200 550.600  2266.800 550.600  2266.800 546.400  2264.200 546.400  2264.200 550.600  2255.800 550.600  2255.800 546.400  2253.200 546.400  2253.200 550.600  2236.800 550.600  2236.800 546.400  2234.200 546.400  2234.200 550.600  2225.800 550.600  2225.800 546.400  2223.200 546.400  2223.200 550.600  2205.400 550.600  2205.400 546.300 ;
            POLYGON 2005.000 236.800  2005.000 237.300  1955.000 237.300  1955.000 238.300  1951.600 238.300  1951.600 241.700  1955.000 241.700  1955.000 242.700  2005.000 242.700  2005.000 243.200  2011.300 243.200  2011.300 236.800 ;
            POLYGON 1868.300 323.800  1868.300 324.400  1861.400 324.400  1861.400 328.000  1868.300 328.000  1868.300 330.000  1871.700 330.000  1871.700 323.800 ;
            POLYGON 2185.400 593.000  2185.400 593.800  2178.400 593.800  2178.400 605.900  2179.200 605.900  2179.200 635.400  2178.400 635.400  2178.400 638.000  2181.000 638.000  2181.000 595.600  2188.000 595.600  2188.000 593.000 ;
            POLYGON 2184.200 608.500  2184.200 617.100  2185.000 617.100  2185.000 627.900  2187.200 627.900  2187.200 635.400  2186.400 635.400  2186.400 638.000  2189.000 638.000  2189.000 627.900  2192.600 627.900  2192.600 628.300  2195.200 628.300  2195.200 625.700  2192.600 625.700  2192.600 626.100  2186.800 626.100  2186.800 608.500 ;
            POLYGON 1951.600 281.800  1951.600 291.000  1955.000 291.000  1955.000 290.500  2005.000 290.500  2005.000 291.000  2011.300 291.000  2011.300 281.800  2005.000 281.800  2005.000 282.300  1955.000 282.300  1955.000 281.800 ;
            POLYGON 1955.000 219.500  1955.000 220.400  1951.600 220.400  1951.600 229.600  1955.000 229.600  1955.000 230.500  2005.000 230.500  2005.000 229.600  2011.300 229.600  2011.300 220.400  2005.000 220.400  2005.000 219.500 ;
            POLYGON 1903.900 294.600  1903.900 301.000  1858.300 301.000  1858.300 303.600  1864.900 303.600  1864.900 302.800  1882.100 302.800  1882.100 303.600  1907.300 303.600  1907.300 294.600 ;
            POLYGON 1951.600 129.000  1951.600 138.200  1955.000 138.200  1955.000 137.700  2005.000 137.700  2005.000 138.200  2011.300 138.200  2011.300 129.000  2005.000 129.000  2005.000 129.500  1955.000 129.500  1955.000 129.000 ;
            POLYGON 2005.000 146.800  2005.000 147.300  1955.000 147.300  1955.000 148.400  1951.600 148.400  1951.600 151.800  1955.000 151.800  1955.000 152.700  2005.000 152.700  2005.000 153.200  2011.300 153.200  2011.300 146.800 ;
            POLYGON 2170.000 628.300  2170.000 631.700  2172.000 631.700  2172.000 638.600  2175.600 638.600  2175.600 631.700  2176.200 631.700  2176.200 628.300 ;
            POLYGON 1955.000 189.500  1955.000 190.400  1951.600 190.400  1951.600 199.600  1955.000 199.600  1955.000 200.500  2005.000 200.500  2005.000 199.600  2011.300 199.600  2011.300 190.400  2005.000 190.400  2005.000 189.500 ;
            POLYGON 2196.400 592.700  2196.400 617.900  2197.200 617.900  2197.200 635.100  2196.400 635.100  2196.400 641.700  2199.000 641.700  2199.000 596.100  2205.400 596.100  2205.400 592.700 ;
            POLYGON 2209.000 488.700  2209.000 495.000  2209.500 495.000  2209.500 545.000  2209.000 545.000  2209.000 548.400  2218.200 548.400  2218.200 545.000  2217.700 545.000  2217.700 495.000  2218.200 495.000  2218.200 488.700 ;
            POLYGON 1946.800 203.200  1946.800 298.000  1953.700 298.000  1953.700 294.600  1949.400 294.600  1949.400 276.800  1953.600 276.800  1953.600 274.200  1949.400 274.200  1949.400 265.800  1953.600 265.800  1953.600 263.200  1949.400 263.200  1949.400 246.800  1953.600 246.800  1953.600 244.200  1949.400 244.200  1949.400 235.800  1953.600 235.800  1953.600 233.200  1949.400 233.200  1949.400 216.800  1953.600 216.800  1953.600 214.200  1949.400 214.200  1949.400 205.800  1953.600 205.800  1953.600 203.200 ;
            POLYGON 2178.400 643.700  2178.400 646.300  2181.000 646.300  2181.000 643.700 ;
            POLYGON 1853.700 319.000  1853.700 321.600  1856.300 321.600  1856.300 319.000 ;
            POLYGON 2005.000 206.800  2005.000 207.300  1955.000 207.300  1955.000 208.300  1951.600 208.300  1951.600 211.700  1955.000 211.700  1955.000 212.700  2005.000 212.700  2005.000 213.200  2011.300 213.200  2011.300 206.800 ;
            POLYGON 1904.400 312.000  1904.400 319.000  1862.000 319.000  1862.000 321.600  1864.600 321.600  1864.600 320.800  1894.100 320.800  1894.100 321.600  1906.200 321.600  1906.200 314.600  1907.000 314.600  1907.000 312.000 ;
            POLYGON 2226.800 488.700  2226.800 495.000  2227.300 495.000  2227.300 545.000  2228.300 545.000  2228.300 548.400  2231.700 548.400  2231.700 545.000  2232.700 545.000  2232.700 495.000  2233.200 495.000  2233.200 488.700 ;
            POLYGON 2240.400 488.700  2240.400 495.000  2239.500 495.000  2239.500 545.000  2240.400 545.000  2240.400 548.400  2249.600 548.400  2249.600 545.000  2250.500 545.000  2250.500 495.000  2249.600 495.000  2249.600 488.700 ;
            POLYGON 2256.800 488.700  2256.800 495.000  2257.300 495.000  2257.300 545.000  2258.300 545.000  2258.300 548.400  2261.700 548.400  2261.700 545.000  2262.700 545.000  2262.700 495.000  2263.200 495.000  2263.200 488.700 ;
            POLYGON 2270.400 488.700  2270.400 495.000  2269.500 495.000  2269.500 545.000  2270.400 545.000  2270.400 548.400  2279.600 548.400  2279.600 545.000  2280.500 545.000  2280.500 495.000  2279.600 495.000  2279.600 488.700 ;
            POLYGON 2005.000 176.800  2005.000 177.300  1955.000 177.300  1955.000 178.300  1951.600 178.300  1951.600 181.700  1955.000 181.700  1955.000 182.700  2005.000 182.700  2005.000 183.200  2011.300 183.200  2011.300 176.800 ;
            POLYGON 2005.000 266.800  2005.000 267.300  1955.000 267.300  1955.000 268.300  1951.600 268.300  1951.600 271.700  1955.000 271.700  1955.000 272.700  2005.000 272.700  2005.000 273.200  2011.300 273.200  2011.300 266.800 ;
            POLYGON 2286.800 488.700  2286.800 495.000  2287.300 495.000  2287.300 545.000  2288.300 545.000  2288.300 548.400  2291.700 548.400  2291.700 545.000  2292.700 545.000  2292.700 495.000  2293.200 495.000  2293.200 488.700 ;
            POLYGON 2300.400 488.700  2300.400 495.000  2299.500 495.000  2299.500 545.000  2300.400 545.000  2300.400 548.400  2309.600 548.400  2309.600 545.000  2310.500 545.000  2310.500 495.000  2309.600 495.000  2309.600 488.700 ;
            POLYGON 2316.800 488.700  2316.800 495.000  2317.300 495.000  2317.300 545.000  2318.300 545.000  2318.300 548.400  2321.700 548.400  2321.700 545.000  2322.700 545.000  2322.700 495.000  2323.200 495.000  2323.200 488.700 ;
            POLYGON 1871.700 304.800  1871.700 307.400  1872.100 307.400  1872.100 311.000  1862.000 311.000  1862.000 313.600  1864.600 313.600  1864.600 312.800  1872.100 312.800  1872.100 315.000  1882.900 315.000  1882.900 315.800  1891.500 315.800  1891.500 313.200  1873.900 313.200  1873.900 307.400  1874.300 307.400  1874.300 304.800 ;
            POLYGON 2330.400 488.700  2330.400 495.000  2329.500 495.000  2329.500 545.000  2330.400 545.000  2330.400 548.400  2339.600 548.400  2339.600 545.000  2340.500 545.000  2340.500 495.000  2339.600 495.000  2339.600 488.700 ;
            POLYGON 2346.800 488.700  2346.800 495.000  2347.300 495.000  2347.300 545.000  2348.200 545.000  2348.200 548.400  2351.600 548.400  2351.600 545.000  2352.700 545.000  2352.700 495.000  2353.200 495.000  2353.200 488.700 ;
            POLYGON 2361.800 488.700  2361.800 495.000  2362.300 495.000  2362.300 545.000  2361.800 545.000  2361.800 548.400  2371.000 548.400  2371.000 545.000  2370.500 545.000  2370.500 495.000  2371.000 495.000  2371.000 488.700 ;
            POLYGON 1955.000 249.500  1955.000 250.400  1951.600 250.400  1951.600 259.600  1955.000 259.600  1955.000 260.500  2005.000 260.500  2005.000 259.600  2011.300 259.600  2011.300 250.400  2005.000 250.400  2005.000 249.500 ;
        LAYER M2 ;
            POLYGON 488.700 129.000  488.700 138.200  567.000 138.200  567.000 160.400  488.700 160.400  488.700 169.600  567.000 169.600  567.000 190.400  488.700 190.400  488.700 199.600  567.000 199.600  567.000 220.400  488.700 220.400  488.700 229.600  567.000 229.600  567.000 250.400  488.700 250.400  488.700 259.600  567.000 259.600  567.000 281.800  488.700 281.800  488.700 291.000  576.200 291.000  576.200 260.000  724.800 260.000  724.800 291.000  811.300 291.000  811.300 281.800  734.000 281.800  734.000 259.600  811.300 259.600  811.300 250.400  734.000 250.400  734.000 229.600  811.300 229.600  811.300 220.400  734.000 220.400  734.000 199.600  811.300 199.600  811.300 190.400  734.000 190.400  734.000 169.600  811.300 169.600  811.300 160.400  734.000 160.400  734.000 138.200  811.300 138.200  811.300 129.000  724.800 129.000  724.800 160.000  576.200 160.000  576.200 129.000 ;
            POLYGON 1288.700 129.000  1288.700 138.200  1367.000 138.200  1367.000 160.400  1288.700 160.400  1288.700 169.600  1367.000 169.600  1367.000 190.400  1288.700 190.400  1288.700 199.600  1367.000 199.600  1367.000 220.400  1288.700 220.400  1288.700 229.600  1367.000 229.600  1367.000 250.400  1288.700 250.400  1288.700 259.600  1367.000 259.600  1367.000 281.800  1288.700 281.800  1288.700 291.000  1376.200 291.000  1376.200 260.000  1524.800 260.000  1524.800 291.000  1611.300 291.000  1611.300 281.800  1534.000 281.800  1534.000 259.600  1611.300 259.600  1611.300 250.400  1534.000 250.400  1534.000 229.600  1611.300 229.600  1611.300 220.400  1534.000 220.400  1534.000 199.600  1611.300 199.600  1611.300 190.400  1534.000 190.400  1534.000 169.600  1611.300 169.600  1611.300 160.400  1534.000 160.400  1534.000 138.200  1611.300 138.200  1611.300 129.000  1524.800 129.000  1524.800 160.000  1376.200 160.000  1376.200 129.000 ;
            POLYGON 1688.700 129.000  1688.700 138.200  1766.000 138.200  1766.000 160.400  1688.700 160.400  1688.700 169.600  1766.000 169.600  1766.000 190.400  1688.700 190.400  1688.700 199.600  1766.000 199.600  1766.000 220.400  1688.700 220.400  1688.700 229.600  1766.000 229.600  1766.000 250.400  1688.700 250.400  1688.700 259.600  1766.000 259.600  1766.000 281.800  1688.700 281.800  1688.700 291.000  1775.200 291.000  1775.200 260.000  1923.800 260.000  1923.800 291.000  2011.300 291.000  2011.300 281.800  1933.000 281.800  1933.000 259.600  2011.300 259.600  2011.300 250.400  1933.000 250.400  1933.000 229.600  2011.300 229.600  2011.300 220.400  1933.000 220.400  1933.000 199.600  2011.300 199.600  2011.300 190.400  1933.000 190.400  1933.000 169.600  2011.300 169.600  2011.300 160.400  1933.000 160.400  1933.000 138.200  2011.300 138.200  2011.300 129.000  1923.800 129.000  1923.800 160.000  1775.200 160.000  1775.200 129.000 ;
            POLYGON 546.300 294.600  546.300 298.000  549.700 298.000  549.700 297.800  592.700 297.800  592.700 298.000  596.100 298.000  596.100 294.600  592.700 294.600  592.700 294.800  549.700 294.800  549.700 294.600 ;
            POLYGON 703.900 294.600  703.900 298.000  707.300 298.000  707.300 297.800  750.300 297.800  750.300 298.000  753.700 298.000  753.700 294.600  750.300 294.600  750.300 294.800  707.300 294.800  707.300 294.600 ;
            POLYGON 1346.300 294.600  1346.300 298.000  1349.700 298.000  1349.700 297.800  1392.700 297.800  1392.700 298.000  1396.100 298.000  1396.100 294.600  1392.700 294.600  1392.700 294.800  1349.700 294.800  1349.700 294.600 ;
            POLYGON 1503.900 294.600  1503.900 298.000  1507.300 298.000  1507.300 297.800  1550.300 297.800  1550.300 298.000  1553.700 298.000  1553.700 294.600  1550.300 294.600  1550.300 294.800  1507.300 294.800  1507.300 294.600 ;
            POLYGON 1746.300 294.600  1746.300 298.000  1749.700 298.000  1749.700 297.800  1792.700 297.800  1792.700 298.000  1796.100 298.000  1796.100 294.600  1792.700 294.600  1792.700 294.800  1749.700 294.800  1749.700 294.600 ;
            POLYGON 1903.900 294.600  1903.900 298.000  1907.300 298.000  1907.300 297.800  1950.300 297.800  1950.300 298.000  1953.700 298.000  1953.700 294.600  1950.300 294.600  1950.300 294.800  1907.300 294.800  1907.300 294.600 ;
            POLYGON 126.000 126.000  126.000 306.000  266.000 306.000  275.364 305.078  284.369 302.346  290.000 299.336  292.667 297.910  299.941 291.941  305.910 284.667  310.346 276.369  313.078 267.364  314.000 258.000  313.078 248.636  310.346 239.631  306.000 231.501  306.000 231.180  300.058 223.942  292.760 217.951  285.780 214.220  286.800 213.200  286.799 213.200  306.000 194.000  306.000 126.000  242.000 126.000  222.000 146.000  222.000 126.000 ;
            POLYGON 294.600 546.300  294.600 549.700  294.800 549.700  294.800 592.700  294.600 592.700  294.600 596.100  298.000 596.100  298.000 592.700  297.800 592.700  297.800 549.700  298.000 549.700  298.000 546.300 ;
            POLYGON 2202.000 546.300  2202.000 549.700  2202.200 549.700  2202.200 592.700  2202.000 592.700  2202.000 596.100  2205.400 596.100  2205.400 592.700  2205.200 592.700  2205.200 549.700  2205.400 549.700  2205.400 546.300 ;
            POLYGON 294.600 703.900  294.600 707.300  294.800 707.300  294.800 750.300  294.600 750.300  294.600 753.700  298.000 753.700  298.000 750.300  297.800 750.300  297.800 707.300  298.000 707.300  298.000 703.900 ;
            POLYGON 2202.000 703.900  2202.000 707.300  2202.200 707.300  2202.200 750.300  2202.000 750.300  2202.000 753.700  2205.400 753.700  2205.400 750.300  2205.200 750.300  2205.200 707.300  2205.400 707.300  2205.400 703.900 ;
            POLYGON 129.000 488.700  129.000 576.200  160.000 576.200  160.000 724.800  129.000 724.800  129.000 811.300  138.200 811.300  138.200 734.000  160.400 734.000  160.400 811.300  169.600 811.300  169.600 734.000  190.400 734.000  190.400 811.300  199.600 811.300  199.600 734.000  220.400 734.000  220.400 811.300  229.600 811.300  229.600 734.000  250.400 734.000  250.400 811.300  259.600 811.300  259.600 734.000  281.800 734.000  281.800 811.300  291.000 811.300  291.000 724.800  260.000 724.800  260.000 576.200  291.000 576.200  291.000 488.700  281.800 488.700  281.800 567.000  259.600 567.000  259.600 488.700  250.400 488.700  250.400 567.000  229.600 567.000  229.600 488.700  220.400 488.700  220.400 567.000  199.600 567.000  199.600 488.700  190.400 488.700  190.400 567.000  169.600 567.000  169.600 488.700  160.400 488.700  160.400 567.000  138.200 567.000  138.200 488.700 ;
            POLYGON 2209.000 488.700  2209.000 576.200  2240.000 576.200  2240.000 724.800  2209.000 724.800  2209.000 811.300  2218.200 811.300  2218.200 734.000  2240.400 734.000  2240.400 811.300  2249.600 811.300  2249.600 734.000  2270.400 734.000  2270.400 811.300  2279.600 811.300  2279.600 734.000  2300.400 734.000  2300.400 811.300  2309.600 811.300  2309.600 734.000  2330.400 734.000  2330.400 811.300  2339.600 811.300  2339.600 734.000  2361.800 734.000  2361.800 811.300  2371.000 811.300  2371.000 724.800  2340.000 724.800  2340.000 576.200  2371.000 576.200  2371.000 488.700  2361.800 488.700  2361.800 567.000  2339.600 567.000  2339.600 488.700  2330.400 488.700  2330.400 567.000  2309.600 567.000  2309.600 488.700  2300.400 488.700  2300.400 567.000  2279.600 567.000  2279.600 488.700  2270.400 488.700  2270.400 567.000  2249.600 567.000  2249.600 488.700  2240.400 488.700  2240.400 567.000  2218.200 567.000  2218.200 488.700 ;
            POLYGON 294.600 946.300  294.600 949.700  294.800 949.700  294.800 992.700  294.600 992.700  294.600 996.100  298.000 996.100  298.000 992.700  297.800 992.700  297.800 949.700  298.000 949.700  298.000 946.300 ;
            POLYGON 2202.000 946.300  2202.000 949.700  2202.200 949.700  2202.200 992.700  2202.000 992.700  2202.000 996.100  2205.400 996.100  2205.400 992.700  2205.200 992.700  2205.200 949.700  2205.400 949.700  2205.400 946.300 ;
            POLYGON 294.600 1103.900  294.600 1107.300  294.800 1107.300  294.800 1150.300  294.600 1150.300  294.600 1153.700  298.000 1153.700  298.000 1150.300  297.800 1150.300  297.800 1107.300  298.000 1107.300  298.000 1103.900 ;
            POLYGON 2202.000 1103.900  2202.000 1107.300  2202.200 1107.300  2202.200 1150.300  2202.000 1150.300  2202.000 1153.700  2205.400 1153.700  2205.400 1150.300  2205.200 1150.300  2205.200 1107.300  2205.400 1107.300  2205.400 1103.900 ;
            POLYGON 129.000 888.700  129.000 975.200  160.000 975.200  160.000 1123.800  129.000 1123.800  129.000 1211.300  138.200 1211.300  138.200 1133.000  160.400 1133.000  160.400 1211.300  169.600 1211.300  169.600 1133.000  190.400 1133.000  190.400 1211.300  199.600 1211.300  199.600 1133.000  220.400 1133.000  220.400 1211.300  229.600 1211.300  229.600 1133.000  250.400 1133.000  250.400 1211.300  259.600 1211.300  259.600 1133.000  281.800 1133.000  281.800 1211.300  291.000 1211.300  291.000 1123.800  260.000 1123.800  260.000 975.200  291.000 975.200  291.000 888.700  281.800 888.700  281.800 966.000  259.600 966.000  259.600 888.700  250.400 888.700  250.400 966.000  229.600 966.000  229.600 888.700  220.400 888.700  220.400 966.000  199.600 966.000  199.600 888.700  190.400 888.700  190.400 966.000  169.600 966.000  169.600 888.700  160.400 888.700  160.400 966.000  138.200 966.000  138.200 888.700 ;
            POLYGON 2209.000 888.700  2209.000 975.200  2240.000 975.200  2240.000 1123.800  2209.000 1123.800  2209.000 1211.300  2218.200 1211.300  2218.200 1133.000  2240.400 1133.000  2240.400 1211.300  2249.600 1211.300  2249.600 1133.000  2270.400 1133.000  2270.400 1211.300  2279.600 1211.300  2279.600 1133.000  2300.400 1133.000  2300.400 1211.300  2309.600 1211.300  2309.600 1133.000  2330.400 1133.000  2330.400 1211.300  2339.600 1211.300  2339.600 1133.000  2361.800 1133.000  2361.800 1211.300  2371.000 1211.300  2371.000 1123.800  2340.000 1123.800  2340.000 975.200  2371.000 975.200  2371.000 888.700  2361.800 888.700  2361.800 966.000  2339.600 966.000  2339.600 888.700  2330.400 888.700  2330.400 966.000  2309.600 966.000  2309.600 888.700  2300.400 888.700  2300.400 966.000  2279.600 966.000  2279.600 888.700  2270.400 888.700  2270.400 966.000  2249.600 966.000  2249.600 888.700  2240.400 888.700  2240.400 966.000  2218.200 966.000  2218.200 888.700 ;
            POLYGON 294.600 1346.300  294.600 1349.700  294.800 1349.700  294.800 1392.700  294.600 1392.700  294.600 1396.100  298.000 1396.100  298.000 1392.700  297.800 1392.700  297.800 1349.700  298.000 1349.700  298.000 1346.300 ;
            POLYGON 2202.000 1346.300  2202.000 1349.700  2202.200 1349.700  2202.200 1392.700  2202.000 1392.700  2202.000 1396.100  2205.400 1396.100  2205.400 1392.700  2205.200 1392.700  2205.200 1349.700  2205.400 1349.700  2205.400 1346.300 ;
            POLYGON 294.600 1503.900  294.600 1507.300  294.800 1507.300  294.800 1550.300  294.600 1550.300  294.600 1553.700  298.000 1553.700  298.000 1550.300  297.800 1550.300  297.800 1507.300  298.000 1507.300  298.000 1503.900 ;
            POLYGON 2202.000 1503.900  2202.000 1507.300  2202.200 1507.300  2202.200 1550.300  2202.000 1550.300  2202.000 1553.700  2205.400 1553.700  2205.400 1550.300  2205.200 1550.300  2205.200 1507.300  2205.400 1507.300  2205.400 1503.900 ;
            POLYGON 129.000 1288.700  129.000 1376.200  160.000 1376.200  160.000 1524.800  129.000 1524.800  129.000 1611.300  138.200 1611.300  138.200 1534.000  160.400 1534.000  160.400 1611.300  169.600 1611.300  169.600 1534.000  190.400 1534.000  190.400 1611.300  199.600 1611.300  199.600 1534.000  220.400 1534.000  220.400 1611.300  229.600 1611.300  229.600 1534.000  250.400 1534.000  250.400 1611.300  259.600 1611.300  259.600 1534.000  281.800 1534.000  281.800 1611.300  291.000 1611.300  291.000 1524.800  260.000 1524.800  260.000 1376.200  291.000 1376.200  291.000 1288.700  281.800 1288.700  281.800 1367.000  259.600 1367.000  259.600 1288.700  250.400 1288.700  250.400 1367.000  229.600 1367.000  229.600 1288.700  220.400 1288.700  220.400 1367.000  199.600 1367.000  199.600 1288.700  190.400 1288.700  190.400 1367.000  169.600 1367.000  169.600 1288.700  160.400 1288.700  160.400 1367.000  138.200 1367.000  138.200 1288.700 ;
            POLYGON 2209.000 1288.700  2209.000 1376.200  2240.000 1376.200  2240.000 1524.800  2209.000 1524.800  2209.000 1611.300  2218.200 1611.300  2218.200 1534.000  2240.400 1534.000  2240.400 1611.300  2249.600 1611.300  2249.600 1534.000  2270.400 1534.000  2270.400 1611.300  2279.600 1611.300  2279.600 1534.000  2300.400 1534.000  2300.400 1611.300  2309.600 1611.300  2309.600 1534.000  2330.400 1534.000  2330.400 1611.300  2339.600 1611.300  2339.600 1534.000  2361.800 1534.000  2361.800 1611.300  2371.000 1611.300  2371.000 1524.800  2340.000 1524.800  2340.000 1376.200  2371.000 1376.200  2371.000 1288.700  2361.800 1288.700  2361.800 1367.000  2339.600 1367.000  2339.600 1288.700  2330.400 1288.700  2330.400 1367.000  2309.600 1367.000  2309.600 1288.700  2300.400 1288.700  2300.400 1367.000  2279.600 1367.000  2279.600 1288.700  2270.400 1288.700  2270.400 1367.000  2249.600 1367.000  2249.600 1288.700  2240.400 1288.700  2240.400 1367.000  2218.200 1367.000  2218.200 1288.700 ;
            POLYGON 294.600 1746.300  294.600 1749.700  294.800 1749.700  294.800 1792.700  294.600 1792.700  294.600 1796.100  298.000 1796.100  298.000 1792.700  297.800 1792.700  297.800 1749.700  298.000 1749.700  298.000 1746.300 ;
            POLYGON 2202.000 1746.300  2202.000 1749.700  2202.200 1749.700  2202.200 1792.700  2202.000 1792.700  2202.000 1796.100  2205.400 1796.100  2205.400 1792.700  2205.200 1792.700  2205.200 1749.700  2205.400 1749.700  2205.400 1746.300 ;
            POLYGON 294.600 1903.900  294.600 1907.300  294.800 1907.300  294.800 1950.300  294.600 1950.300  294.600 1953.700  298.000 1953.700  298.000 1950.300  297.800 1950.300  297.800 1907.300  298.000 1907.300  298.000 1903.900 ;
            POLYGON 2202.000 1903.900  2202.000 1907.300  2202.200 1907.300  2202.200 1950.300  2202.000 1950.300  2202.000 1953.700  2205.400 1953.700  2205.400 1950.300  2205.200 1950.300  2205.200 1907.300  2205.400 1907.300  2205.400 1903.900 ;
            POLYGON 129.000 1688.700  129.000 1775.200  160.000 1775.200  160.000 1923.800  129.000 1923.800  129.000 2011.300  138.200 2011.300  138.200 1933.000  160.400 1933.000  160.400 2011.300  169.600 2011.300  169.600 1933.000  190.400 1933.000  190.400 2011.300  199.600 2011.300  199.600 1933.000  220.400 1933.000  220.400 2011.300  229.600 2011.300  229.600 1933.000  250.400 1933.000  250.400 2011.300  259.600 2011.300  259.600 1933.000  281.800 1933.000  281.800 2011.300  291.000 2011.300  291.000 1923.800  260.000 1923.800  260.000 1775.200  291.000 1775.200  291.000 1688.700  281.800 1688.700  281.800 1766.000  259.600 1766.000  259.600 1688.700  250.400 1688.700  250.400 1766.000  229.600 1766.000  229.600 1688.700  220.400 1688.700  220.400 1766.000  199.600 1766.000  199.600 1688.700  190.400 1688.700  190.400 1766.000  169.600 1766.000  169.600 1688.700  160.400 1688.700  160.400 1766.000  138.200 1766.000  138.200 1688.700 ;
            POLYGON 2209.000 1688.700  2209.000 1775.200  2240.000 1775.200  2240.000 1923.800  2209.000 1923.800  2209.000 2011.300  2218.200 2011.300  2218.200 1933.000  2240.400 1933.000  2240.400 2011.300  2249.600 2011.300  2249.600 1933.000  2270.400 1933.000  2270.400 2011.300  2279.600 2011.300  2279.600 1933.000  2300.400 1933.000  2300.400 2011.300  2309.600 2011.300  2309.600 1933.000  2330.400 1933.000  2330.400 2011.300  2339.600 2011.300  2339.600 1933.000  2361.800 1933.000  2361.800 2011.300  2371.000 2011.300  2371.000 1923.800  2340.000 1923.800  2340.000 1775.200  2371.000 1775.200  2371.000 1688.700  2361.800 1688.700  2361.800 1766.000  2339.600 1766.000  2339.600 1688.700  2330.400 1688.700  2330.400 1766.000  2309.600 1766.000  2309.600 1688.700  2300.400 1688.700  2300.400 1766.000  2279.600 1766.000  2279.600 1688.700  2270.400 1688.700  2270.400 1766.000  2249.600 1766.000  2249.600 1688.700  2240.400 1688.700  2240.400 1766.000  2218.200 1766.000  2218.200 1688.700 ;
            POLYGON 546.300 2202.000  546.300 2205.400  549.700 2205.400  549.700 2205.200  592.700 2205.200  592.700 2205.400  596.100 2205.400  596.100 2202.000  592.700 2202.000  592.700 2202.200  549.700 2202.200  549.700 2202.000 ;
            POLYGON 703.900 2202.000  703.900 2205.400  707.300 2205.400  707.300 2205.200  750.300 2205.200  750.300 2205.400  753.700 2205.400  753.700 2202.000  750.300 2202.000  750.300 2202.200  707.300 2202.200  707.300 2202.000 ;
            POLYGON 946.300 2202.000  946.300 2205.400  949.700 2205.400  949.700 2205.200  992.700 2205.200  992.700 2205.400  996.100 2205.400  996.100 2202.000  992.700 2202.000  992.700 2202.200  949.700 2202.200  949.700 2202.000 ;
            POLYGON 1103.900 2202.000  1103.900 2205.400  1107.300 2205.400  1107.300 2205.200  1150.300 2205.200  1150.300 2205.400  1153.700 2205.400  1153.700 2202.000  1150.300 2202.000  1150.300 2202.200  1107.300 2202.200  1107.300 2202.000 ;
            POLYGON 1746.300 2202.000  1746.300 2205.400  1749.700 2205.400  1749.700 2205.200  1792.700 2205.200  1792.700 2205.400  1796.100 2205.400  1796.100 2202.000  1792.700 2202.000  1792.700 2202.200  1749.700 2202.200  1749.700 2202.000 ;
            POLYGON 1903.900 2202.000  1903.900 2205.400  1907.300 2205.400  1907.300 2205.200  1950.300 2205.200  1950.300 2205.400  1953.700 2205.400  1953.700 2202.000  1950.300 2202.000  1950.300 2202.200  1907.300 2202.200  1907.300 2202.000 ;
            POLYGON 488.700 2209.000  488.700 2218.200  567.000 2218.200  567.000 2240.400  488.700 2240.400  488.700 2249.600  567.000 2249.600  567.000 2270.400  488.700 2270.400  488.700 2279.600  567.000 2279.600  567.000 2300.400  488.700 2300.400  488.700 2309.600  567.000 2309.600  567.000 2330.400  488.700 2330.400  488.700 2339.600  567.000 2339.600  567.000 2361.800  488.700 2361.800  488.700 2371.000  576.200 2371.000  576.200 2340.000  724.800 2340.000  724.800 2371.000  811.300 2371.000  811.300 2361.800  734.000 2361.800  734.000 2339.600  811.300 2339.600  811.300 2330.400  734.000 2330.400  734.000 2309.600  811.300 2309.600  811.300 2300.400  734.000 2300.400  734.000 2279.600  811.300 2279.600  811.300 2270.400  734.000 2270.400  734.000 2249.600  811.300 2249.600  811.300 2240.400  734.000 2240.400  734.000 2218.200  811.300 2218.200  811.300 2209.000  724.800 2209.000  724.800 2240.000  576.200 2240.000  576.200 2209.000 ;
            POLYGON 888.700 2209.000  888.700 2218.200  966.000 2218.200  966.000 2240.400  888.700 2240.400  888.700 2249.600  966.000 2249.600  966.000 2270.400  888.700 2270.400  888.700 2279.600  966.000 2279.600  966.000 2300.400  888.700 2300.400  888.700 2309.600  966.000 2309.600  966.000 2330.400  888.700 2330.400  888.700 2339.600  966.000 2339.600  966.000 2361.800  888.700 2361.800  888.700 2371.000  975.200 2371.000  975.200 2340.000  1123.800 2340.000  1123.800 2371.000  1211.300 2371.000  1211.300 2361.800  1133.000 2361.800  1133.000 2339.600  1211.300 2339.600  1211.300 2330.400  1133.000 2330.400  1133.000 2309.600  1211.300 2309.600  1211.300 2300.400  1133.000 2300.400  1133.000 2279.600  1211.300 2279.600  1211.300 2270.400  1133.000 2270.400  1133.000 2249.600  1211.300 2249.600  1211.300 2240.400  1133.000 2240.400  1133.000 2218.200  1211.300 2218.200  1211.300 2209.000  1123.800 2209.000  1123.800 2240.000  975.200 2240.000  975.200 2209.000 ;
            POLYGON 1123.800 129.000  1123.800 160.000  970.000 160.000  970.000 143.100  958.000 143.100  958.000 145.400  891.600 145.400  891.600 154.600  958.000 154.600  958.000 175.400  891.600 175.400  891.600 184.600  958.000 184.600  958.000 205.400  891.600 205.400  891.600 214.600  958.000 214.600  958.000 235.400  891.600 235.400  891.600 244.600  958.000 244.600  958.000 265.400  891.600 265.400  891.600 274.600  958.000 274.600  958.000 277.000  970.000 277.000  970.000 260.000  1000.000 260.000  1000.000 300.000  845.000 300.000  845.000 143.000  818.000 143.000  818.000 145.400  751.600 145.400  751.600 154.600  818.000 154.600  818.000 175.400  751.600 175.400  751.600 184.600  818.000 184.600  818.000 205.400  751.600 205.400  751.600 214.600  818.000 214.600  818.000 235.400  751.600 235.400  751.600 244.600  818.000 244.600  818.000 265.400  751.600 265.400  751.600 274.600  818.000 274.600  818.000 276.900  821.000 276.900  821.000 300.000  300.000 300.000  300.000 821.000  276.900 821.000  276.900 818.000  274.600 818.000  274.600 751.600  265.400 751.600  265.400 818.000  244.600 818.000  244.600 751.600  235.400 751.600  235.400 818.000  214.600 818.000  214.600 751.600  205.400 751.600  205.400 818.000  184.600 818.000  184.600 751.600  175.400 751.600  175.400 818.000  154.600 818.000  154.600 751.600  145.400 751.600  145.400 818.000  143.000 818.000  143.000 845.000  300.000 845.000  300.000 855.000  143.000 855.000  143.000 882.000  145.400 882.000  145.400 948.400  154.600 948.400  154.600 882.000  175.400 882.000  175.400 948.400  184.600 948.400  184.600 882.000  205.400 882.000  205.400 948.400  214.600 948.400  214.600 882.000  235.400 882.000  235.400 948.400  244.600 948.400  244.600 882.000  265.400 882.000  265.400 948.400  274.600 948.400  274.600 882.000  276.900 882.000  276.900 879.000  300.000 879.000  300.000 1621.000  276.900 1621.000  276.900 1618.000  274.600 1618.000  274.600 1551.600  265.400 1551.600  265.400 1618.000  244.600 1618.000  244.600 1551.600  235.400 1551.600  235.400 1618.000  214.600 1618.000  214.600 1551.600  205.400 1551.600  205.400 1618.000  184.600 1618.000  184.600 1551.600  175.400 1551.600  175.400 1618.000  154.600 1618.000  154.600 1551.600  145.400 1551.600  145.400 1618.000  143.000 1618.000  143.000 1645.000  300.000 1645.000  300.000 1655.000  143.000 1655.000  143.000 1682.000  145.400 1682.000  145.400 1748.400  154.600 1748.400  154.600 1682.000  175.400 1682.000  175.400 1748.400  184.600 1748.400  184.600 1682.000  205.400 1682.000  205.400 1748.400  214.600 1748.400  214.600 1682.000  235.400 1682.000  235.400 1748.400  244.600 1748.400  244.600 1682.000  265.400 1682.000  265.400 1748.400  274.600 1748.400  274.600 1682.000  276.900 1682.000  276.900 1679.000  300.000 1679.000  300.000 2200.000  821.000 2200.000  821.000 2223.100  818.000 2223.100  818.000 2225.400  751.600 2225.400  751.600 2234.600  818.000 2234.600  818.000 2255.400  751.600 2255.400  751.600 2264.600  818.000 2264.600  818.000 2285.400  751.600 2285.400  751.600 2294.600  818.000 2294.600  818.000 2315.400  751.600 2315.400  751.600 2324.600  818.000 2324.600  818.000 2345.400  751.600 2345.400  751.600 2354.600  818.000 2354.600  818.000 2357.000  845.000 2357.000  845.000 2200.000  855.000 2200.000  855.000 2357.000  882.000 2357.000  882.000 2354.600  948.400 2354.600  948.400 2345.400  882.000 2345.400  882.000 2324.600  948.400 2324.600  948.400 2315.400  882.000 2315.400  882.000 2294.600  948.400 2294.600  948.400 2285.400  882.000 2285.400  882.000 2264.600  948.400 2264.600  948.400 2255.400  882.000 2255.400  882.000 2234.600  948.400 2234.600  948.400 2225.400  882.000 2225.400  882.000 2223.100  879.000 2223.100  879.000 2200.000  1254.900 2200.000  1254.900 2371.000  1351.300 2371.000  1351.300 2361.800  1273.000 2361.800  1273.000 2339.600  1351.300 2339.600  1351.300 2330.400  1273.000 2330.400  1273.000 2309.600  1351.300 2309.600  1351.300 2300.400  1273.000 2300.400  1273.000 2279.600  1351.300 2279.600  1351.300 2270.400  1273.000 2270.400  1273.000 2249.600  1351.300 2249.600  1351.300 2240.400  1273.000 2240.400  1273.000 2218.200  1351.300 2218.200  1351.300 2209.000  1270.900 2209.000  1270.900 2200.000  1621.100 2200.000  1621.100 2223.100  1618.000 2223.100  1618.000 2225.400  1551.600 2225.400  1551.600 2234.600  1618.000 2234.600  1618.000 2255.400  1551.600 2255.400  1551.600 2264.600  1618.000 2264.600  1618.000 2285.400  1551.600 2285.400  1551.600 2294.600  1618.000 2294.600  1618.000 2315.400  1551.600 2315.400  1551.600 2324.600  1618.000 2324.600  1618.000 2345.400  1551.600 2345.400  1551.600 2354.600  1618.000 2354.600  1618.000 2357.000  1645.100 2357.000  1645.100 2200.000  1655.000 2200.000  1655.000 2357.000  1682.000 2357.000  1682.000 2354.600  1748.400 2354.600  1748.400 2345.400  1682.000 2345.400  1682.000 2324.600  1748.400 2324.600  1748.400 2315.400  1682.000 2315.400  1682.000 2294.600  1748.400 2294.600  1748.400 2285.400  1682.000 2285.400  1682.000 2264.600  1748.400 2264.600  1748.400 2255.400  1682.000 2255.400  1682.000 2234.600  1748.400 2234.600  1748.400 2225.400  1682.000 2225.400  1682.000 2223.100  1679.000 2223.100  1679.000 2200.000  2200.000 2200.000  2200.000 1679.000  2223.100 1679.000  2223.100 1682.000  2225.400 1682.000  2225.400 1748.400  2234.600 1748.400  2234.600 1682.000  2255.400 1682.000  2255.400 1748.400  2264.600 1748.400  2264.600 1682.000  2285.400 1682.000  2285.400 1748.400  2294.600 1748.400  2294.600 1682.000  2315.400 1682.000  2315.400 1748.400  2324.600 1748.400  2324.600 1682.000  2345.400 1682.000  2345.400 1748.400  2354.600 1748.400  2354.600 1682.000  2357.000 1682.000  2357.000 1655.000  2200.000 1655.000  2200.000 1645.000  2357.000 1645.000  2357.000 1618.000  2354.600 1618.000  2354.600 1551.600  2345.400 1551.600  2345.400 1618.000  2324.600 1618.000  2324.600 1551.600  2315.400 1551.600  2315.400 1618.000  2294.600 1618.000  2294.600 1551.600  2285.400 1551.600  2285.400 1618.000  2264.600 1618.000  2264.600 1551.600  2255.400 1551.600  2255.400 1618.000  2234.600 1618.000  2234.600 1551.600  2225.400 1551.600  2225.400 1618.000  2223.100 1618.000  2223.100 1621.000  2200.000 1621.000  2200.000 879.000  2223.100 879.000  2223.100 882.000  2225.400 882.000  2225.400 948.400  2234.600 948.400  2234.600 882.000  2255.400 882.000  2255.400 948.400  2264.600 948.400  2264.600 882.000  2285.400 882.000  2285.400 948.400  2294.600 948.400  2294.600 882.000  2315.400 882.000  2315.400 948.400  2324.600 948.400  2324.600 882.000  2345.400 882.000  2345.400 948.400  2354.600 948.400  2354.600 882.000  2357.000 882.000  2357.000 855.000  2200.000 855.000  2200.000 845.000  2357.000 845.000  2357.000 818.000  2354.600 818.000  2354.600 751.600  2345.400 751.600  2345.400 818.000  2324.600 818.000  2324.600 751.600  2315.400 751.600  2315.400 818.000  2294.600 818.000  2294.600 751.600  2285.400 751.600  2285.400 818.000  2264.600 818.000  2264.600 751.600  2255.400 751.600  2255.400 818.000  2234.600 818.000  2234.600 751.600  2225.400 751.600  2225.400 818.000  2223.100 818.000  2223.100 821.000  2200.000 821.000  2200.000 300.000  1679.000 300.000  1679.000 276.900  1682.000 276.900  1682.000 274.600  1748.400 274.600  1748.400 265.400  1682.000 265.400  1682.000 244.600  1748.400 244.600  1748.400 235.400  1682.000 235.400  1682.000 214.600  1748.400 214.600  1748.400 205.400  1682.000 205.400  1682.000 184.600  1748.400 184.600  1748.400 175.400  1682.000 175.400  1682.000 154.600  1748.400 154.600  1748.400 145.400  1682.000 145.400  1682.000 143.000  1655.000 143.000  1655.000 300.000  1645.000 300.000  1645.000 143.000  1618.000 143.000  1618.000 145.400  1551.600 145.400  1551.600 154.600  1618.000 154.600  1618.000 175.400  1551.600 175.400  1551.600 184.600  1618.000 184.600  1618.000 205.400  1551.600 205.400  1551.600 214.600  1618.000 214.600  1618.000 235.400  1551.600 235.400  1551.600 244.600  1618.000 244.600  1618.000 265.400  1551.600 265.400  1551.600 274.600  1618.000 274.600  1618.000 276.900  1621.000 276.900  1621.000 300.000  1100.000 300.000  1100.000 260.000  1123.800 260.000  1123.800 291.000  1211.300 291.000  1211.300 281.800  1133.000 281.800  1133.000 259.600  1211.300 259.600  1211.300 250.400  1133.000 250.400  1133.000 229.600  1211.300 229.600  1211.300 220.400  1133.000 220.400  1133.000 199.600  1211.300 199.600  1211.300 190.400  1133.000 190.400  1133.000 169.600  1211.300 169.600  1211.300 160.400  1133.000 160.400  1133.000 138.200  1211.300 138.200  1211.300 129.000 ;
            POLYGON 1688.700 2209.000  1688.700 2218.200  1766.000 2218.200  1766.000 2240.400  1688.700 2240.400  1688.700 2249.600  1766.000 2249.600  1766.000 2270.400  1688.700 2270.400  1688.700 2279.600  1766.000 2279.600  1766.000 2300.400  1688.700 2300.400  1688.700 2309.600  1766.000 2309.600  1766.000 2330.400  1688.700 2330.400  1688.700 2339.600  1766.000 2339.600  1766.000 2361.800  1688.700 2361.800  1688.700 2371.000  1775.200 2371.000  1775.200 2340.000  1923.800 2340.000  1923.800 2371.000  2011.300 2371.000  2011.300 2361.800  1933.000 2361.800  1933.000 2339.600  2011.300 2339.600  2011.300 2330.400  1933.000 2330.400  1933.000 2309.600  2011.300 2309.600  2011.300 2300.400  1933.000 2300.400  1933.000 2279.600  2011.300 2279.600  2011.300 2270.400  1933.000 2270.400  1933.000 2249.600  2011.300 2249.600  2011.300 2240.400  1933.000 2240.400  1933.000 2218.200  2011.300 2218.200  2011.300 2209.000  1923.800 2209.000  1923.800 2240.000  1775.200 2240.000  1775.200 2209.000 ;
            POLYGON 90.000 90.000  90.000 2410.000  2410.000 2410.000  2410.000 90.000 ;
            POLYGON 54.000 54.000  54.000 2446.000  2446.000 2446.000  2446.000 54.000 ;
    END

END OSS_FRAME_GIO
